VERSION 5.8 ;
BUSBITCHARS "[]" ;
DIVIDERCHAR "/" ;
UNITS
    DATABASE MICRONS 1000 ;
END UNITS

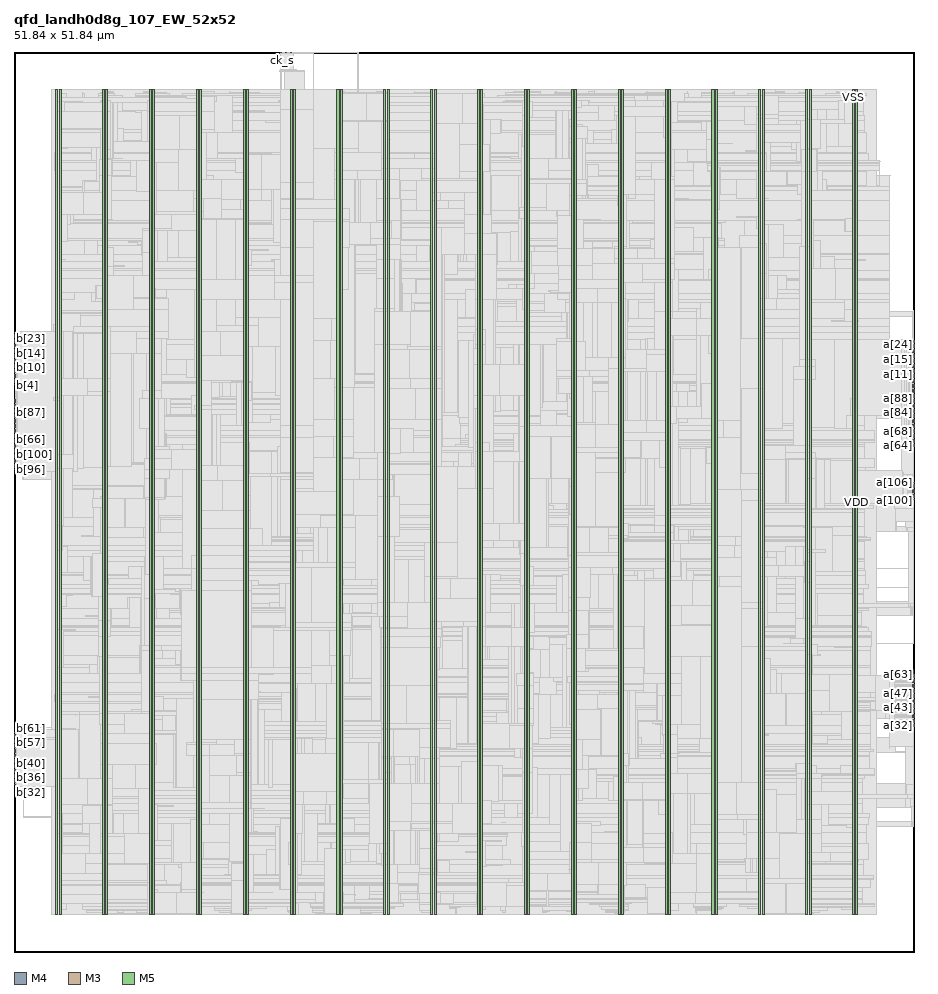
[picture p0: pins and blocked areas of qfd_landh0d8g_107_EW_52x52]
MACRO qfd_landh0d8g_107_EW_52x52
  FOREIGN qfd_landh0d8g_107_EW_52x52 0 0 ;
  CLASS BLOCK ;
  SIZE 51.84 BY 51.84 ;
  PIN a[0]
    DIRECTION INPUT ;
    USE SIGNAL ;
    PORT
      LAYER M4 ;
        RECT  51.756 32.208 51.84 32.232 ;
    END
  END a[0]
  PIN a[100]
    DIRECTION INPUT ;
    USE SIGNAL ;
    PORT
      LAYER M4 ;
        RECT  51.756 26.448 51.84 26.472 ;
    END
  END a[100]
  PIN a[101]
    DIRECTION INPUT ;
    USE SIGNAL ;
    PORT
      LAYER M4 ;
        RECT  51.756 26.544 51.84 26.568 ;
    END
  END a[101]
  PIN a[102]
    DIRECTION INPUT ;
    USE SIGNAL ;
    PORT
      LAYER M4 ;
        RECT  51.756 26.64 51.84 26.664 ;
    END
  END a[102]
  PIN a[103]
    DIRECTION INPUT ;
    USE SIGNAL ;
    PORT
      LAYER M4 ;
        RECT  51.756 26.736 51.84 26.76 ;
    END
  END a[103]
  PIN a[104]
    DIRECTION INPUT ;
    USE SIGNAL ;
    PORT
      LAYER M4 ;
        RECT  51.756 26.832 51.84 26.856 ;
    END
  END a[104]
  PIN a[105]
    DIRECTION INPUT ;
    USE SIGNAL ;
    PORT
      LAYER M4 ;
        RECT  51.756 26.928 51.84 26.952 ;
    END
  END a[105]
  PIN a[106]
    DIRECTION INPUT ;
    USE SIGNAL ;
    PORT
      LAYER M4 ;
        RECT  51.756 27.024 51.84 27.048 ;
    END
  END a[106]
  PIN a[10]
    DIRECTION INPUT ;
    USE SIGNAL ;
    PORT
      LAYER M4 ;
        RECT  51.756 33.168 51.84 33.192 ;
    END
  END a[10]
  PIN a[11]
    DIRECTION INPUT ;
    USE SIGNAL ;
    PORT
      LAYER M4 ;
        RECT  51.756 33.264 51.84 33.288 ;
    END
  END a[11]
  PIN a[12]
    DIRECTION INPUT ;
    USE SIGNAL ;
    PORT
      LAYER M4 ;
        RECT  51.756 33.36 51.84 33.384 ;
    END
  END a[12]
  PIN a[13]
    DIRECTION INPUT ;
    USE SIGNAL ;
    PORT
      LAYER M4 ;
        RECT  51.756 33.456 51.84 33.48 ;
    END
  END a[13]
  PIN a[14]
    DIRECTION INPUT ;
    USE SIGNAL ;
    PORT
      LAYER M4 ;
        RECT  51.756 33.552 51.84 33.576 ;
    END
  END a[14]
  PIN a[15]
    DIRECTION INPUT ;
    USE SIGNAL ;
    PORT
      LAYER M4 ;
        RECT  51.756 33.648 51.84 33.672 ;
    END
  END a[15]
  PIN a[16]
    DIRECTION INPUT ;
    USE SIGNAL ;
    PORT
      LAYER M4 ;
        RECT  51.756 33.744 51.84 33.768 ;
    END
  END a[16]
  PIN a[17]
    DIRECTION INPUT ;
    USE SIGNAL ;
    PORT
      LAYER M4 ;
        RECT  51.756 33.84 51.84 33.864 ;
    END
  END a[17]
  PIN a[18]
    DIRECTION INPUT ;
    USE SIGNAL ;
    PORT
      LAYER M4 ;
        RECT  51.756 33.936 51.84 33.96 ;
    END
  END a[18]
  PIN a[19]
    DIRECTION INPUT ;
    USE SIGNAL ;
    PORT
      LAYER M4 ;
        RECT  51.756 34.032 51.84 34.056 ;
    END
  END a[19]
  PIN a[1]
    DIRECTION INPUT ;
    USE SIGNAL ;
    PORT
      LAYER M4 ;
        RECT  51.756 32.304 51.84 32.328 ;
    END
  END a[1]
  PIN a[20]
    DIRECTION INPUT ;
    USE SIGNAL ;
    PORT
      LAYER M4 ;
        RECT  51.756 34.128 51.84 34.152 ;
    END
  END a[20]
  PIN a[21]
    DIRECTION INPUT ;
    USE SIGNAL ;
    PORT
      LAYER M4 ;
        RECT  51.756 34.224 51.84 34.248 ;
    END
  END a[21]
  PIN a[22]
    DIRECTION INPUT ;
    USE SIGNAL ;
    PORT
      LAYER M4 ;
        RECT  51.756 34.32 51.84 34.344 ;
    END
  END a[22]
  PIN a[23]
    DIRECTION INPUT ;
    USE SIGNAL ;
    PORT
      LAYER M4 ;
        RECT  51.756 34.416 51.84 34.44 ;
    END
  END a[23]
  PIN a[24]
    DIRECTION INPUT ;
    USE SIGNAL ;
    PORT
      LAYER M4 ;
        RECT  51.756 34.512 51.84 34.536 ;
    END
  END a[24]
  PIN a[25]
    DIRECTION INPUT ;
    USE SIGNAL ;
    PORT
      LAYER M4 ;
        RECT  51.756 34.608 51.84 34.632 ;
    END
  END a[25]
  PIN a[26]
    DIRECTION INPUT ;
    USE SIGNAL ;
    PORT
      LAYER M4 ;
        RECT  51.756 34.704 51.84 34.728 ;
    END
  END a[26]
  PIN a[27]
    DIRECTION INPUT ;
    USE SIGNAL ;
    PORT
      LAYER M4 ;
        RECT  51.756 34.8 51.84 34.824 ;
    END
  END a[27]
  PIN a[28]
    DIRECTION INPUT ;
    USE SIGNAL ;
    PORT
      LAYER M4 ;
        RECT  51.756 34.896 51.84 34.92 ;
    END
  END a[28]
  PIN a[29]
    DIRECTION INPUT ;
    USE SIGNAL ;
    PORT
      LAYER M4 ;
        RECT  51.756 34.992 51.84 35.016 ;
    END
  END a[29]
  PIN a[2]
    DIRECTION INPUT ;
    USE SIGNAL ;
    PORT
      LAYER M4 ;
        RECT  51.756 32.4 51.84 32.424 ;
    END
  END a[2]
  PIN a[30]
    DIRECTION INPUT ;
    USE SIGNAL ;
    PORT
      LAYER M4 ;
        RECT  51.756 35.088 51.84 35.112 ;
    END
  END a[30]
  PIN a[31]
    DIRECTION INPUT ;
    USE SIGNAL ;
    PORT
      LAYER M4 ;
        RECT  51.756 35.184 51.84 35.208 ;
    END
  END a[31]
  PIN a[32]
    DIRECTION INPUT ;
    USE SIGNAL ;
    PORT
      LAYER M4 ;
        RECT  51.756 13.008 51.84 13.032 ;
    END
  END a[32]
  PIN a[33]
    DIRECTION INPUT ;
    USE SIGNAL ;
    PORT
      LAYER M4 ;
        RECT  51.756 13.104 51.84 13.128 ;
    END
  END a[33]
  PIN a[34]
    DIRECTION INPUT ;
    USE SIGNAL ;
    PORT
      LAYER M4 ;
        RECT  51.756 13.2 51.84 13.224 ;
    END
  END a[34]
  PIN a[35]
    DIRECTION INPUT ;
    USE SIGNAL ;
    PORT
      LAYER M4 ;
        RECT  51.756 13.296 51.84 13.32 ;
    END
  END a[35]
  PIN a[36]
    DIRECTION INPUT ;
    USE SIGNAL ;
    PORT
      LAYER M4 ;
        RECT  51.756 13.392 51.84 13.416 ;
    END
  END a[36]
  PIN a[37]
    DIRECTION INPUT ;
    USE SIGNAL ;
    PORT
      LAYER M4 ;
        RECT  51.756 13.488 51.84 13.512 ;
    END
  END a[37]
  PIN a[38]
    DIRECTION INPUT ;
    USE SIGNAL ;
    PORT
      LAYER M4 ;
        RECT  51.756 13.584 51.84 13.608 ;
    END
  END a[38]
  PIN a[39]
    DIRECTION INPUT ;
    USE SIGNAL ;
    PORT
      LAYER M4 ;
        RECT  51.756 13.68 51.84 13.704 ;
    END
  END a[39]
  PIN a[3]
    DIRECTION INPUT ;
    USE SIGNAL ;
    PORT
      LAYER M4 ;
        RECT  51.756 32.496 51.84 32.52 ;
    END
  END a[3]
  PIN a[40]
    DIRECTION INPUT ;
    USE SIGNAL ;
    PORT
      LAYER M4 ;
        RECT  51.756 13.776 51.84 13.8 ;
    END
  END a[40]
  PIN a[41]
    DIRECTION INPUT ;
    USE SIGNAL ;
    PORT
      LAYER M4 ;
        RECT  51.756 13.872 51.84 13.896 ;
    END
  END a[41]
  PIN a[42]
    DIRECTION INPUT ;
    USE SIGNAL ;
    PORT
      LAYER M4 ;
        RECT  51.756 13.968 51.84 13.992 ;
    END
  END a[42]
  PIN a[43]
    DIRECTION INPUT ;
    USE SIGNAL ;
    PORT
      LAYER M4 ;
        RECT  51.756 14.064 51.84 14.088 ;
    END
  END a[43]
  PIN a[44]
    DIRECTION INPUT ;
    USE SIGNAL ;
    PORT
      LAYER M4 ;
        RECT  51.756 14.16 51.84 14.184 ;
    END
  END a[44]
  PIN a[45]
    DIRECTION INPUT ;
    USE SIGNAL ;
    PORT
      LAYER M4 ;
        RECT  51.756 14.256 51.84 14.28 ;
    END
  END a[45]
  PIN a[46]
    DIRECTION INPUT ;
    USE SIGNAL ;
    PORT
      LAYER M4 ;
        RECT  51.756 14.352 51.84 14.376 ;
    END
  END a[46]
  PIN a[47]
    DIRECTION INPUT ;
    USE SIGNAL ;
    PORT
      LAYER M4 ;
        RECT  51.756 14.448 51.84 14.472 ;
    END
  END a[47]
  PIN a[48]
    DIRECTION INPUT ;
    USE SIGNAL ;
    PORT
      LAYER M4 ;
        RECT  51.756 14.544 51.84 14.568 ;
    END
  END a[48]
  PIN a[49]
    DIRECTION INPUT ;
    USE SIGNAL ;
    PORT
      LAYER M4 ;
        RECT  51.756 14.64 51.84 14.664 ;
    END
  END a[49]
  PIN a[4]
    DIRECTION INPUT ;
    USE SIGNAL ;
    PORT
      LAYER M4 ;
        RECT  51.756 32.592 51.84 32.616 ;
    END
  END a[4]
  PIN a[50]
    DIRECTION INPUT ;
    USE SIGNAL ;
    PORT
      LAYER M4 ;
        RECT  51.756 14.736 51.84 14.76 ;
    END
  END a[50]
  PIN a[51]
    DIRECTION INPUT ;
    USE SIGNAL ;
    PORT
      LAYER M4 ;
        RECT  51.756 14.832 51.84 14.856 ;
    END
  END a[51]
  PIN a[52]
    DIRECTION INPUT ;
    USE SIGNAL ;
    PORT
      LAYER M4 ;
        RECT  51.756 14.928 51.84 14.952 ;
    END
  END a[52]
  PIN a[53]
    DIRECTION INPUT ;
    USE SIGNAL ;
    PORT
      LAYER M4 ;
        RECT  51.756 15.024 51.84 15.048 ;
    END
  END a[53]
  PIN a[54]
    DIRECTION INPUT ;
    USE SIGNAL ;
    PORT
      LAYER M4 ;
        RECT  51.756 15.12 51.84 15.144 ;
    END
  END a[54]
  PIN a[55]
    DIRECTION INPUT ;
    USE SIGNAL ;
    PORT
      LAYER M4 ;
        RECT  51.756 15.216 51.84 15.24 ;
    END
  END a[55]
  PIN a[56]
    DIRECTION INPUT ;
    USE SIGNAL ;
    PORT
      LAYER M4 ;
        RECT  51.756 15.312 51.84 15.336 ;
    END
  END a[56]
  PIN a[57]
    DIRECTION INPUT ;
    USE SIGNAL ;
    PORT
      LAYER M4 ;
        RECT  51.756 15.408 51.84 15.432 ;
    END
  END a[57]
  PIN a[58]
    DIRECTION INPUT ;
    USE SIGNAL ;
    PORT
      LAYER M4 ;
        RECT  51.756 15.504 51.84 15.528 ;
    END
  END a[58]
  PIN a[59]
    DIRECTION INPUT ;
    USE SIGNAL ;
    PORT
      LAYER M4 ;
        RECT  51.756 15.6 51.84 15.624 ;
    END
  END a[59]
  PIN a[5]
    DIRECTION INPUT ;
    USE SIGNAL ;
    PORT
      LAYER M4 ;
        RECT  51.756 32.688 51.84 32.712 ;
    END
  END a[5]
  PIN a[60]
    DIRECTION INPUT ;
    USE SIGNAL ;
    PORT
      LAYER M4 ;
        RECT  51.756 15.696 51.84 15.72 ;
    END
  END a[60]
  PIN a[61]
    DIRECTION INPUT ;
    USE SIGNAL ;
    PORT
      LAYER M4 ;
        RECT  51.756 15.792 51.84 15.816 ;
    END
  END a[61]
  PIN a[62]
    DIRECTION INPUT ;
    USE SIGNAL ;
    PORT
      LAYER M4 ;
        RECT  51.756 15.888 51.84 15.912 ;
    END
  END a[62]
  PIN a[63]
    DIRECTION INPUT ;
    USE SIGNAL ;
    PORT
      LAYER M4 ;
        RECT  51.756 15.984 51.84 16.008 ;
    END
  END a[63]
  PIN a[64]
    DIRECTION INPUT ;
    USE SIGNAL ;
    PORT
      LAYER M4 ;
        RECT  51.756 29.136 51.84 29.16 ;
    END
  END a[64]
  PIN a[65]
    DIRECTION INPUT ;
    USE SIGNAL ;
    PORT
      LAYER M4 ;
        RECT  51.756 29.232 51.84 29.256 ;
    END
  END a[65]
  PIN a[66]
    DIRECTION INPUT ;
    USE SIGNAL ;
    PORT
      LAYER M4 ;
        RECT  51.756 29.328 51.84 29.352 ;
    END
  END a[66]
  PIN a[67]
    DIRECTION INPUT ;
    USE SIGNAL ;
    PORT
      LAYER M4 ;
        RECT  51.756 29.424 51.84 29.448 ;
    END
  END a[67]
  PIN a[68]
    DIRECTION INPUT ;
    USE SIGNAL ;
    PORT
      LAYER M4 ;
        RECT  51.756 29.52 51.84 29.544 ;
    END
  END a[68]
  PIN a[69]
    DIRECTION INPUT ;
    USE SIGNAL ;
    PORT
      LAYER M4 ;
        RECT  51.756 29.616 51.84 29.64 ;
    END
  END a[69]
  PIN a[6]
    DIRECTION INPUT ;
    USE SIGNAL ;
    PORT
      LAYER M4 ;
        RECT  51.756 32.784 51.84 32.808 ;
    END
  END a[6]
  PIN a[70]
    DIRECTION INPUT ;
    USE SIGNAL ;
    PORT
      LAYER M4 ;
        RECT  51.756 29.712 51.84 29.736 ;
    END
  END a[70]
  PIN a[71]
    DIRECTION INPUT ;
    USE SIGNAL ;
    PORT
      LAYER M4 ;
        RECT  51.756 29.808 51.84 29.832 ;
    END
  END a[71]
  PIN a[72]
    DIRECTION INPUT ;
    USE SIGNAL ;
    PORT
      LAYER M4 ;
        RECT  51.756 29.904 51.84 29.928 ;
    END
  END a[72]
  PIN a[73]
    DIRECTION INPUT ;
    USE SIGNAL ;
    PORT
      LAYER M4 ;
        RECT  51.756 30 51.84 30.024 ;
    END
  END a[73]
  PIN a[74]
    DIRECTION INPUT ;
    USE SIGNAL ;
    PORT
      LAYER M4 ;
        RECT  51.756 30.096 51.84 30.12 ;
    END
  END a[74]
  PIN a[75]
    DIRECTION INPUT ;
    USE SIGNAL ;
    PORT
      LAYER M4 ;
        RECT  51.756 30.192 51.84 30.216 ;
    END
  END a[75]
  PIN a[76]
    DIRECTION INPUT ;
    USE SIGNAL ;
    PORT
      LAYER M4 ;
        RECT  51.756 30.288 51.84 30.312 ;
    END
  END a[76]
  PIN a[77]
    DIRECTION INPUT ;
    USE SIGNAL ;
    PORT
      LAYER M4 ;
        RECT  51.756 30.384 51.84 30.408 ;
    END
  END a[77]
  PIN a[78]
    DIRECTION INPUT ;
    USE SIGNAL ;
    PORT
      LAYER M4 ;
        RECT  51.756 30.48 51.84 30.504 ;
    END
  END a[78]
  PIN a[79]
    DIRECTION INPUT ;
    USE SIGNAL ;
    PORT
      LAYER M4 ;
        RECT  51.756 30.576 51.84 30.6 ;
    END
  END a[79]
  PIN a[7]
    DIRECTION INPUT ;
    USE SIGNAL ;
    PORT
      LAYER M4 ;
        RECT  51.756 32.88 51.84 32.904 ;
    END
  END a[7]
  PIN a[80]
    DIRECTION INPUT ;
    USE SIGNAL ;
    PORT
      LAYER M4 ;
        RECT  51.756 30.672 51.84 30.696 ;
    END
  END a[80]
  PIN a[81]
    DIRECTION INPUT ;
    USE SIGNAL ;
    PORT
      LAYER M4 ;
        RECT  51.756 30.768 51.84 30.792 ;
    END
  END a[81]
  PIN a[82]
    DIRECTION INPUT ;
    USE SIGNAL ;
    PORT
      LAYER M4 ;
        RECT  51.756 30.864 51.84 30.888 ;
    END
  END a[82]
  PIN a[83]
    DIRECTION INPUT ;
    USE SIGNAL ;
    PORT
      LAYER M4 ;
        RECT  51.756 30.96 51.84 30.984 ;
    END
  END a[83]
  PIN a[84]
    DIRECTION INPUT ;
    USE SIGNAL ;
    PORT
      LAYER M4 ;
        RECT  51.756 31.056 51.84 31.08 ;
    END
  END a[84]
  PIN a[85]
    DIRECTION INPUT ;
    USE SIGNAL ;
    PORT
      LAYER M4 ;
        RECT  51.756 31.152 51.84 31.176 ;
    END
  END a[85]
  PIN a[86]
    DIRECTION INPUT ;
    USE SIGNAL ;
    PORT
      LAYER M4 ;
        RECT  51.756 31.248 51.84 31.272 ;
    END
  END a[86]
  PIN a[87]
    DIRECTION INPUT ;
    USE SIGNAL ;
    PORT
      LAYER M4 ;
        RECT  51.756 31.344 51.84 31.368 ;
    END
  END a[87]
  PIN a[88]
    DIRECTION INPUT ;
    USE SIGNAL ;
    PORT
      LAYER M4 ;
        RECT  51.756 31.44 51.84 31.464 ;
    END
  END a[88]
  PIN a[89]
    DIRECTION INPUT ;
    USE SIGNAL ;
    PORT
      LAYER M4 ;
        RECT  51.756 31.536 51.84 31.56 ;
    END
  END a[89]
  PIN a[8]
    DIRECTION INPUT ;
    USE SIGNAL ;
    PORT
      LAYER M4 ;
        RECT  51.756 32.976 51.84 33 ;
    END
  END a[8]
  PIN a[90]
    DIRECTION INPUT ;
    USE SIGNAL ;
    PORT
      LAYER M4 ;
        RECT  51.756 31.632 51.84 31.656 ;
    END
  END a[90]
  PIN a[91]
    DIRECTION INPUT ;
    USE SIGNAL ;
    PORT
      LAYER M4 ;
        RECT  51.756 31.728 51.84 31.752 ;
    END
  END a[91]
  PIN a[92]
    DIRECTION INPUT ;
    USE SIGNAL ;
    PORT
      LAYER M4 ;
        RECT  51.756 31.824 51.84 31.848 ;
    END
  END a[92]
  PIN a[93]
    DIRECTION INPUT ;
    USE SIGNAL ;
    PORT
      LAYER M4 ;
        RECT  51.756 31.92 51.84 31.944 ;
    END
  END a[93]
  PIN a[94]
    DIRECTION INPUT ;
    USE SIGNAL ;
    PORT
      LAYER M4 ;
        RECT  51.756 32.016 51.84 32.04 ;
    END
  END a[94]
  PIN a[95]
    DIRECTION INPUT ;
    USE SIGNAL ;
    PORT
      LAYER M4 ;
        RECT  51.756 32.112 51.84 32.136 ;
    END
  END a[95]
  PIN a[96]
    DIRECTION INPUT ;
    USE SIGNAL ;
    PORT
      LAYER M4 ;
        RECT  51.756 26.064 51.84 26.088 ;
    END
  END a[96]
  PIN a[97]
    DIRECTION INPUT ;
    USE SIGNAL ;
    PORT
      LAYER M4 ;
        RECT  51.756 26.16 51.84 26.184 ;
    END
  END a[97]
  PIN a[98]
    DIRECTION INPUT ;
    USE SIGNAL ;
    PORT
      LAYER M4 ;
        RECT  51.756 26.256 51.84 26.28 ;
    END
  END a[98]
  PIN a[99]
    DIRECTION INPUT ;
    USE SIGNAL ;
    PORT
      LAYER M4 ;
        RECT  51.756 26.352 51.84 26.376 ;
    END
  END a[99]
  PIN a[9]
    DIRECTION INPUT ;
    USE SIGNAL ;
    PORT
      LAYER M4 ;
        RECT  51.756 33.072 51.84 33.096 ;
    END
  END a[9]
  PIN b[0]
    DIRECTION OUTPUT ;
    USE SIGNAL ;
    PORT
      LAYER M4 ;
        RECT  0 32.688 0.084 32.712 ;
    END
  END b[0]
  PIN b[100]
    DIRECTION OUTPUT ;
    USE SIGNAL ;
    PORT
      LAYER M4 ;
        RECT  0 28.176 0.084 28.2 ;
    END
  END b[100]
  PIN b[101]
    DIRECTION OUTPUT ;
    USE SIGNAL ;
    PORT
      LAYER M4 ;
        RECT  0 28.272 0.084 28.296 ;
    END
  END b[101]
  PIN b[102]
    DIRECTION OUTPUT ;
    USE SIGNAL ;
    PORT
      LAYER M4 ;
        RECT  0 28.368 0.084 28.392 ;
    END
  END b[102]
  PIN b[103]
    DIRECTION OUTPUT ;
    USE SIGNAL ;
    PORT
      LAYER M4 ;
        RECT  0 28.464 0.084 28.488 ;
    END
  END b[103]
  PIN b[104]
    DIRECTION OUTPUT ;
    USE SIGNAL ;
    PORT
      LAYER M4 ;
        RECT  0 28.56 0.084 28.584 ;
    END
  END b[104]
  PIN b[105]
    DIRECTION OUTPUT ;
    USE SIGNAL ;
    PORT
      LAYER M4 ;
        RECT  0 28.656 0.084 28.68 ;
    END
  END b[105]
  PIN b[106]
    DIRECTION OUTPUT ;
    USE SIGNAL ;
    PORT
      LAYER M4 ;
        RECT  0 28.752 0.084 28.776 ;
    END
  END b[106]
  PIN b[10]
    DIRECTION OUTPUT ;
    USE SIGNAL ;
    PORT
      LAYER M4 ;
        RECT  0 33.648 0.084 33.672 ;
    END
  END b[10]
  PIN b[11]
    DIRECTION OUTPUT ;
    USE SIGNAL ;
    PORT
      LAYER M4 ;
        RECT  0 33.744 0.084 33.768 ;
    END
  END b[11]
  PIN b[12]
    DIRECTION OUTPUT ;
    USE SIGNAL ;
    PORT
      LAYER M4 ;
        RECT  0 33.84 0.084 33.864 ;
    END
  END b[12]
  PIN b[13]
    DIRECTION OUTPUT ;
    USE SIGNAL ;
    PORT
      LAYER M4 ;
        RECT  0 33.936 0.084 33.96 ;
    END
  END b[13]
  PIN b[14]
    DIRECTION OUTPUT ;
    USE SIGNAL ;
    PORT
      LAYER M4 ;
        RECT  0 34.032 0.084 34.056 ;
    END
  END b[14]
  PIN b[15]
    DIRECTION OUTPUT ;
    USE SIGNAL ;
    PORT
      LAYER M4 ;
        RECT  0 34.128 0.084 34.152 ;
    END
  END b[15]
  PIN b[16]
    DIRECTION OUTPUT ;
    USE SIGNAL ;
    PORT
      LAYER M4 ;
        RECT  0 34.224 0.084 34.248 ;
    END
  END b[16]
  PIN b[17]
    DIRECTION OUTPUT ;
    USE SIGNAL ;
    PORT
      LAYER M4 ;
        RECT  0 34.32 0.084 34.344 ;
    END
  END b[17]
  PIN b[18]
    DIRECTION OUTPUT ;
    USE SIGNAL ;
    PORT
      LAYER M4 ;
        RECT  0 34.416 0.084 34.44 ;
    END
  END b[18]
  PIN b[19]
    DIRECTION OUTPUT ;
    USE SIGNAL ;
    PORT
      LAYER M4 ;
        RECT  0 34.512 0.084 34.536 ;
    END
  END b[19]
  PIN b[1]
    DIRECTION OUTPUT ;
    USE SIGNAL ;
    PORT
      LAYER M4 ;
        RECT  0 32.784 0.084 32.808 ;
    END
  END b[1]
  PIN b[20]
    DIRECTION OUTPUT ;
    USE SIGNAL ;
    PORT
      LAYER M4 ;
        RECT  0 34.608 0.084 34.632 ;
    END
  END b[20]
  PIN b[21]
    DIRECTION OUTPUT ;
    USE SIGNAL ;
    PORT
      LAYER M4 ;
        RECT  0 34.704 0.084 34.728 ;
    END
  END b[21]
  PIN b[22]
    DIRECTION OUTPUT ;
    USE SIGNAL ;
    PORT
      LAYER M4 ;
        RECT  0 34.8 0.084 34.824 ;
    END
  END b[22]
  PIN b[23]
    DIRECTION OUTPUT ;
    USE SIGNAL ;
    PORT
      LAYER M4 ;
        RECT  0 34.896 0.084 34.92 ;
    END
  END b[23]
  PIN b[24]
    DIRECTION OUTPUT ;
    USE SIGNAL ;
    PORT
      LAYER M4 ;
        RECT  0 34.992 0.084 35.016 ;
    END
  END b[24]
  PIN b[25]
    DIRECTION OUTPUT ;
    USE SIGNAL ;
    PORT
      LAYER M4 ;
        RECT  0 35.088 0.084 35.112 ;
    END
  END b[25]
  PIN b[26]
    DIRECTION OUTPUT ;
    USE SIGNAL ;
    PORT
      LAYER M4 ;
        RECT  0 35.184 0.084 35.208 ;
    END
  END b[26]
  PIN b[27]
    DIRECTION OUTPUT ;
    USE SIGNAL ;
    PORT
      LAYER M4 ;
        RECT  0 35.28 0.084 35.304 ;
    END
  END b[27]
  PIN b[28]
    DIRECTION OUTPUT ;
    USE SIGNAL ;
    PORT
      LAYER M4 ;
        RECT  0 35.376 0.084 35.4 ;
    END
  END b[28]
  PIN b[29]
    DIRECTION OUTPUT ;
    USE SIGNAL ;
    PORT
      LAYER M4 ;
        RECT  0 35.472 0.084 35.496 ;
    END
  END b[29]
  PIN b[2]
    DIRECTION OUTPUT ;
    USE SIGNAL ;
    PORT
      LAYER M4 ;
        RECT  0 32.88 0.084 32.904 ;
    END
  END b[2]
  PIN b[30]
    DIRECTION OUTPUT ;
    USE SIGNAL ;
    PORT
      LAYER M4 ;
        RECT  0 35.568 0.084 35.592 ;
    END
  END b[30]
  PIN b[31]
    DIRECTION OUTPUT ;
    USE SIGNAL ;
    PORT
      LAYER M4 ;
        RECT  0 35.664 0.084 35.688 ;
    END
  END b[31]
  PIN b[32]
    DIRECTION OUTPUT ;
    USE SIGNAL ;
    PORT
      LAYER M4 ;
        RECT  0 9.648 0.084 9.672 ;
    END
  END b[32]
  PIN b[33]
    DIRECTION OUTPUT ;
    USE SIGNAL ;
    PORT
      LAYER M4 ;
        RECT  0 9.744 0.084 9.768 ;
    END
  END b[33]
  PIN b[34]
    DIRECTION OUTPUT ;
    USE SIGNAL ;
    PORT
      LAYER M4 ;
        RECT  0 9.84 0.084 9.864 ;
    END
  END b[34]
  PIN b[35]
    DIRECTION OUTPUT ;
    USE SIGNAL ;
    PORT
      LAYER M4 ;
        RECT  0 9.936 0.084 9.96 ;
    END
  END b[35]
  PIN b[36]
    DIRECTION OUTPUT ;
    USE SIGNAL ;
    PORT
      LAYER M4 ;
        RECT  0 10.032 0.084 10.056 ;
    END
  END b[36]
  PIN b[37]
    DIRECTION OUTPUT ;
    USE SIGNAL ;
    PORT
      LAYER M4 ;
        RECT  0 10.128 0.084 10.152 ;
    END
  END b[37]
  PIN b[38]
    DIRECTION OUTPUT ;
    USE SIGNAL ;
    PORT
      LAYER M4 ;
        RECT  0 10.224 0.084 10.248 ;
    END
  END b[38]
  PIN b[39]
    DIRECTION OUTPUT ;
    USE SIGNAL ;
    PORT
      LAYER M4 ;
        RECT  0 10.32 0.084 10.344 ;
    END
  END b[39]
  PIN b[3]
    DIRECTION OUTPUT ;
    USE SIGNAL ;
    PORT
      LAYER M4 ;
        RECT  0 32.976 0.084 33 ;
    END
  END b[3]
  PIN b[40]
    DIRECTION OUTPUT ;
    USE SIGNAL ;
    PORT
      LAYER M4 ;
        RECT  0 10.416 0.084 10.44 ;
    END
  END b[40]
  PIN b[41]
    DIRECTION OUTPUT ;
    USE SIGNAL ;
    PORT
      LAYER M4 ;
        RECT  0 10.512 0.084 10.536 ;
    END
  END b[41]
  PIN b[42]
    DIRECTION OUTPUT ;
    USE SIGNAL ;
    PORT
      LAYER M4 ;
        RECT  0 10.608 0.084 10.632 ;
    END
  END b[42]
  PIN b[43]
    DIRECTION OUTPUT ;
    USE SIGNAL ;
    PORT
      LAYER M4 ;
        RECT  0 10.704 0.084 10.728 ;
    END
  END b[43]
  PIN b[44]
    DIRECTION OUTPUT ;
    USE SIGNAL ;
    PORT
      LAYER M4 ;
        RECT  0 10.8 0.084 10.824 ;
    END
  END b[44]
  PIN b[45]
    DIRECTION OUTPUT ;
    USE SIGNAL ;
    PORT
      LAYER M4 ;
        RECT  0 10.896 0.084 10.92 ;
    END
  END b[45]
  PIN b[46]
    DIRECTION OUTPUT ;
    USE SIGNAL ;
    PORT
      LAYER M4 ;
        RECT  0 10.992 0.084 11.016 ;
    END
  END b[46]
  PIN b[47]
    DIRECTION OUTPUT ;
    USE SIGNAL ;
    PORT
      LAYER M4 ;
        RECT  0 11.088 0.084 11.112 ;
    END
  END b[47]
  PIN b[48]
    DIRECTION OUTPUT ;
    USE SIGNAL ;
    PORT
      LAYER M4 ;
        RECT  0 11.184 0.084 11.208 ;
    END
  END b[48]
  PIN b[49]
    DIRECTION OUTPUT ;
    USE SIGNAL ;
    PORT
      LAYER M4 ;
        RECT  0 11.28 0.084 11.304 ;
    END
  END b[49]
  PIN b[4]
    DIRECTION OUTPUT ;
    USE SIGNAL ;
    PORT
      LAYER M4 ;
        RECT  0 33.072 0.084 33.096 ;
    END
  END b[4]
  PIN b[50]
    DIRECTION OUTPUT ;
    USE SIGNAL ;
    PORT
      LAYER M4 ;
        RECT  0 11.376 0.084 11.4 ;
    END
  END b[50]
  PIN b[51]
    DIRECTION OUTPUT ;
    USE SIGNAL ;
    PORT
      LAYER M4 ;
        RECT  0 11.472 0.084 11.496 ;
    END
  END b[51]
  PIN b[52]
    DIRECTION OUTPUT ;
    USE SIGNAL ;
    PORT
      LAYER M4 ;
        RECT  0 11.568 0.084 11.592 ;
    END
  END b[52]
  PIN b[53]
    DIRECTION OUTPUT ;
    USE SIGNAL ;
    PORT
      LAYER M4 ;
        RECT  0 11.664 0.084 11.688 ;
    END
  END b[53]
  PIN b[54]
    DIRECTION OUTPUT ;
    USE SIGNAL ;
    PORT
      LAYER M4 ;
        RECT  0 11.76 0.084 11.784 ;
    END
  END b[54]
  PIN b[55]
    DIRECTION OUTPUT ;
    USE SIGNAL ;
    PORT
      LAYER M4 ;
        RECT  0 11.856 0.084 11.88 ;
    END
  END b[55]
  PIN b[56]
    DIRECTION OUTPUT ;
    USE SIGNAL ;
    PORT
      LAYER M4 ;
        RECT  0 11.952 0.084 11.976 ;
    END
  END b[56]
  PIN b[57]
    DIRECTION OUTPUT ;
    USE SIGNAL ;
    PORT
      LAYER M4 ;
        RECT  0 12.048 0.084 12.072 ;
    END
  END b[57]
  PIN b[58]
    DIRECTION OUTPUT ;
    USE SIGNAL ;
    PORT
      LAYER M4 ;
        RECT  0 12.144 0.084 12.168 ;
    END
  END b[58]
  PIN b[59]
    DIRECTION OUTPUT ;
    USE SIGNAL ;
    PORT
      LAYER M4 ;
        RECT  0 12.24 0.084 12.264 ;
    END
  END b[59]
  PIN b[5]
    DIRECTION OUTPUT ;
    USE SIGNAL ;
    PORT
      LAYER M4 ;
        RECT  0 33.168 0.084 33.192 ;
    END
  END b[5]
  PIN b[60]
    DIRECTION OUTPUT ;
    USE SIGNAL ;
    PORT
      LAYER M4 ;
        RECT  0 12.336 0.084 12.36 ;
    END
  END b[60]
  PIN b[61]
    DIRECTION OUTPUT ;
    USE SIGNAL ;
    PORT
      LAYER M4 ;
        RECT  0 12.432 0.084 12.456 ;
    END
  END b[61]
  PIN b[62]
    DIRECTION OUTPUT ;
    USE SIGNAL ;
    PORT
      LAYER M4 ;
        RECT  0 12.528 0.084 12.552 ;
    END
  END b[62]
  PIN b[63]
    DIRECTION OUTPUT ;
    USE SIGNAL ;
    PORT
      LAYER M4 ;
        RECT  0 12.624 0.084 12.648 ;
    END
  END b[63]
  PIN b[64]
    DIRECTION OUTPUT ;
    USE SIGNAL ;
    PORT
      LAYER M4 ;
        RECT  0 28.848 0.084 28.872 ;
    END
  END b[64]
  PIN b[65]
    DIRECTION OUTPUT ;
    USE SIGNAL ;
    PORT
      LAYER M4 ;
        RECT  0 28.944 0.084 28.968 ;
    END
  END b[65]
  PIN b[66]
    DIRECTION OUTPUT ;
    USE SIGNAL ;
    PORT
      LAYER M4 ;
        RECT  0 29.04 0.084 29.064 ;
    END
  END b[66]
  PIN b[67]
    DIRECTION OUTPUT ;
    USE SIGNAL ;
    PORT
      LAYER M4 ;
        RECT  0 29.136 0.084 29.16 ;
    END
  END b[67]
  PIN b[68]
    DIRECTION OUTPUT ;
    USE SIGNAL ;
    PORT
      LAYER M4 ;
        RECT  0 29.232 0.084 29.256 ;
    END
  END b[68]
  PIN b[69]
    DIRECTION OUTPUT ;
    USE SIGNAL ;
    PORT
      LAYER M4 ;
        RECT  0 29.328 0.084 29.352 ;
    END
  END b[69]
  PIN b[6]
    DIRECTION OUTPUT ;
    USE SIGNAL ;
    PORT
      LAYER M4 ;
        RECT  0 33.264 0.084 33.288 ;
    END
  END b[6]
  PIN b[70]
    DIRECTION OUTPUT ;
    USE SIGNAL ;
    PORT
      LAYER M4 ;
        RECT  0 29.424 0.084 29.448 ;
    END
  END b[70]
  PIN b[71]
    DIRECTION OUTPUT ;
    USE SIGNAL ;
    PORT
      LAYER M4 ;
        RECT  0 29.52 0.084 29.544 ;
    END
  END b[71]
  PIN b[72]
    DIRECTION OUTPUT ;
    USE SIGNAL ;
    PORT
      LAYER M4 ;
        RECT  0 29.616 0.084 29.64 ;
    END
  END b[72]
  PIN b[73]
    DIRECTION OUTPUT ;
    USE SIGNAL ;
    PORT
      LAYER M4 ;
        RECT  0 29.712 0.084 29.736 ;
    END
  END b[73]
  PIN b[74]
    DIRECTION OUTPUT ;
    USE SIGNAL ;
    PORT
      LAYER M4 ;
        RECT  0 29.808 0.084 29.832 ;
    END
  END b[74]
  PIN b[75]
    DIRECTION OUTPUT ;
    USE SIGNAL ;
    PORT
      LAYER M4 ;
        RECT  0 29.904 0.084 29.928 ;
    END
  END b[75]
  PIN b[76]
    DIRECTION OUTPUT ;
    USE SIGNAL ;
    PORT
      LAYER M4 ;
        RECT  0 30 0.084 30.024 ;
    END
  END b[76]
  PIN b[77]
    DIRECTION OUTPUT ;
    USE SIGNAL ;
    PORT
      LAYER M4 ;
        RECT  0 30.096 0.084 30.12 ;
    END
  END b[77]
  PIN b[78]
    DIRECTION OUTPUT ;
    USE SIGNAL ;
    PORT
      LAYER M4 ;
        RECT  0 30.192 0.084 30.216 ;
    END
  END b[78]
  PIN b[79]
    DIRECTION OUTPUT ;
    USE SIGNAL ;
    PORT
      LAYER M4 ;
        RECT  0 30.288 0.084 30.312 ;
    END
  END b[79]
  PIN b[7]
    DIRECTION OUTPUT ;
    USE SIGNAL ;
    PORT
      LAYER M4 ;
        RECT  0 33.36 0.084 33.384 ;
    END
  END b[7]
  PIN b[80]
    DIRECTION OUTPUT ;
    USE SIGNAL ;
    PORT
      LAYER M4 ;
        RECT  0 30.384 0.084 30.408 ;
    END
  END b[80]
  PIN b[81]
    DIRECTION OUTPUT ;
    USE SIGNAL ;
    PORT
      LAYER M4 ;
        RECT  0 30.48 0.084 30.504 ;
    END
  END b[81]
  PIN b[82]
    DIRECTION OUTPUT ;
    USE SIGNAL ;
    PORT
      LAYER M4 ;
        RECT  0 30.576 0.084 30.6 ;
    END
  END b[82]
  PIN b[83]
    DIRECTION OUTPUT ;
    USE SIGNAL ;
    PORT
      LAYER M4 ;
        RECT  0 30.672 0.084 30.696 ;
    END
  END b[83]
  PIN b[84]
    DIRECTION OUTPUT ;
    USE SIGNAL ;
    PORT
      LAYER M4 ;
        RECT  0 30.768 0.084 30.792 ;
    END
  END b[84]
  PIN b[85]
    DIRECTION OUTPUT ;
    USE SIGNAL ;
    PORT
      LAYER M4 ;
        RECT  0 30.864 0.084 30.888 ;
    END
  END b[85]
  PIN b[86]
    DIRECTION OUTPUT ;
    USE SIGNAL ;
    PORT
      LAYER M4 ;
        RECT  0 30.96 0.084 30.984 ;
    END
  END b[86]
  PIN b[87]
    DIRECTION OUTPUT ;
    USE SIGNAL ;
    PORT
      LAYER M4 ;
        RECT  0 31.056 0.084 31.08 ;
    END
  END b[87]
  PIN b[88]
    DIRECTION OUTPUT ;
    USE SIGNAL ;
    PORT
      LAYER M4 ;
        RECT  0 31.152 0.084 31.176 ;
    END
  END b[88]
  PIN b[89]
    DIRECTION OUTPUT ;
    USE SIGNAL ;
    PORT
      LAYER M4 ;
        RECT  0 31.248 0.084 31.272 ;
    END
  END b[89]
  PIN b[8]
    DIRECTION OUTPUT ;
    USE SIGNAL ;
    PORT
      LAYER M4 ;
        RECT  0 33.456 0.084 33.48 ;
    END
  END b[8]
  PIN b[90]
    DIRECTION OUTPUT ;
    USE SIGNAL ;
    PORT
      LAYER M4 ;
        RECT  0 31.344 0.084 31.368 ;
    END
  END b[90]
  PIN b[91]
    DIRECTION OUTPUT ;
    USE SIGNAL ;
    PORT
      LAYER M4 ;
        RECT  0 31.44 0.084 31.464 ;
    END
  END b[91]
  PIN b[92]
    DIRECTION OUTPUT ;
    USE SIGNAL ;
    PORT
      LAYER M4 ;
        RECT  0 31.536 0.084 31.56 ;
    END
  END b[92]
  PIN b[93]
    DIRECTION OUTPUT ;
    USE SIGNAL ;
    PORT
      LAYER M4 ;
        RECT  0 31.632 0.084 31.656 ;
    END
  END b[93]
  PIN b[94]
    DIRECTION OUTPUT ;
    USE SIGNAL ;
    PORT
      LAYER M4 ;
        RECT  0 31.728 0.084 31.752 ;
    END
  END b[94]
  PIN b[95]
    DIRECTION OUTPUT ;
    USE SIGNAL ;
    PORT
      LAYER M4 ;
        RECT  0 31.824 0.084 31.848 ;
    END
  END b[95]
  PIN b[96]
    DIRECTION OUTPUT ;
    USE SIGNAL ;
    PORT
      LAYER M4 ;
        RECT  0 27.792 0.084 27.816 ;
    END
  END b[96]
  PIN b[97]
    DIRECTION OUTPUT ;
    USE SIGNAL ;
    PORT
      LAYER M4 ;
        RECT  0 27.888 0.084 27.912 ;
    END
  END b[97]
  PIN b[98]
    DIRECTION OUTPUT ;
    USE SIGNAL ;
    PORT
      LAYER M4 ;
        RECT  0 27.984 0.084 28.008 ;
    END
  END b[98]
  PIN b[99]
    DIRECTION OUTPUT ;
    USE SIGNAL ;
    PORT
      LAYER M4 ;
        RECT  0 28.08 0.084 28.104 ;
    END
  END b[99]
  PIN b[9]
    DIRECTION OUTPUT ;
    USE SIGNAL ;
    PORT
      LAYER M4 ;
        RECT  0 33.552 0.084 33.576 ;
    END
  END b[9]
  PIN ck
    DIRECTION INPUT ;
    USE SIGNAL ;
    PORT
      LAYER M3 ;
        RECT  15.372 51.803 15.39 51.84 ;
    END
  END ck
  PIN ck_s
    DIRECTION INPUT ;
    USE SIGNAL ;
    PORT
      LAYER M3 ;
        RECT  15.444 51.803 15.462 51.84 ;
    END
  END ck_s
  PIN en
    DIRECTION INPUT ;
    USE SIGNAL ;
    PORT
      LAYER M3 ;
        RECT  15.516 51.803 15.534 51.84 ;
    END
  END en
  PIN fault
    DIRECTION OUTPUT ;
    USE SIGNAL ;
    PORT
      LAYER M3 ;
        RECT  15.588 51.803 15.606 51.84 ;
    END
  END fault
  PIN k0
    DIRECTION INPUT ;
    USE SIGNAL ;
    PORT
      LAYER M3 ;
        RECT  15.66 51.803 15.678 51.84 ;
    END
  END k0
  PIN k1
    DIRECTION INPUT ;
    USE SIGNAL ;
    PORT
      LAYER M3 ;
        RECT  15.732 51.803 15.75 51.84 ;
    END
  END k1
  PIN k2
    DIRECTION INPUT ;
    USE SIGNAL ;
    PORT
      LAYER M3 ;
        RECT  15.804 51.803 15.822 51.84 ;
    END
  END k2
  PIN k3
    DIRECTION INPUT ;
    USE SIGNAL ;
    PORT
      LAYER M3 ;
        RECT  15.876 51.803 15.894 51.84 ;
    END
  END k3
  PIN rs
    DIRECTION INPUT ;
    USE SIGNAL ;
    PORT
      LAYER M3 ;
        RECT  15.948 51.803 15.966 51.84 ;
    END
  END rs
  PIN tie_hi
    DIRECTION OUTPUT ;
    USE SIGNAL ;
    PORT
      LAYER M3 ;
        RECT  16.02 51.803 16.038 51.84 ;
    END
  END tie_hi
  PIN tie_lo
    DIRECTION OUTPUT ;
    USE SIGNAL ;
    PORT
      LAYER M3 ;
        RECT  16.092 51.803 16.11 51.84 ;
    END
  END tie_lo
  PIN VSS
    DIRECTION INOUT ;
    USE GROUND ;
    PORT
      LAYER M5 ;
        RECT  48.3 2.137 48.42 49.703 ;
        RECT  45.6 2.137 45.72 49.703 ;
        RECT  42.9 2.137 43.02 49.703 ;
        RECT  40.2 2.137 40.32 49.703 ;
        RECT  37.5 2.137 37.62 49.703 ;
        RECT  34.8 2.137 34.92 49.703 ;
        RECT  32.1 2.137 32.22 49.703 ;
        RECT  29.4 2.137 29.52 49.703 ;
        RECT  26.7 2.137 26.82 49.703 ;
        RECT  24 2.137 24.12 49.703 ;
        RECT  21.3 2.137 21.42 49.703 ;
        RECT  18.6 2.137 18.72 49.703 ;
        RECT  15.9 2.137 16.02 49.703 ;
        RECT  13.2 2.137 13.32 49.703 ;
        RECT  10.5 2.137 10.62 49.703 ;
        RECT  7.8 2.137 7.92 49.703 ;
        RECT  5.1 2.137 5.22 49.703 ;
        RECT  2.4 2.137 2.52 49.703 ;
    END
  END VSS
  PIN VDD
    DIRECTION INOUT ;
    USE POWER ;
    PORT
      LAYER M5 ;
        RECT  48.492 2.151 48.612 49.689 ;
        RECT  45.792 2.151 45.912 49.689 ;
        RECT  43.092 2.151 43.212 49.689 ;
        RECT  40.392 2.151 40.512 49.689 ;
        RECT  37.692 2.151 37.812 49.689 ;
        RECT  34.992 2.151 35.112 49.689 ;
        RECT  32.292 2.151 32.412 49.689 ;
        RECT  29.592 2.151 29.712 49.689 ;
        RECT  26.892 2.151 27.012 49.689 ;
        RECT  24.192 2.151 24.312 49.689 ;
        RECT  21.492 2.151 21.612 49.689 ;
        RECT  18.792 2.151 18.912 49.689 ;
        RECT  16.092 2.151 16.212 49.689 ;
        RECT  13.392 2.151 13.512 49.689 ;
        RECT  10.692 2.151 10.812 49.689 ;
        RECT  7.992 2.151 8.112 49.689 ;
        RECT  5.292 2.151 5.412 49.689 ;
        RECT  2.592 2.151 2.712 49.689 ;
    END
  END VDD
  # OT_OBS_CLOSED layer=M5 d_um=1.536 added=247
  OBS
    LAYER RVTN ;
     RECT  2.16 2.16 49.68 2.295 ;
     RECT  2.16 2.565 49.68 2.835 ;
     RECT  2.16 3.105 49.68 3.375 ;
     RECT  2.16 3.645 49.68 3.915 ;
     RECT  2.16 4.185 49.68 4.455 ;
     RECT  2.16 4.725 49.68 4.995 ;
     RECT  2.16 5.265 49.68 5.535 ;
     RECT  2.16 5.805 49.68 6.075 ;
     RECT  2.16 6.345 49.68 6.615 ;
     RECT  2.16 6.885 49.68 7.155 ;
     RECT  2.16 7.425 49.68 7.695 ;
     RECT  2.16 7.965 49.68 8.235 ;
     RECT  2.16 8.505 49.68 8.775 ;
     RECT  2.16 9.045 49.68 9.315 ;
     RECT  2.16 9.585 49.68 9.855 ;
     RECT  2.16 10.125 49.68 10.395 ;
     RECT  2.16 10.665 49.68 10.935 ;
     RECT  2.16 11.205 49.68 11.475 ;
     RECT  2.16 11.745 49.68 12.015 ;
     RECT  2.16 12.285 49.68 12.555 ;
     RECT  2.16 12.825 49.68 13.095 ;
     RECT  2.16 13.365 49.68 13.635 ;
     RECT  2.16 13.905 49.68 14.175 ;
     RECT  2.16 14.445 49.68 14.715 ;
     RECT  2.16 14.985 49.68 15.255 ;
     RECT  2.16 15.525 49.68 15.795 ;
     RECT  2.16 16.065 49.68 16.335 ;
     RECT  2.16 16.605 49.68 16.875 ;
     RECT  2.16 17.145 49.68 17.415 ;
     RECT  2.16 17.685 49.68 17.955 ;
     RECT  2.16 18.225 49.68 18.495 ;
     RECT  2.16 18.765 49.68 19.035 ;
     RECT  2.16 19.305 49.68 19.575 ;
     RECT  2.16 19.845 49.68 20.115 ;
     RECT  2.16 20.385 49.68 20.655 ;
     RECT  2.16 20.925 49.68 21.195 ;
     RECT  2.16 21.465 49.68 21.735 ;
     RECT  2.16 22.005 49.68 22.275 ;
     RECT  2.16 22.545 49.68 22.815 ;
     RECT  2.16 23.085 49.68 23.355 ;
     RECT  2.16 23.625 49.68 23.895 ;
     RECT  2.16 24.165 49.68 24.435 ;
     RECT  2.16 24.705 49.68 24.975 ;
     RECT  2.16 25.245 49.68 25.515 ;
     RECT  2.16 25.785 49.68 26.055 ;
     RECT  2.16 26.325 49.68 26.595 ;
     RECT  2.16 26.865 49.68 27.135 ;
     RECT  2.16 27.405 49.68 27.675 ;
     RECT  2.16 27.945 49.68 28.215 ;
     RECT  2.16 28.485 49.68 28.755 ;
     RECT  2.16 29.025 49.68 29.295 ;
     RECT  2.16 29.565 49.68 29.835 ;
     RECT  2.16 30.105 49.68 30.375 ;
     RECT  2.16 30.645 49.68 30.915 ;
     RECT  2.16 31.185 49.68 31.455 ;
     RECT  2.16 31.725 49.68 31.995 ;
     RECT  2.16 32.265 49.68 32.535 ;
     RECT  2.16 32.805 49.68 33.075 ;
     RECT  2.16 33.345 49.68 33.615 ;
     RECT  2.16 33.885 49.68 34.155 ;
     RECT  2.16 34.425 49.68 34.695 ;
     RECT  2.16 34.965 49.68 35.235 ;
     RECT  2.16 35.505 49.68 35.775 ;
     RECT  2.16 36.045 49.68 36.315 ;
     RECT  2.16 36.585 49.68 36.855 ;
     RECT  2.16 37.125 49.68 37.395 ;
     RECT  2.16 37.665 49.68 37.935 ;
     RECT  2.16 38.205 49.68 38.475 ;
     RECT  2.16 38.745 49.68 39.015 ;
     RECT  2.16 39.285 49.68 39.555 ;
     RECT  2.16 39.825 49.68 40.095 ;
     RECT  2.16 40.365 49.68 40.635 ;
     RECT  2.16 40.905 49.68 41.175 ;
     RECT  2.16 41.445 49.68 41.715 ;
     RECT  2.16 41.985 49.68 42.255 ;
     RECT  2.16 42.525 49.68 42.795 ;
     RECT  2.16 43.065 49.68 43.335 ;
     RECT  2.16 43.605 49.68 43.875 ;
     RECT  2.16 44.145 49.68 44.415 ;
     RECT  2.16 44.685 49.68 44.955 ;
     RECT  2.16 45.225 49.68 45.495 ;
     RECT  2.16 45.765 49.68 46.035 ;
     RECT  2.16 46.305 49.68 46.575 ;
     RECT  2.16 46.845 49.68 47.115 ;
     RECT  2.16 47.385 49.68 47.655 ;
     RECT  2.16 47.925 49.68 48.195 ;
     RECT  2.16 48.465 49.68 48.735 ;
     RECT  2.16 49.005 49.68 49.275 ;
     RECT  2.16 49.545 49.68 49.68 ;
    LAYER RVTP ;
     RECT  2.16 2.295 49.68 2.565 ;
     RECT  2.16 2.835 49.68 3.105 ;
     RECT  2.16 3.375 49.68 3.645 ;
     RECT  2.16 3.915 49.68 4.185 ;
     RECT  2.16 4.455 49.68 4.725 ;
     RECT  2.16 4.995 49.68 5.265 ;
     RECT  2.16 5.535 49.68 5.805 ;
     RECT  2.16 6.075 49.68 6.345 ;
     RECT  2.16 6.615 49.68 6.885 ;
     RECT  2.16 7.155 49.68 7.425 ;
     RECT  2.16 7.695 49.68 7.965 ;
     RECT  2.16 8.235 49.68 8.505 ;
     RECT  2.16 8.775 49.68 9.045 ;
     RECT  2.16 9.315 49.68 9.585 ;
     RECT  2.16 9.855 49.68 10.125 ;
     RECT  2.16 10.395 49.68 10.665 ;
     RECT  2.16 10.935 49.68 11.205 ;
     RECT  2.16 11.475 49.68 11.745 ;
     RECT  2.16 12.015 49.68 12.285 ;
     RECT  2.16 12.555 49.68 12.825 ;
     RECT  2.16 13.095 49.68 13.365 ;
     RECT  2.16 13.635 49.68 13.905 ;
     RECT  2.16 14.175 49.68 14.445 ;
     RECT  2.16 14.715 49.68 14.985 ;
     RECT  2.16 15.255 49.68 15.525 ;
     RECT  2.16 15.795 49.68 16.065 ;
     RECT  2.16 16.335 49.68 16.605 ;
     RECT  2.16 16.875 49.68 17.145 ;
     RECT  2.16 17.415 49.68 17.685 ;
     RECT  2.16 17.955 49.68 18.225 ;
     RECT  2.16 18.495 49.68 18.765 ;
     RECT  2.16 19.035 49.68 19.305 ;
     RECT  2.16 19.575 49.68 19.845 ;
     RECT  2.16 20.115 49.68 20.385 ;
     RECT  2.16 20.655 49.68 20.925 ;
     RECT  2.16 21.195 49.68 21.465 ;
     RECT  2.16 21.735 49.68 22.005 ;
     RECT  2.16 22.275 49.68 22.545 ;
     RECT  2.16 22.815 49.68 23.085 ;
     RECT  2.16 23.355 49.68 23.625 ;
     RECT  2.16 23.895 49.68 24.165 ;
     RECT  2.16 24.435 49.68 24.705 ;
     RECT  2.16 24.975 49.68 25.245 ;
     RECT  2.16 25.515 49.68 25.785 ;
     RECT  2.16 26.055 49.68 26.325 ;
     RECT  2.16 26.595 49.68 26.865 ;
     RECT  2.16 27.135 49.68 27.405 ;
     RECT  2.16 27.675 49.68 27.945 ;
     RECT  2.16 28.215 49.68 28.485 ;
     RECT  2.16 28.755 49.68 29.025 ;
     RECT  2.16 29.295 49.68 29.565 ;
     RECT  2.16 29.835 49.68 30.105 ;
     RECT  2.16 30.375 49.68 30.645 ;
     RECT  2.16 30.915 49.68 31.185 ;
     RECT  2.16 31.455 49.68 31.725 ;
     RECT  2.16 31.995 49.68 32.265 ;
     RECT  2.16 32.535 49.68 32.805 ;
     RECT  2.16 33.075 49.68 33.345 ;
     RECT  2.16 33.615 49.68 33.885 ;
     RECT  2.16 34.155 49.68 34.425 ;
     RECT  2.16 34.695 49.68 34.965 ;
     RECT  2.16 35.235 49.68 35.505 ;
     RECT  2.16 35.775 49.68 36.045 ;
     RECT  2.16 36.315 49.68 36.585 ;
     RECT  2.16 36.855 49.68 37.125 ;
     RECT  2.16 37.395 49.68 37.665 ;
     RECT  2.16 37.935 49.68 38.205 ;
     RECT  2.16 38.475 49.68 38.745 ;
     RECT  2.16 39.015 49.68 39.285 ;
     RECT  2.16 39.555 49.68 39.825 ;
     RECT  2.16 40.095 49.68 40.365 ;
     RECT  2.16 40.635 49.68 40.905 ;
     RECT  2.16 41.175 49.68 41.445 ;
     RECT  2.16 41.715 49.68 41.985 ;
     RECT  2.16 42.255 49.68 42.525 ;
     RECT  2.16 42.795 49.68 43.065 ;
     RECT  2.16 43.335 49.68 43.605 ;
     RECT  2.16 43.875 49.68 44.145 ;
     RECT  2.16 44.415 49.68 44.685 ;
     RECT  2.16 44.955 49.68 45.225 ;
     RECT  2.16 45.495 49.68 45.765 ;
     RECT  2.16 46.035 49.68 46.305 ;
     RECT  2.16 46.575 49.68 46.845 ;
     RECT  2.16 47.115 49.68 47.385 ;
     RECT  2.16 47.655 49.68 47.925 ;
     RECT  2.16 48.195 49.68 48.465 ;
     RECT  2.16 48.735 49.68 49.005 ;
     RECT  2.16 49.275 49.68 49.545 ;
    LAYER M1 ;
     RECT  2.16 2.151 49.68 49.689 ;
    LAYER M2 ;
     RECT  0.103 12.636 0.139 12.654 ;
     RECT  0.103 9.9 0.203 9.918 ;
     RECT  0.103 10.836 0.203 10.854 ;
     RECT  0.103 30.231 0.203 31.446 ;
     RECT  0.103 27.756 0.211 28.278 ;
     RECT  0.139 12.6 0.239 12.654 ;
     RECT  0.103 34.902 0.347 34.92 ;
     RECT  0.211 27.756 0.499 28.854 ;
     RECT  0.499 27.216 0.535 28.854 ;
     RECT  0.239 12.636 1.147 12.654 ;
     RECT  1.147 12.636 1.175 12.924 ;
     RECT  0.535 7.776 2.16 7.794 ;
     RECT  0.535 11.214 2.16 11.232 ;
     RECT  1.175 12.906 2.16 12.924 ;
     RECT  0.535 27.216 2.16 29.052 ;
     RECT  0.535 33.048 2.16 33.066 ;
     RECT  15.511 50.751 15.871 50.769 ;
     RECT  2.16 2.151 16.015 49.689 ;
     RECT  15.871 50.751 16.259 50.814 ;
     RECT  16.015 2.151 16.367 49.77 ;
     RECT  16.259 50.751 16.727 50.769 ;
     RECT  15.943 51.786 19.823 51.804 ;
     RECT  16.367 2.151 49.68 49.689 ;
     RECT  49.68 45.54 49.883 45.558 ;
     RECT  49.68 44.154 49.919 44.748 ;
     RECT  49.68 13.446 50.171 15.624 ;
     RECT  49.919 44.73 50.459 44.748 ;
     RECT  49.68 33.588 50.675 33.606 ;
     RECT  49.68 30.726 50.711 32.49 ;
     RECT  50.171 15.336 50.747 15.624 ;
     RECT  49.68 24.246 50.747 27.36 ;
     RECT  50.711 30.726 50.747 32.094 ;
     RECT  49.68 11.52 50.783 12.384 ;
     RECT  50.747 25.596 50.783 27.36 ;
     RECT  50.747 30.726 50.783 31.95 ;
     RECT  50.747 24.246 50.819 24.804 ;
     RECT  50.171 13.446 50.855 14.004 ;
     RECT  50.783 12.366 50.891 12.384 ;
     RECT  50.783 30.726 51.151 31.554 ;
     RECT  49.68 8.316 51.359 9.684 ;
     RECT  50.783 25.596 51.359 25.884 ;
     RECT  50.819 24.246 51.395 24.498 ;
     RECT  51.151 30.546 51.395 31.554 ;
     RECT  51.359 25.596 51.431 25.614 ;
     RECT  50.783 11.52 51.467 11.538 ;
     RECT  51.395 24.246 51.503 24.264 ;
     RECT  50.855 13.572 51.539 14.004 ;
     RECT  51.395 30.726 51.547 31.554 ;
     RECT  51.511 35.046 51.547 35.064 ;
     RECT  49.68 22.086 51.575 22.104 ;
     RECT  50.783 26.802 51.575 27.36 ;
     RECT  51.359 8.316 51.611 9.612 ;
     RECT  49.68 19.386 51.611 20.214 ;
     RECT  49.68 21.006 51.647 21.024 ;
     RECT  51.575 26.874 51.647 27.36 ;
     RECT  51.547 30.726 51.647 31.824 ;
     RECT  51.611 8.316 51.683 9.072 ;
     RECT  51.611 19.386 51.683 19.944 ;
     RECT  51.547 34.974 51.683 35.064 ;
     RECT  49.68 7.236 51.719 7.524 ;
     RECT  51.511 10.836 51.719 10.926 ;
     RECT  51.539 13.716 51.719 14.004 ;
     RECT  51.647 26.91 51.719 27.36 ;
     RECT  51.647 30.726 51.719 31.554 ;
     RECT  51.619 32.814 51.719 32.832 ;
     RECT  51.683 34.974 51.719 34.992 ;
     RECT  50.747 15.606 51.727 15.624 ;
     RECT  51.691 22.824 51.727 22.842 ;
     RECT  51.683 8.316 51.755 8.334 ;
     RECT  51.719 13.716 51.755 13.968 ;
     RECT  51.727 15.192 51.755 15.624 ;
     RECT  51.683 19.386 51.755 19.404 ;
     RECT  51.719 27.036 51.755 27.36 ;
     RECT  51.719 30.726 51.755 30.744 ;
     RECT  51.719 31.536 51.755 31.554 ;
     RECT  49.68 36.63 51.755 36.918 ;
     RECT  51.719 7.236 51.791 7.488 ;
     RECT  51.719 10.908 51.791 10.926 ;
     RECT  51.755 27.036 51.791 27.054 ;
     RECT  51.791 7.47 51.827 7.488 ;
     RECT  51.755 15.192 51.827 15.21 ;
     RECT  49.68 17.766 51.827 17.784 ;
     RECT  51.727 22.824 51.827 22.914 ;
     RECT  51.727 29.88 51.827 29.898 ;
     RECT  51.727 33.012 51.827 33.03 ;
     RECT  51.755 36.9 51.827 36.918 ;
    LAYER M3 ;
     RECT  34.815 2.143 34.905 2.191 ;
     RECT  37.515 2.143 37.605 2.191 ;
     RECT  45.615 2.143 45.705 2.191 ;
     RECT  36.54 2.191 37.605 2.203 ;
     RECT  17.856 2.191 17.874 2.227 ;
     RECT  45 2.191 45.705 2.227 ;
     RECT  45 2.227 46.062 2.251 ;
     RECT  5.115 2.143 5.205 2.263 ;
     RECT  5.976 2.203 5.994 2.263 ;
     RECT  7.056 2.203 7.074 2.263 ;
     RECT  7.815 2.143 7.905 2.263 ;
     RECT  12.456 2.227 12.474 2.263 ;
     RECT  15.915 2.143 16.005 2.263 ;
     RECT  17.352 2.227 17.874 2.263 ;
     RECT  19.944 2.191 20.574 2.263 ;
     RECT  21.315 2.143 21.405 2.263 ;
     RECT  24.015 2.143 24.105 2.263 ;
     RECT  34.596 2.191 34.905 2.263 ;
     RECT  39.312 2.191 39.33 2.263 ;
     RECT  44.28 2.251 46.062 2.263 ;
     RECT  9.36 2.251 9.378 2.299 ;
     RECT  10.515 2.143 10.605 2.299 ;
     RECT  18.615 2.143 18.705 2.299 ;
     RECT  34.092 2.263 34.905 2.299 ;
     RECT  15.804 2.263 16.005 2.335 ;
     RECT  30.42 2.263 30.69 2.335 ;
     RECT  32.115 2.143 32.205 2.335 ;
     RECT  5.976 2.263 6.282 2.371 ;
     RECT  7.056 2.263 7.905 2.371 ;
     RECT  9.36 2.299 10.605 2.371 ;
     RECT  11.808 2.263 12.474 2.371 ;
     RECT  13.215 2.143 13.305 2.371 ;
     RECT  17.208 2.263 17.874 2.371 ;
     RECT  18.615 2.299 18.954 2.371 ;
     RECT  19.944 2.263 21.405 2.371 ;
     RECT  23.472 2.263 24.105 2.371 ;
     RECT  25.452 2.227 25.47 2.371 ;
     RECT  28.152 2.263 28.314 2.371 ;
     RECT  30.42 2.335 30.834 2.371 ;
     RECT  31.824 2.335 32.205 2.371 ;
     RECT  34.092 2.299 35.154 2.371 ;
     RECT  36.504 2.203 37.605 2.371 ;
     RECT  39.276 2.263 39.33 2.371 ;
     RECT  40.215 2.143 40.305 2.371 ;
     RECT  44.28 2.263 46.386 2.371 ;
     RECT  2.415 2.143 2.505 2.413 ;
     RECT  4.176 2.263 5.205 2.413 ;
     RECT  5.976 2.371 7.905 2.413 ;
     RECT  9.36 2.371 10.674 2.413 ;
     RECT  15.732 2.335 16.005 2.413 ;
     RECT  19.944 2.371 21.474 2.413 ;
     RECT  23.364 2.371 24.105 2.413 ;
     RECT  26.715 2.143 26.805 2.413 ;
     RECT  29.415 2.143 29.505 2.413 ;
     RECT  30.42 2.371 32.205 2.413 ;
     RECT  39.276 2.371 40.305 2.413 ;
     RECT  42.915 2.143 43.005 2.413 ;
     RECT  48.315 2.143 48.405 2.413 ;
     RECT  2.415 2.413 2.697 2.461 ;
     RECT  4.176 2.413 8.097 2.461 ;
     RECT  26.715 2.413 26.997 2.461 ;
     RECT  34.092 2.371 35.406 2.461 ;
     RECT  39.276 2.413 40.497 2.461 ;
     RECT  48.315 2.413 48.597 2.461 ;
     RECT  19.944 2.413 21.597 2.497 ;
     RECT  39.276 2.461 40.77 2.497 ;
     RECT  9.36 2.413 10.797 2.533 ;
     RECT  11.52 2.371 13.698 2.533 ;
     RECT  17.208 2.371 18.954 2.533 ;
     RECT  19.944 2.497 21.906 2.533 ;
     RECT  25.416 2.371 25.47 2.533 ;
     RECT  42.915 2.413 43.197 2.533 ;
     RECT  17.208 2.533 21.906 2.569 ;
     RECT  25.092 2.533 25.47 2.569 ;
     RECT  39.276 2.497 40.842 2.569 ;
     RECT  44.136 2.371 46.854 2.587 ;
     RECT  47.664 2.461 48.597 2.587 ;
     RECT  3.924 2.461 8.097 2.605 ;
     RECT  9.324 2.533 10.797 2.605 ;
     RECT  11.52 2.533 14.562 2.605 ;
     RECT  15.732 2.413 16.197 2.605 ;
     RECT  25.092 2.569 25.722 2.605 ;
     RECT  33.84 2.461 35.406 2.605 ;
     RECT  39.132 2.569 40.842 2.605 ;
     RECT  42.264 2.533 43.197 2.605 ;
     RECT  44.136 2.587 48.597 2.605 ;
     RECT  29.415 2.413 29.697 2.632 ;
     RECT  30.42 2.413 32.397 2.632 ;
     RECT  17.1 2.569 21.906 2.641 ;
     RECT  25.092 2.605 25.794 2.641 ;
     RECT  26.715 2.461 27.162 2.641 ;
     RECT  28.008 2.371 28.314 2.641 ;
     RECT  29.415 2.632 32.397 2.641 ;
     RECT  39.132 2.605 40.914 2.641 ;
     RECT  42.012 2.605 43.197 2.641 ;
     RECT  44.136 2.605 48.654 2.641 ;
     RECT  23.364 2.413 24.297 2.731 ;
     RECT  25.092 2.641 32.397 2.731 ;
     RECT  33.732 2.605 35.406 2.731 ;
     RECT  41.796 2.641 43.197 2.731 ;
     RECT  44.136 2.641 49.554 2.731 ;
     RECT  2.415 2.461 3.006 2.767 ;
     RECT  3.924 2.605 16.197 2.767 ;
     RECT  17.1 2.641 22.446 2.767 ;
     RECT  41.796 2.731 49.554 2.795 ;
     RECT  33.156 2.731 35.406 2.803 ;
     RECT  39.132 2.641 41.058 2.803 ;
     RECT  41.796 2.795 48.87 2.803 ;
     RECT  2.415 2.767 16.254 2.839 ;
     RECT  17.028 2.767 22.446 2.839 ;
     RECT  23.364 2.731 32.397 2.839 ;
     RECT  2.415 2.839 32.397 2.875 ;
     RECT  33.156 2.803 35.55 2.875 ;
     RECT  36.504 2.371 38.25 2.875 ;
     RECT  2.415 2.875 38.25 3.029 ;
     RECT  20.412 3.029 38.25 3.037 ;
     RECT  39.132 2.803 48.87 3.037 ;
     RECT  20.412 3.037 48.87 3.065 ;
     RECT  20.448 3.065 28.674 3.335 ;
     RECT  20.448 3.335 28.602 3.479 ;
     RECT  29.415 3.065 48.87 3.479 ;
     RECT  42.912 3.479 48.87 3.721 ;
     RECT  2.415 3.029 19.638 3.811 ;
     RECT  20.448 3.479 28.494 3.811 ;
     RECT  2.415 3.811 28.494 3.875 ;
     RECT  9.576 3.875 28.494 3.965 ;
     RECT  9.612 3.965 28.494 3.983 ;
     RECT  2.415 3.875 8.802 4.109 ;
     RECT  42.912 3.721 49.338 4.189 ;
     RECT  9.648 3.983 28.494 4.261 ;
     RECT  29.415 3.479 42.174 4.261 ;
     RECT  42.912 4.189 49.482 4.261 ;
     RECT  9.648 4.261 49.482 4.379 ;
     RECT  9.648 4.379 49.338 4.415 ;
     RECT  9.648 4.415 14.922 4.891 ;
     RECT  2.415 4.109 8.694 5.035 ;
     RECT  9.468 4.891 14.922 5.035 ;
     RECT  15.732 4.415 48.942 5.063 ;
     RECT  15.732 5.063 28.602 5.333 ;
     RECT  2.415 5.035 14.922 5.341 ;
     RECT  15.732 5.333 28.134 5.341 ;
     RECT  29.415 5.063 48.942 5.341 ;
     RECT  2.415 5.341 28.134 6.151 ;
     RECT  29.415 5.341 49.194 6.269 ;
     RECT  2.415 6.151 28.386 6.655 ;
     RECT  2.415 6.655 28.422 6.781 ;
     RECT  2.376 6.781 28.422 6.845 ;
     RECT  2.415 6.845 28.422 6.859 ;
     RECT  29.415 6.269 49.086 6.859 ;
     RECT  2.415 6.859 49.086 7.321 ;
     RECT  51.768 7.231 51.786 7.465 ;
     RECT  51.768 7.465 51.822 7.501 ;
     RECT  2.415 7.321 49.194 7.727 ;
     RECT  28.98 7.727 49.194 7.771 ;
     RECT  28.98 7.771 49.302 7.961 ;
     RECT  2.415 7.727 28.242 7.963 ;
     RECT  2.376 7.963 28.242 8.159 ;
     RECT  51.696 7.501 51.822 8.401 ;
     RECT  3.42 8.159 28.242 8.581 ;
     RECT  28.98 7.961 48.87 8.581 ;
     RECT  3.42 8.581 48.87 8.815 ;
     RECT  51.624 8.401 51.822 8.827 ;
     RECT  3.42 8.815 49.374 9.005 ;
     RECT  22.392 9.005 49.374 9.041 ;
     RECT  51.48 8.827 51.822 9.067 ;
     RECT  2.415 8.159 2.697 9.319 ;
     RECT  3.42 9.005 21.597 9.319 ;
     RECT  0.54 7.771 0.558 9.547 ;
     RECT  51.408 9.067 51.822 9.661 ;
     RECT  22.392 9.041 48.87 9.779 ;
     RECT  0.108 9.547 0.558 9.932 ;
     RECT  22.716 9.779 48.87 10.021 ;
     RECT  2.415 9.319 21.597 10.085 ;
     RECT  22.716 10.021 48.978 10.165 ;
     RECT  22.716 10.165 49.554 10.205 ;
     RECT  0.144 9.932 0.558 10.253 ;
     RECT  4.428 10.085 21.597 10.291 ;
     RECT  2.415 10.085 3.654 10.411 ;
     RECT  22.788 10.205 49.554 10.589 ;
     RECT  0.144 10.253 0.342 10.699 ;
     RECT  4.428 10.291 21.69 10.699 ;
     RECT  4.428 10.699 21.726 10.741 ;
     RECT  0.108 10.699 0.342 10.859 ;
     RECT  4.428 10.741 21.798 10.975 ;
     RECT  2.304 10.411 3.654 11.101 ;
     RECT  4.428 10.975 21.906 11.101 ;
     RECT  0.144 10.859 0.342 11.209 ;
     RECT  2.304 11.101 21.906 11.281 ;
     RECT  22.788 10.589 49.302 11.281 ;
     RECT  2.304 11.281 49.302 11.309 ;
     RECT  0.144 11.209 0.558 11.501 ;
     RECT  2.415 11.309 49.302 11.551 ;
     RECT  2.415 11.551 49.482 11.669 ;
     RECT  2.415 11.669 49.338 11.813 ;
     RECT  50.436 11.713 50.454 11.821 ;
     RECT  51.336 9.661 51.822 11.821 ;
     RECT  1.152 11.755 1.17 11.851 ;
     RECT  9.396 11.813 49.338 11.939 ;
     RECT  1.152 11.851 1.278 12.139 ;
     RECT  1.152 12.139 1.386 12.269 ;
     RECT  9.396 11.939 36.126 12.353 ;
     RECT  0.108 11.755 0.126 12.427 ;
     RECT  2.415 11.813 8.586 12.427 ;
     RECT  2.304 12.427 8.586 12.551 ;
     RECT  0.108 12.427 0.342 12.557 ;
     RECT  37.224 11.939 49.338 12.557 ;
     RECT  6.66 12.551 8.586 12.559 ;
     RECT  9.396 12.353 35.982 12.559 ;
     RECT  0.108 12.557 0.234 12.623 ;
     RECT  0.108 12.623 0.162 12.653 ;
     RECT  0.108 12.653 0.126 12.659 ;
     RECT  6.66 12.559 35.982 12.749 ;
     RECT  2.415 12.551 5.922 12.797 ;
     RECT  2.415 12.797 3.582 12.821 ;
     RECT  4.464 12.797 5.922 12.821 ;
     RECT  2.415 12.821 3.546 12.857 ;
     RECT  2.415 12.857 2.862 12.893 ;
     RECT  5.076 12.821 5.922 12.893 ;
     RECT  1.152 12.269 1.17 12.929 ;
     RECT  37.224 12.557 41.634 13.019 ;
     RECT  42.48 12.557 49.338 13.019 ;
     RECT  9.288 12.749 35.982 13.055 ;
     RECT  37.224 13.019 41.598 13.099 ;
     RECT  36.972 13.099 41.598 13.135 ;
     RECT  9.288 13.055 27.81 13.289 ;
     RECT  28.548 13.055 35.982 13.297 ;
     RECT  36.792 13.135 41.598 13.297 ;
     RECT  28.548 13.297 41.598 13.361 ;
     RECT  5.115 12.893 5.922 13.405 ;
     RECT  6.66 12.749 8.55 13.405 ;
     RECT  22.32 13.289 27.81 13.559 ;
     RECT  5.115 13.405 8.55 13.639 ;
     RECT  9.288 13.289 21.597 13.639 ;
     RECT  2.415 12.893 2.697 13.675 ;
     RECT  3.528 13.639 3.546 13.675 ;
     RECT  22.572 13.559 27.81 13.801 ;
     RECT  28.548 13.361 30.942 13.801 ;
     RECT  31.716 13.361 41.598 13.801 ;
     RECT  31.716 13.801 41.634 13.819 ;
     RECT  31.716 13.819 41.778 13.829 ;
     RECT  2.415 13.675 3.798 13.837 ;
     RECT  5.115 13.639 21.597 13.837 ;
     RECT  34.524 13.829 41.778 13.837 ;
     RECT  42.696 13.019 49.338 13.837 ;
     RECT  34.524 13.837 49.338 13.865 ;
     RECT  34.74 13.865 49.338 14.099 ;
     RECT  34.776 14.099 49.338 14.171 ;
     RECT  2.415 13.837 21.597 14.341 ;
     RECT  41.76 14.171 49.338 14.369 ;
     RECT  2.415 14.341 21.654 14.405 ;
     RECT  2.415 14.405 11.358 14.449 ;
     RECT  41.796 14.369 49.338 14.449 ;
     RECT  50.436 11.821 51.822 14.477 ;
     RECT  22.572 13.801 30.942 14.485 ;
     RECT  31.716 13.829 33.786 14.485 ;
     RECT  41.796 14.449 49.626 14.485 ;
     RECT  50.436 14.477 50.454 14.485 ;
     RECT  12.096 14.405 21.654 14.521 ;
     RECT  12.096 14.521 21.726 14.611 ;
     RECT  22.572 14.485 33.786 14.611 ;
     RECT  41.796 14.485 50.454 14.669 ;
     RECT  12.096 14.611 34.002 14.711 ;
     RECT  31.068 14.711 34.002 14.791 ;
     RECT  31.068 14.791 34.038 14.813 ;
     RECT  2.34 14.449 11.358 14.819 ;
     RECT  22.644 14.711 30.294 14.819 ;
     RECT  22.644 14.819 30.258 14.909 ;
     RECT  2.412 14.819 11.358 14.945 ;
     RECT  50.076 14.669 50.454 14.981 ;
     RECT  31.248 14.813 34.038 15.061 ;
     RECT  34.776 14.171 40.986 15.061 ;
     RECT  51.372 14.477 51.822 15.149 ;
     RECT  51.48 15.149 51.822 15.215 ;
     RECT  50.436 14.981 50.454 15.331 ;
     RECT  31.248 15.061 40.986 15.403 ;
     RECT  41.796 14.669 49.338 15.403 ;
     RECT  51.48 15.215 51.75 15.437 ;
     RECT  12.096 14.711 21.906 15.457 ;
     RECT  22.932 14.909 30.258 15.533 ;
     RECT  31.248 15.403 49.338 15.533 ;
     RECT  2.415 14.945 11.358 15.542 ;
     RECT  12.096 15.457 21.942 15.542 ;
     RECT  31.248 15.533 35.838 15.601 ;
     RECT  50.436 15.331 50.742 15.629 ;
     RECT  51.516 15.437 51.75 15.629 ;
     RECT  51.516 15.629 51.534 15.725 ;
     RECT  23.184 15.533 30.258 15.787 ;
     RECT  23.184 15.787 30.294 15.871 ;
     RECT  31.068 15.601 35.838 15.871 ;
     RECT  50.436 15.629 50.454 16.013 ;
     RECT  2.415 15.542 21.942 16.027 ;
     RECT  23.184 15.871 35.838 16.339 ;
     RECT  2.415 16.027 22.266 16.375 ;
     RECT  23.184 16.339 35.982 16.375 ;
     RECT  36.828 15.533 49.338 16.375 ;
     RECT  2.415 16.375 49.338 16.529 ;
     RECT  2.415 16.529 25.902 17.105 ;
     RECT  26.715 16.529 49.338 17.339 ;
     RECT  12.96 17.105 25.902 17.491 ;
     RECT  26.715 17.339 29.898 17.491 ;
     RECT  30.852 17.339 49.338 17.581 ;
     RECT  30.852 17.581 49.374 18.121 ;
     RECT  12.96 17.491 29.898 18.157 ;
     RECT  30.78 18.121 49.374 18.157 ;
     RECT  2.415 17.105 12.078 18.229 ;
     RECT  12.96 18.157 49.374 18.229 ;
     RECT  2.415 18.229 49.374 18.455 ;
     RECT  2.415 18.455 49.194 18.689 ;
     RECT  2.415 18.689 49.086 18.725 ;
     RECT  2.415 18.725 48.834 18.797 ;
     RECT  2.415 18.797 11.898 19.229 ;
     RECT  51.804 17.761 51.822 19.381 ;
     RECT  8.928 19.229 11.898 19.579 ;
     RECT  13.068 18.797 48.834 19.579 ;
     RECT  8.928 19.579 48.834 19.651 ;
     RECT  2.415 19.229 8.19 19.769 ;
     RECT  8.928 19.651 49.23 19.805 ;
     RECT  8.928 19.805 49.158 19.811 ;
     RECT  9.54 19.811 49.158 19.877 ;
     RECT  51.732 19.381 51.822 19.921 ;
     RECT  51.66 19.921 51.822 20.059 ;
     RECT  9.54 19.877 49.014 20.075 ;
     RECT  2.415 19.769 8.154 20.587 ;
     RECT  9.54 20.075 48.942 20.587 ;
     RECT  2.376 20.587 8.154 20.623 ;
     RECT  9 20.587 48.942 20.623 ;
     RECT  2.376 20.623 48.942 20.965 ;
     RECT  2.376 20.965 49.194 21.155 ;
     RECT  2.376 21.155 49.05 21.659 ;
     RECT  2.376 21.659 11.898 21.731 ;
     RECT  12.636 21.659 49.05 22.001 ;
     RECT  12.636 22.001 48.978 22.073 ;
     RECT  12.636 22.073 20.07 22.441 ;
     RECT  20.844 22.073 48.978 22.505 ;
     RECT  2.376 21.731 11.754 22.513 ;
     RECT  12.564 22.441 20.07 22.513 ;
     RECT  20.844 22.505 25.614 22.577 ;
     RECT  26.388 22.505 48.978 22.613 ;
     RECT  26.424 22.613 48.978 22.649 ;
     RECT  2.376 22.513 20.07 22.795 ;
     RECT  20.844 22.577 25.506 22.795 ;
     RECT  2.376 22.795 25.506 23.153 ;
     RECT  2.415 23.153 25.506 23.423 ;
     RECT  12.816 23.423 25.506 23.665 ;
     RECT  26.532 22.649 48.978 23.665 ;
     RECT  12.816 23.665 48.978 23.701 ;
     RECT  12.816 23.701 49.338 23.741 ;
     RECT  12.816 23.741 27.738 23.855 ;
     RECT  28.548 23.741 49.338 23.855 ;
     RECT  28.98 23.855 49.086 23.927 ;
     RECT  51.516 20.059 51.822 24.241 ;
     RECT  12.996 23.855 27.738 24.475 ;
     RECT  51.48 24.241 51.822 24.475 ;
     RECT  28.98 23.927 49.014 24.503 ;
     RECT  2.415 23.423 11.97 24.511 ;
     RECT  12.996 24.475 28.242 24.637 ;
     RECT  28.98 24.503 41.346 24.637 ;
     RECT  51.372 24.475 51.822 24.781 ;
     RECT  2.415 24.511 12.042 25.051 ;
     RECT  12.996 24.637 41.346 25.051 ;
     RECT  2.415 25.051 41.346 25.169 ;
     RECT  25.848 25.169 41.346 25.321 ;
     RECT  42.084 24.503 49.014 25.321 ;
     RECT  25.848 25.321 49.014 25.475 ;
     RECT  50.796 24.781 51.822 25.519 ;
     RECT  31.824 25.475 49.014 25.555 ;
     RECT  25.848 25.475 31.086 25.709 ;
     RECT  31.824 25.555 49.482 25.709 ;
     RECT  25.848 25.709 30.87 25.745 ;
     RECT  26.208 25.745 30.87 25.853 ;
     RECT  50.724 25.519 51.822 26.023 ;
     RECT  31.824 25.709 49.194 26.221 ;
     RECT  2.415 25.169 25.074 26.251 ;
     RECT  50.22 26.023 51.822 26.365 ;
     RECT  31.788 26.221 49.194 26.381 ;
     RECT  31.788 26.381 41.166 26.527 ;
     RECT  41.904 26.381 49.194 26.669 ;
     RECT  26.208 25.853 30.618 26.671 ;
     RECT  31.392 26.527 41.166 26.671 ;
     RECT  50.184 26.365 51.822 26.672 ;
     RECT  2.415 26.251 25.47 26.683 ;
     RECT  26.208 26.671 41.166 26.683 ;
     RECT  50.184 26.672 50.238 26.765 ;
     RECT  42.336 26.669 49.194 26.827 ;
     RECT  2.415 26.683 41.166 26.861 ;
     RECT  42.336 26.827 49.806 26.933 ;
     RECT  49.788 26.933 49.806 27.203 ;
     RECT  25.308 26.861 41.166 27.365 ;
     RECT  36.54 27.365 41.166 27.373 ;
     RECT  42.336 26.933 48.978 27.643 ;
     RECT  25.308 27.365 35.802 27.68 ;
     RECT  0.504 27.211 0.522 27.691 ;
     RECT  0.144 27.691 0.522 27.751 ;
     RECT  36.54 27.373 41.382 27.751 ;
     RECT  42.156 27.643 48.978 27.751 ;
     RECT  0.108 27.751 0.522 27.913 ;
     RECT  36.54 27.751 49.05 27.913 ;
     RECT  2.415 26.861 24.57 28.075 ;
     RECT  2.304 28.075 24.57 28.139 ;
     RECT  26.352 27.68 35.802 28.139 ;
     RECT  2.415 28.139 24.57 28.255 ;
     RECT  25.308 27.68 25.578 28.255 ;
     RECT  36.54 27.913 49.554 28.409 ;
     RECT  36.54 28.409 49.158 28.445 ;
     RECT  0.108 27.913 0.558 28.781 ;
     RECT  2.415 28.255 25.578 28.795 ;
     RECT  26.352 28.139 35.55 28.795 ;
     RECT  2.415 28.795 35.55 28.859 ;
     RECT  0.216 28.781 0.558 28.877 ;
     RECT  22.32 28.859 35.55 29.101 ;
     RECT  36.54 28.445 48.978 29.101 ;
     RECT  22.32 29.101 48.978 29.129 ;
     RECT  0.36 28.877 0.558 29.165 ;
     RECT  25.452 29.129 48.978 29.219 ;
     RECT  25.704 29.219 48.978 29.335 ;
     RECT  0.36 29.165 0.486 29.453 ;
     RECT  25.704 29.335 49.554 29.489 ;
     RECT  35.964 29.489 49.554 29.525 ;
     RECT  2.415 28.859 21.597 29.641 ;
     RECT  22.32 29.129 24.678 29.645 ;
     RECT  2.304 29.641 21.597 29.767 ;
     RECT  22.32 29.645 24.642 29.767 ;
     RECT  51.12 26.672 51.822 29.903 ;
     RECT  51.12 29.903 51.75 29.933 ;
     RECT  2.304 29.767 24.642 30.029 ;
     RECT  36.072 29.525 49.554 30.029 ;
     RECT  0.144 29.851 0.198 30.187 ;
     RECT  25.704 29.489 35.19 30.299 ;
     RECT  31.248 30.299 35.19 30.331 ;
     RECT  36.072 30.029 48.978 30.331 ;
     RECT  25.704 30.299 30.33 30.451 ;
     RECT  51.12 29.933 51.498 30.721 ;
     RECT  4.14 30.029 24.642 30.839 ;
     RECT  25.632 30.451 30.33 30.847 ;
     RECT  4.14 30.839 22.626 30.875 ;
     RECT  50.724 30.721 51.75 30.893 ;
     RECT  23.4 30.839 24.642 30.919 ;
     RECT  25.56 30.847 30.33 30.919 ;
     RECT  31.248 30.331 48.978 30.955 ;
     RECT  31.248 30.955 49.158 31.019 ;
     RECT  35.928 31.019 49.158 31.081 ;
     RECT  23.4 30.919 30.33 31.189 ;
     RECT  31.248 31.019 35.097 31.189 ;
     RECT  2.304 30.029 3.402 31.225 ;
     RECT  4.14 30.875 22.338 31.225 ;
     RECT  2.304 31.225 22.338 31.243 ;
     RECT  35.928 31.081 49.23 31.451 ;
     RECT  0.108 30.187 0.198 31.517 ;
     RECT  2.268 31.243 22.338 31.559 ;
     RECT  51.552 30.893 51.75 31.559 ;
     RECT  0.108 31.517 0.126 31.565 ;
     RECT  2.304 31.559 22.338 31.621 ;
     RECT  35.928 31.451 49.014 31.649 ;
     RECT  2.304 31.621 22.482 31.801 ;
     RECT  23.4 31.189 35.097 31.801 ;
     RECT  51.552 31.559 51.678 31.829 ;
     RECT  2.304 31.801 35.097 31.853 ;
     RECT  51.624 31.829 51.678 31.853 ;
     RECT  6.876 31.853 35.097 31.891 ;
     RECT  35.928 31.649 38.178 31.891 ;
     RECT  2.304 31.853 6.102 31.919 ;
     RECT  2.304 31.919 2.697 31.949 ;
     RECT  50.724 30.893 50.778 32.141 ;
     RECT  38.916 31.649 49.014 32.203 ;
     RECT  38.916 32.203 49.734 32.233 ;
     RECT  50.724 32.141 50.742 32.233 ;
     RECT  38.916 32.233 50.742 32.369 ;
     RECT  50.184 32.369 50.742 32.429 ;
     RECT  50.688 32.429 50.742 32.525 ;
     RECT  38.916 32.369 49.086 32.603 ;
     RECT  50.724 32.525 50.742 32.621 ;
     RECT  3.924 31.919 4.266 32.701 ;
     RECT  0.108 32.587 0.126 32.717 ;
     RECT  6.876 31.891 38.178 32.737 ;
     RECT  38.916 32.603 48.942 32.737 ;
     RECT  5.115 31.919 5.994 32.773 ;
     RECT  51.66 31.853 51.678 32.779 ;
     RECT  3.852 32.701 4.266 32.809 ;
     RECT  5.115 32.773 6.066 32.809 ;
     RECT  51.66 32.779 51.714 32.809 ;
     RECT  2.415 31.949 2.697 32.827 ;
     RECT  3.456 32.809 6.066 32.827 ;
     RECT  6.876 32.737 48.942 32.827 ;
     RECT  51.624 32.809 51.714 32.861 ;
     RECT  2.415 32.827 48.942 32.872 ;
     RECT  51.66 32.861 51.714 32.971 ;
     RECT  51.66 32.971 51.75 33.007 ;
     RECT  0.54 33.043 0.558 33.101 ;
     RECT  2.304 32.872 48.942 33.269 ;
     RECT  49.896 33.355 49.914 33.451 ;
     RECT  50.652 33.259 50.67 33.451 ;
     RECT  4.392 33.269 48.942 33.547 ;
     RECT  49.896 33.451 50.67 33.547 ;
     RECT  4.392 33.547 50.67 33.611 ;
     RECT  4.392 33.611 50.454 34.079 ;
     RECT  4.392 34.079 30.798 34.109 ;
     RECT  0.144 33.739 0.162 34.315 ;
     RECT  2.304 33.269 3.618 34.411 ;
     RECT  4.392 34.109 5.886 34.411 ;
     RECT  51.66 33.007 51.822 34.411 ;
     RECT  51.372 34.411 51.822 34.637 ;
     RECT  51.48 34.637 51.822 34.781 ;
     RECT  0.144 34.315 0.342 34.888 ;
     RECT  0.108 34.888 0.342 34.925 ;
     RECT  2.304 34.411 5.886 34.987 ;
     RECT  6.696 34.109 30.798 34.987 ;
     RECT  32.004 34.079 50.454 34.987 ;
     RECT  0.144 34.925 0.342 35.021 ;
     RECT  51.516 34.781 51.822 35.213 ;
     RECT  51.588 35.213 51.822 35.261 ;
     RECT  51.696 35.261 51.822 35.309 ;
     RECT  0.144 35.021 0.234 35.549 ;
     RECT  2.304 34.987 50.454 35.699 ;
     RECT  0.216 35.549 0.234 35.741 ;
     RECT  3.42 35.699 5.886 36.041 ;
     RECT  6.66 35.699 50.454 36.041 ;
     RECT  2.304 35.699 2.697 36.149 ;
     RECT  6.84 36.041 50.454 36.509 ;
     RECT  51.732 35.309 51.822 36.653 ;
     RECT  3.852 36.041 5.886 36.661 ;
     RECT  2.415 36.149 2.697 36.787 ;
     RECT  3.852 36.661 6.066 36.787 ;
     RECT  2.415 36.787 6.066 36.811 ;
     RECT  6.84 36.509 33.642 36.811 ;
     RECT  2.415 36.811 33.642 36.815 ;
     RECT  31.572 36.815 33.642 36.845 ;
     RECT  2.415 36.815 30.546 36.923 ;
     RECT  51.804 36.653 51.822 36.923 ;
     RECT  23.076 36.923 30.546 37.355 ;
     RECT  31.788 36.845 33.642 37.429 ;
     RECT  34.452 36.509 50.454 37.429 ;
     RECT  23.148 37.355 30.546 37.472 ;
     RECT  31.788 37.429 50.454 37.597 ;
     RECT  24.015 37.472 30.546 37.903 ;
     RECT  31.32 37.597 50.454 37.903 ;
     RECT  24.015 37.903 50.454 38.677 ;
     RECT  23.148 37.472 23.166 38.713 ;
     RECT  24.012 38.677 50.454 38.713 ;
     RECT  2.415 36.923 22.338 38.785 ;
     RECT  23.148 38.713 50.454 38.785 ;
     RECT  2.415 38.785 50.454 39.281 ;
     RECT  2.415 39.281 33.714 39.389 ;
     RECT  2.415 39.389 29.79 39.749 ;
     RECT  30.672 39.389 33.714 40.171 ;
     RECT  34.452 39.281 50.454 40.171 ;
     RECT  2.415 39.749 23.166 40.199 ;
     RECT  30.672 40.171 50.454 40.253 ;
     RECT  23.94 39.749 29.79 40.261 ;
     RECT  30.672 40.253 40.95 40.261 ;
     RECT  4.824 40.199 23.166 40.711 ;
     RECT  23.94 40.261 40.95 40.711 ;
     RECT  2.415 40.199 4.086 40.981 ;
     RECT  4.824 40.711 40.95 40.981 ;
     RECT  2.415 40.981 40.95 41.099 ;
     RECT  41.796 40.253 50.454 41.243 ;
     RECT  2.415 41.099 40.77 41.989 ;
     RECT  2.376 41.989 40.77 42.025 ;
     RECT  2.376 42.025 40.986 42.151 ;
     RECT  42.084 41.243 50.454 42.151 ;
     RECT  2.376 42.151 50.454 43.295 ;
     RECT  2.415 43.295 50.454 43.871 ;
     RECT  30.6 43.871 50.454 44.105 ;
     RECT  30.6 44.105 49.086 44.141 ;
     RECT  49.86 44.105 50.454 44.753 ;
     RECT  40.104 44.141 49.086 44.959 ;
     RECT  2.415 43.871 29.862 44.995 ;
     RECT  30.636 44.141 39.15 44.995 ;
     RECT  39.96 44.959 49.086 44.995 ;
     RECT  49.86 44.753 49.878 44.995 ;
     RECT  39.96 44.995 49.878 45.301 ;
     RECT  39.924 45.301 49.878 45.391 ;
     RECT  2.34 44.995 39.15 45.463 ;
     RECT  39.888 45.391 49.878 45.463 ;
     RECT  2.34 45.463 49.878 45.563 ;
     RECT  2.34 45.563 49.23 45.995 ;
     RECT  2.34 45.995 49.086 46.031 ;
     RECT  2.376 46.031 49.086 47.213 ;
     RECT  12.564 47.213 49.086 47.219 ;
     RECT  12.564 47.219 49.014 47.345 ;
     RECT  2.376 47.213 11.574 47.381 ;
     RECT  12.6 47.345 49.014 47.885 ;
     RECT  34.56 47.885 49.014 47.921 ;
     RECT  34.596 47.921 49.014 48.191 ;
     RECT  12.6 47.885 33.678 48.361 ;
     RECT  2.415 47.381 11.574 48.425 ;
     RECT  34.596 48.191 48.942 48.425 ;
     RECT  12.564 48.361 33.678 48.775 ;
     RECT  34.596 48.425 35.73 48.775 ;
     RECT  12.564 48.775 35.73 48.929 ;
     RECT  2.415 48.425 10.797 48.955 ;
     RECT  36.468 48.425 48.942 48.989 ;
     RECT  11.556 48.425 11.574 49.009 ;
     RECT  2.376 48.955 10.797 49.199 ;
     RECT  25.452 48.929 35.73 49.199 ;
     RECT  3.852 49.199 4.086 49.235 ;
     RECT  12.564 48.929 17.658 49.235 ;
     RECT  25.668 49.199 35.73 49.235 ;
     RECT  38.592 48.989 48.942 49.235 ;
     RECT  18.396 48.929 24.498 49.271 ;
     RECT  6.984 49.199 10.797 49.279 ;
     RECT  11.556 49.009 11.682 49.279 ;
     RECT  27.864 49.235 35.73 49.307 ;
     RECT  39.6 49.235 48.942 49.307 ;
     RECT  6.984 49.279 11.682 49.315 ;
     RECT  12.564 49.235 16.83 49.315 ;
     RECT  42.228 49.307 48.942 49.315 ;
     RECT  4.86 49.199 6.246 49.343 ;
     RECT  6.984 49.315 16.83 49.343 ;
     RECT  42.228 49.315 49.122 49.343 ;
     RECT  28.332 49.307 35.73 49.351 ;
     RECT  36.468 48.989 37.797 49.351 ;
     RECT  28.332 49.351 37.797 49.379 ;
     RECT  18.396 49.271 24.297 49.427 ;
     RECT  31.14 49.379 37.797 49.427 ;
     RECT  42.228 49.343 45.897 49.427 ;
     RECT  2.376 49.199 3.006 49.469 ;
     RECT  3.924 49.235 4.086 49.469 ;
     RECT  4.86 49.343 5.814 49.469 ;
     RECT  6.984 49.343 8.946 49.469 ;
     RECT  9.72 49.343 16.83 49.469 ;
     RECT  18.396 49.427 24.105 49.469 ;
     RECT  25.668 49.235 27.09 49.469 ;
     RECT  31.14 49.427 37.605 49.469 ;
     RECT  38.628 49.235 38.826 49.469 ;
     RECT  39.6 49.307 41.49 49.469 ;
     RECT  42.228 49.427 45.705 49.469 ;
     RECT  46.764 49.343 49.122 49.469 ;
     RECT  25.812 49.469 25.83 49.475 ;
     RECT  3.924 49.469 3.942 49.505 ;
     RECT  5.004 49.469 5.706 49.505 ;
     RECT  7.452 49.469 8.802 49.505 ;
     RECT  17.604 49.235 17.658 49.505 ;
     RECT  18.468 49.469 21.405 49.505 ;
     RECT  23.076 49.469 24.105 49.505 ;
     RECT  26.64 49.469 26.805 49.505 ;
     RECT  28.332 49.379 30.33 49.505 ;
     RECT  31.14 49.469 32.205 49.505 ;
     RECT  34.776 49.469 34.905 49.505 ;
     RECT  36.396 49.469 37.605 49.505 ;
     RECT  39.6 49.469 40.305 49.505 ;
     RECT  41.364 49.469 41.49 49.505 ;
     RECT  42.915 49.469 44.37 49.505 ;
     RECT  45.18 49.469 45.705 49.505 ;
     RECT  47.376 49.469 48.405 49.505 ;
     RECT  12.384 49.469 13.305 49.517 ;
     RECT  14.112 49.469 14.13 49.517 ;
     RECT  18.468 49.505 19.026 49.517 ;
     RECT  7.452 49.505 8.154 49.541 ;
     RECT  12.384 49.517 12.402 49.541 ;
     RECT  18.615 49.517 19.026 49.541 ;
     RECT  20.88 49.505 21.405 49.541 ;
     RECT  26.676 49.505 26.805 49.541 ;
     RECT  28.764 49.505 30.33 49.541 ;
     RECT  33.084 49.469 33.462 49.541 ;
     RECT  36.468 49.505 36.486 49.541 ;
     RECT  38.772 49.469 38.79 49.541 ;
     RECT  47.376 49.505 47.466 49.541 ;
     RECT  5.115 49.505 5.706 49.577 ;
     RECT  7.815 49.541 8.154 49.577 ;
     RECT  10.515 49.469 11.574 49.577 ;
     RECT  17.604 49.505 17.622 49.577 ;
     RECT  23.076 49.505 23.094 49.577 ;
     RECT  28.764 49.541 30.042 49.577 ;
     RECT  31.212 49.505 31.23 49.577 ;
     RECT  32.076 49.505 32.205 49.577 ;
     RECT  41.472 49.505 41.49 49.577 ;
     RECT  43.848 49.505 44.37 49.577 ;
     RECT  47.448 49.541 47.466 49.577 ;
     RECT  33.408 49.541 33.426 49.613 ;
     RECT  43.848 49.577 43.866 49.649 ;
     RECT  2.415 49.469 2.505 49.697 ;
     RECT  5.115 49.577 5.205 49.697 ;
     RECT  7.815 49.577 7.905 49.697 ;
     RECT  10.515 49.577 10.605 49.697 ;
     RECT  13.215 49.517 13.305 49.697 ;
     RECT  18.615 49.541 18.705 49.697 ;
     RECT  21.315 49.541 21.405 49.697 ;
     RECT  24.015 49.505 24.105 49.697 ;
     RECT  26.715 49.541 26.805 49.697 ;
     RECT  29.415 49.577 29.505 49.697 ;
     RECT  32.115 49.577 32.205 49.697 ;
     RECT  34.815 49.505 34.905 49.697 ;
     RECT  37.515 49.505 37.605 49.697 ;
     RECT  40.215 49.505 40.305 49.697 ;
     RECT  42.915 49.505 43.005 49.697 ;
     RECT  45.615 49.505 45.705 49.697 ;
     RECT  48.315 49.505 48.405 49.697 ;
     RECT  15.588 49.469 16.722 50.731 ;
     RECT  15.372 50.731 16.722 50.774 ;
     RECT  15.372 50.774 16.254 50.819 ;
     RECT  19.8 49.505 19.818 51.809 ;
     RECT  15.372 50.819 16.11 51.803 ;
     RECT  15.39 51.803 15.444 51.821 ;
     RECT  15.462 51.803 15.516 51.821 ;
     RECT  15.534 51.803 15.588 51.821 ;
     RECT  15.606 51.803 15.66 51.821 ;
     RECT  15.678 51.803 15.732 51.821 ;
     RECT  15.75 51.803 15.804 51.821 ;
     RECT  15.822 51.803 15.876 51.821 ;
     RECT  15.894 51.803 15.948 51.821 ;
     RECT  15.966 51.803 16.02 51.821 ;
     RECT  16.038 51.803 16.092 51.821 ;
    LAYER M4 ;
     RECT  0.084 9.648 0.097 9.672 ;
     RECT  0.06 9.672 0.097 9.744 ;
     RECT  0.084 9.744 0.097 9.768 ;
     RECT  0.06 9.768 0.097 9.84 ;
     RECT  0.084 9.84 0.097 9.864 ;
     RECT  0.06 9.864 0.097 9.936 ;
     RECT  0.084 9.936 0.097 9.96 ;
     RECT  0.06 9.96 0.097 10.032 ;
     RECT  0.084 10.032 0.097 10.056 ;
     RECT  0.06 10.056 0.097 10.128 ;
     RECT  0.084 10.128 0.097 10.152 ;
     RECT  0.06 10.152 0.097 10.224 ;
     RECT  0.084 10.224 0.097 10.248 ;
     RECT  0.06 10.248 0.097 10.32 ;
     RECT  0.084 10.32 0.097 10.344 ;
     RECT  0.06 10.344 0.097 10.416 ;
     RECT  0.084 10.416 0.097 10.44 ;
     RECT  0.06 10.44 0.097 10.512 ;
     RECT  0.084 10.512 0.097 10.536 ;
     RECT  0.06 10.536 0.097 10.608 ;
     RECT  0.084 10.608 0.097 10.632 ;
     RECT  0.06 10.632 0.097 10.704 ;
     RECT  0.084 10.704 0.097 10.728 ;
     RECT  0.06 10.728 0.097 10.8 ;
     RECT  0.084 10.8 0.097 10.824 ;
     RECT  0.06 10.824 0.097 10.896 ;
     RECT  0.084 10.896 0.097 10.92 ;
     RECT  0.06 10.92 0.097 10.992 ;
     RECT  0.084 10.992 0.097 11.016 ;
     RECT  0.06 11.016 0.097 11.088 ;
     RECT  0.084 11.088 0.097 11.112 ;
     RECT  0.06 11.112 0.097 11.184 ;
     RECT  0.084 11.184 0.097 11.208 ;
     RECT  0.06 11.208 0.097 11.28 ;
     RECT  0.084 11.28 0.097 11.304 ;
     RECT  0.06 11.304 0.097 11.376 ;
     RECT  0.084 11.376 0.097 11.4 ;
     RECT  0.06 11.4 0.097 11.472 ;
     RECT  0.084 11.472 0.097 11.496 ;
     RECT  0.06 11.496 0.097 11.568 ;
     RECT  0.084 11.568 0.097 11.592 ;
     RECT  0.06 11.592 0.097 11.664 ;
     RECT  0.084 11.664 0.097 11.688 ;
     RECT  0.06 11.688 0.097 11.76 ;
     RECT  0.084 11.76 0.097 11.784 ;
     RECT  0.06 11.784 0.097 11.856 ;
     RECT  0.084 11.856 0.097 11.88 ;
     RECT  0.06 11.88 0.097 11.952 ;
     RECT  0.084 11.952 0.097 11.976 ;
     RECT  0.06 11.976 0.097 12.048 ;
     RECT  0.084 12.048 0.097 12.072 ;
     RECT  0.06 12.072 0.097 12.144 ;
     RECT  0.084 12.144 0.097 12.168 ;
     RECT  0.06 12.168 0.097 12.24 ;
     RECT  0.084 12.24 0.097 12.264 ;
     RECT  0.06 12.264 0.097 12.336 ;
     RECT  0.084 12.336 0.097 12.36 ;
     RECT  0.06 12.36 0.097 12.432 ;
     RECT  0.084 12.432 0.097 12.456 ;
     RECT  0.06 12.456 0.097 12.528 ;
     RECT  0.084 12.528 0.097 12.552 ;
     RECT  0.06 12.552 0.097 12.624 ;
     RECT  0.084 12.624 0.097 12.648 ;
     RECT  0.097 9.552 0.133 12.648 ;
     RECT  0.084 27.792 0.133 27.816 ;
     RECT  0.06 27.816 0.133 27.888 ;
     RECT  0.084 27.888 0.133 27.912 ;
     RECT  0.06 27.912 0.133 27.984 ;
     RECT  0.084 27.984 0.133 28.008 ;
     RECT  0.06 28.008 0.133 28.08 ;
     RECT  0.084 28.08 0.133 28.104 ;
     RECT  0.06 28.104 0.133 28.176 ;
     RECT  0.084 28.176 0.133 28.2 ;
     RECT  0.06 28.2 0.133 28.272 ;
     RECT  0.084 28.272 0.133 28.296 ;
     RECT  0.06 28.296 0.133 28.368 ;
     RECT  0.084 28.368 0.133 28.392 ;
     RECT  0.06 28.392 0.133 28.464 ;
     RECT  0.084 28.464 0.133 28.488 ;
     RECT  0.06 28.488 0.133 28.56 ;
     RECT  0.084 28.56 0.133 28.584 ;
     RECT  0.06 28.584 0.133 28.656 ;
     RECT  0.084 28.656 0.133 28.68 ;
     RECT  0.06 28.68 0.133 28.752 ;
     RECT  0.084 28.752 0.133 28.776 ;
     RECT  0.06 28.776 0.133 28.848 ;
     RECT  0.084 28.848 0.133 28.872 ;
     RECT  0.06 28.872 0.133 28.944 ;
     RECT  0.084 28.944 0.133 28.968 ;
     RECT  0.06 28.968 0.133 29.04 ;
     RECT  0.084 29.04 0.133 29.064 ;
     RECT  0.06 29.064 0.133 29.136 ;
     RECT  0.084 29.136 0.133 29.16 ;
     RECT  0.06 29.16 0.133 29.232 ;
     RECT  0.084 29.232 0.133 29.256 ;
     RECT  0.06 29.256 0.133 29.328 ;
     RECT  0.084 29.328 0.133 29.352 ;
     RECT  0.06 29.352 0.133 29.424 ;
     RECT  0.084 29.424 0.133 29.448 ;
     RECT  0.06 29.448 0.133 29.52 ;
     RECT  0.084 29.52 0.133 29.544 ;
     RECT  0.06 29.544 0.133 29.616 ;
     RECT  0.084 29.616 0.133 29.64 ;
     RECT  0.06 29.64 0.133 29.712 ;
     RECT  0.084 29.712 0.133 29.736 ;
     RECT  0.06 29.736 0.133 29.808 ;
     RECT  0.084 29.808 0.133 29.832 ;
     RECT  0.06 29.832 0.133 29.904 ;
     RECT  0.084 29.904 0.133 29.928 ;
     RECT  0.06 29.928 0.133 30 ;
     RECT  0.084 30 0.133 30.024 ;
     RECT  0.06 30.024 0.133 30.096 ;
     RECT  0.084 30.096 0.133 30.12 ;
     RECT  0.06 30.12 0.133 30.192 ;
     RECT  0.084 30.192 0.133 30.216 ;
     RECT  0.06 30.216 0.133 30.288 ;
     RECT  0.084 30.288 0.133 30.312 ;
     RECT  0.06 30.312 0.133 30.384 ;
     RECT  0.084 30.384 0.133 30.408 ;
     RECT  0.06 30.408 0.133 30.48 ;
     RECT  0.084 30.48 0.133 30.504 ;
     RECT  0.06 30.504 0.133 30.576 ;
     RECT  0.084 30.576 0.133 30.6 ;
     RECT  0.06 30.6 0.133 30.672 ;
     RECT  0.084 30.672 0.133 30.696 ;
     RECT  0.06 30.696 0.133 30.768 ;
     RECT  0.084 30.768 0.133 30.792 ;
     RECT  0.06 30.792 0.133 30.864 ;
     RECT  0.084 30.864 0.133 30.888 ;
     RECT  0.06 30.888 0.133 30.96 ;
     RECT  0.084 30.96 0.133 30.984 ;
     RECT  0.06 30.984 0.133 31.056 ;
     RECT  0.084 31.056 0.133 31.08 ;
     RECT  0.06 31.08 0.133 31.152 ;
     RECT  0.084 31.152 0.133 31.176 ;
     RECT  0.06 31.176 0.133 31.248 ;
     RECT  0.084 31.248 0.133 31.272 ;
     RECT  0.06 31.272 0.133 31.344 ;
     RECT  0.084 31.344 0.133 31.368 ;
     RECT  0.06 31.368 0.133 31.44 ;
     RECT  0.084 31.44 0.133 31.464 ;
     RECT  0.06 31.464 0.133 31.536 ;
     RECT  0.084 31.536 0.133 31.56 ;
     RECT  0.06 31.56 0.133 31.632 ;
     RECT  0.084 31.632 0.133 31.656 ;
     RECT  0.06 31.656 0.133 31.728 ;
     RECT  0.084 31.728 0.133 31.752 ;
     RECT  0.06 31.752 0.133 31.824 ;
     RECT  0.084 31.824 0.133 31.848 ;
     RECT  0.06 31.848 0.133 32.688 ;
     RECT  0.084 32.688 0.133 32.712 ;
     RECT  0.06 32.712 0.133 32.784 ;
     RECT  0.084 32.784 0.133 32.808 ;
     RECT  0.06 32.808 0.133 32.88 ;
     RECT  0.084 32.88 0.133 32.904 ;
     RECT  0.06 32.904 0.133 32.976 ;
     RECT  0.084 32.976 0.133 33 ;
     RECT  0.06 33 0.133 33.072 ;
     RECT  0.084 33.072 0.133 33.096 ;
     RECT  0.06 33.096 0.133 33.168 ;
     RECT  0.084 33.168 0.133 33.192 ;
     RECT  0.06 33.192 0.133 33.264 ;
     RECT  0.084 33.264 0.133 33.288 ;
     RECT  0.06 33.288 0.133 33.36 ;
     RECT  0.084 33.36 0.133 33.384 ;
     RECT  0.06 33.384 0.133 33.456 ;
     RECT  0.084 33.456 0.133 33.48 ;
     RECT  0.06 33.48 0.133 33.552 ;
     RECT  0.084 33.552 0.133 33.576 ;
     RECT  0.06 33.576 0.133 33.648 ;
     RECT  0.084 33.648 0.133 33.672 ;
     RECT  0.06 33.672 0.133 33.744 ;
     RECT  0.084 33.744 0.133 33.768 ;
     RECT  0.06 33.768 0.133 33.84 ;
     RECT  0.084 33.84 0.133 33.864 ;
     RECT  0.06 33.864 0.133 33.936 ;
     RECT  0.084 33.936 0.133 33.96 ;
     RECT  0.06 33.96 0.133 34.032 ;
     RECT  0.084 34.032 0.133 34.056 ;
     RECT  0.06 34.056 0.133 34.128 ;
     RECT  0.084 34.128 0.133 34.152 ;
     RECT  0.06 34.152 0.133 34.224 ;
     RECT  0.084 34.224 0.133 34.248 ;
     RECT  0.06 34.248 0.133 34.32 ;
     RECT  0.084 34.32 0.133 34.344 ;
     RECT  0.06 34.344 0.133 34.416 ;
     RECT  0.084 34.416 0.133 34.44 ;
     RECT  0.06 34.44 0.133 34.512 ;
     RECT  0.084 34.512 0.133 34.536 ;
     RECT  0.06 34.536 0.133 34.608 ;
     RECT  0.084 34.608 0.133 34.632 ;
     RECT  0.06 34.632 0.133 34.704 ;
     RECT  0.084 34.704 0.133 34.728 ;
     RECT  0.06 34.728 0.133 34.8 ;
     RECT  0.084 34.8 0.133 34.824 ;
     RECT  0.06 34.824 0.133 34.896 ;
     RECT  0.084 34.896 0.133 34.92 ;
     RECT  0.06 34.92 0.133 34.992 ;
     RECT  0.084 34.992 0.133 35.016 ;
     RECT  0.06 35.016 0.133 35.088 ;
     RECT  0.084 35.088 0.133 35.112 ;
     RECT  0.06 35.112 0.133 35.184 ;
     RECT  0.084 35.184 0.133 35.208 ;
     RECT  0.06 35.208 0.133 35.28 ;
     RECT  0.084 35.28 0.133 35.304 ;
     RECT  0.06 35.304 0.133 35.376 ;
     RECT  0.084 35.376 0.133 35.4 ;
     RECT  0.06 35.4 0.133 35.472 ;
     RECT  0.084 35.472 0.133 35.496 ;
     RECT  0.06 35.496 0.133 35.568 ;
     RECT  0.084 35.568 0.133 35.592 ;
     RECT  0.06 35.592 0.133 35.664 ;
     RECT  0.084 35.664 0.133 35.688 ;
     RECT  0.133 27.696 0.205 35.688 ;
     RECT  2.365 6.816 2.408 6.84 ;
     RECT  2.365 7.968 2.408 7.992 ;
     RECT  0.133 9.552 2.408 12.792 ;
     RECT  0.205 27.696 2.408 35.736 ;
     RECT  2.365 48.96 2.408 48.984 ;
     RECT  2.408 2.148 2.512 49.692 ;
     RECT  2.512 2.418 2.704 49.422 ;
     RECT  2.704 7.872 2.819 7.992 ;
     RECT  2.704 24.528 2.837 35.736 ;
     RECT  2.704 48.432 2.915 48.984 ;
     RECT  2.704 39.888 2.981 39.912 ;
     RECT  2.704 19.92 3.017 20.568 ;
     RECT  2.704 21.888 3.053 23.352 ;
     RECT  2.704 46.272 3.053 46.344 ;
     RECT  2.704 40.944 3.089 42.504 ;
     RECT  3.089 41.904 3.233 42.504 ;
     RECT  3.017 20.544 3.341 20.568 ;
     RECT  2.837 25.008 3.377 35.736 ;
     RECT  3.233 41.952 3.413 42.504 ;
     RECT  3.377 27.696 3.449 35.736 ;
     RECT  2.704 37.584 3.485 37.992 ;
     RECT  2.704 18.528 3.557 18.552 ;
     RECT  3.449 27.696 3.665 35.64 ;
     RECT  2.704 9.552 3.701 12.792 ;
     RECT  3.701 9.648 3.769 12.792 ;
     RECT  2.819 7.872 3.805 7.896 ;
     RECT  2.704 6.816 3.925 6.84 ;
     RECT  3.805 7.872 3.925 8.472 ;
     RECT  2.704 44.064 3.949 44.088 ;
     RECT  2.915 48.96 3.953 48.984 ;
     RECT  3.949 44.064 3.973 44.424 ;
     RECT  3.053 21.888 3.985 22.776 ;
     RECT  3.665 27.84 3.989 35.64 ;
     RECT  3.973 43.728 4.06 44.424 ;
     RECT  2.704 4.512 4.117 4.536 ;
     RECT  2.704 5.664 4.117 5.688 ;
     RECT  4.117 4.512 4.345 5.688 ;
     RECT  3.925 6.816 4.345 8.472 ;
     RECT  2.704 16.416 4.345 16.536 ;
     RECT  3.985 21.408 4.381 22.776 ;
     RECT  3.485 37.968 4.453 37.992 ;
     RECT  3.053 46.32 4.453 46.344 ;
     RECT  4.381 20.736 4.481 22.776 ;
     RECT  4.453 37.632 4.489 37.992 ;
     RECT  4.481 20.496 4.501 22.776 ;
     RECT  3.913 23.952 4.561 23.976 ;
     RECT  3.377 25.008 4.561 26.664 ;
     RECT  4.489 37.488 4.7 37.992 ;
     RECT  2.704 47.424 4.705 47.448 ;
     RECT  4.06 44.4 4.741 44.424 ;
     RECT  4.453 45.6 4.741 46.344 ;
     RECT  4.345 16.032 4.813 16.536 ;
     RECT  4.093 19.344 4.885 19.368 ;
     RECT  4.741 44.4 4.957 46.344 ;
     RECT  4.705 47.376 4.957 47.448 ;
     RECT  3.769 9.648 4.981 13.704 ;
     RECT  4.273 14.688 4.981 14.712 ;
     RECT  4.885 18.192 4.981 19.368 ;
     RECT  4.501 20.496 4.981 22.92 ;
     RECT  2.704 2.784 5.108 3.288 ;
     RECT  4.345 4.512 5.108 8.472 ;
     RECT  4.981 9.648 5.108 15.048 ;
     RECT  4.813 16.032 5.108 17.064 ;
     RECT  4.981 18.192 5.108 22.92 ;
     RECT  4.561 23.952 5.108 26.664 ;
     RECT  3.989 27.888 5.108 35.64 ;
     RECT  4.7 37.488 5.108 38.376 ;
     RECT  3.413 42.192 5.108 42.504 ;
     RECT  4.957 44.4 5.108 47.448 ;
     RECT  4.993 49.008 5.108 49.032 ;
     RECT  5.108 2.148 5.212 49.692 ;
     RECT  5.212 2.208 5.404 49.422 ;
     RECT  5.404 21.216 5.465 21.528 ;
     RECT  5.404 18.192 5.555 19.8 ;
     RECT  5.404 27.984 5.555 36.84 ;
     RECT  5.404 44.688 5.555 49.032 ;
     RECT  5.555 18.72 5.616 19.8 ;
     RECT  5.404 42.192 5.651 42.216 ;
     RECT  5.555 44.688 5.651 48.936 ;
     RECT  5.404 6.672 5.689 12.6 ;
     RECT  5.651 45.696 5.717 48.936 ;
     RECT  5.404 39.504 5.747 40.584 ;
     RECT  5.689 6.672 5.753 7.992 ;
     RECT  5.404 5.088 5.825 5.304 ;
     RECT  5.825 5.088 5.861 5.208 ;
     RECT  5.717 46.704 5.969 48.936 ;
     RECT  5.717 45.696 6.221 45.72 ;
     RECT  5.969 48.432 6.257 48.936 ;
     RECT  5.753 6.768 6.293 7.992 ;
     RECT  5.969 46.704 6.329 47.448 ;
     RECT  5.747 39.504 6.365 39.528 ;
     RECT  5.861 5.088 6.371 5.112 ;
     RECT  5.404 37.872 6.397 38.184 ;
     RECT  5.404 13.68 6.429 13.704 ;
     RECT  5.616 19.776 6.541 19.8 ;
     RECT  5.555 36.816 6.541 36.84 ;
     RECT  6.397 37.872 6.541 38.952 ;
     RECT  5.465 21.504 6.613 21.528 ;
     RECT  5.616 18.72 6.649 18.744 ;
     RECT  6.541 19.776 6.649 20.424 ;
     RECT  5.651 44.688 6.721 44.712 ;
     RECT  5.555 27.984 6.761 35.544 ;
     RECT  6.761 28.176 6.901 35.544 ;
     RECT  6.257 48.432 6.973 48.456 ;
     RECT  6.721 44.688 7.081 45.576 ;
     RECT  6.613 40.896 7.117 40.92 ;
     RECT  6.293 6.816 7.153 7.992 ;
     RECT  5.689 8.976 7.153 12.6 ;
     RECT  5.404 16.032 7.225 16.968 ;
     RECT  7.225 16.032 7.297 17.64 ;
     RECT  6.649 18.72 7.297 20.424 ;
     RECT  6.757 13.872 7.333 13.944 ;
     RECT  6.937 14.928 7.333 14.952 ;
     RECT  7.117 40.752 7.333 40.92 ;
     RECT  6.329 46.704 7.333 46.728 ;
     RECT  6.973 48.384 7.333 48.456 ;
     RECT  7.333 5.472 7.369 5.496 ;
     RECT  7.297 16.032 7.369 20.424 ;
     RECT  6.613 21.504 7.369 22.2 ;
     RECT  7.333 40.128 7.381 40.92 ;
     RECT  6.541 36.816 7.405 38.952 ;
     RECT  7.381 40.128 7.405 41.64 ;
     RECT  7.369 5.232 7.441 5.496 ;
     RECT  5.404 23.904 7.441 24.696 ;
     RECT  5.404 25.968 7.441 26.808 ;
     RECT  7.369 16.032 7.513 22.2 ;
     RECT  6.901 28.176 7.621 35.736 ;
     RECT  7.405 36.816 7.621 41.64 ;
     RECT  5.404 2.208 7.669 2.232 ;
     RECT  5.404 3.984 7.669 4.008 ;
     RECT  7.333 46.704 7.669 48.456 ;
     RECT  7.669 2.208 7.808 4.008 ;
     RECT  7.441 5.184 7.808 5.496 ;
     RECT  7.153 6.816 7.808 12.6 ;
     RECT  7.333 13.872 7.808 14.952 ;
     RECT  7.513 16.032 7.808 22.776 ;
     RECT  7.441 23.904 7.808 26.808 ;
     RECT  7.621 28.176 7.808 41.64 ;
     RECT  7.081 43.824 7.808 45.576 ;
     RECT  7.669 46.704 7.808 49.032 ;
     RECT  7.808 2.148 7.912 49.692 ;
     RECT  7.912 2.418 8.104 49.422 ;
     RECT  8.104 33.264 8.165 38.232 ;
     RECT  8.104 39.792 8.243 42.504 ;
     RECT  8.104 43.92 8.243 45.576 ;
     RECT  8.104 3.312 8.273 3.624 ;
     RECT  8.104 6.432 8.273 8.472 ;
     RECT  8.104 24.144 8.309 31.896 ;
     RECT  8.309 24.144 8.453 25.032 ;
     RECT  8.104 47.616 8.489 47.64 ;
     RECT  8.104 16.896 8.531 17.64 ;
     RECT  8.104 20.88 8.597 22.776 ;
     RECT  8.104 13.92 8.633 14.712 ;
     RECT  8.309 26.064 8.669 31.896 ;
     RECT  8.669 26.064 8.675 29.88 ;
     RECT  8.675 26.112 8.705 29.88 ;
     RECT  8.705 26.256 8.777 29.88 ;
     RECT  8.669 30.912 8.777 31.896 ;
     RECT  8.165 33.264 8.777 38.184 ;
     RECT  8.243 39.792 8.813 42.456 ;
     RECT  8.777 30.96 8.993 31.896 ;
     RECT  8.104 5.184 9.097 5.4 ;
     RECT  8.273 6.432 9.097 7.416 ;
     RECT  9.097 5.184 9.169 7.416 ;
     RECT  8.273 8.4 9.173 8.424 ;
     RECT  8.104 9.792 9.205 12.552 ;
     RECT  9.205 9.504 9.277 12.552 ;
     RECT  8.597 20.88 9.277 20.952 ;
     RECT  8.243 44.688 9.277 45.576 ;
     RECT  8.531 16.896 9.313 17.496 ;
     RECT  9.097 47.04 9.313 47.112 ;
     RECT  9.277 9.504 9.349 12.6 ;
     RECT  8.633 13.92 9.349 14.616 ;
     RECT  9.308 2.256 9.395 2.28 ;
     RECT  8.273 3.312 9.425 3.432 ;
     RECT  9.277 43.872 9.445 45.576 ;
     RECT  9.313 46.896 9.445 47.112 ;
     RECT  8.813 39.984 9.457 42.456 ;
     RECT  9.445 43.872 9.457 47.112 ;
     RECT  8.104 19.776 9.529 19.8 ;
     RECT  9.277 20.784 9.529 20.952 ;
     RECT  9.425 3.408 9.565 3.432 ;
     RECT  9.313 16.56 9.596 17.496 ;
     RECT  9.529 19.776 9.596 20.952 ;
     RECT  9.596 15.648 9.665 17.496 ;
     RECT  8.597 22.08 9.709 22.776 ;
     RECT  8.453 24.144 9.709 24.888 ;
     RECT  8.777 26.256 9.709 29.256 ;
     RECT  8.777 33.264 9.925 34.152 ;
     RECT  9.457 49.296 9.961 49.32 ;
     RECT  9.169 5.136 10.177 7.416 ;
     RECT  8.993 30.96 10.213 31.368 ;
     RECT  9.349 9.504 10.357 14.616 ;
     RECT  9.665 15.648 10.357 18.264 ;
     RECT  9.925 33.072 10.393 34.152 ;
     RECT  8.777 35.28 10.393 38.184 ;
     RECT  9.565 3.408 10.508 3.96 ;
     RECT  10.177 5.136 10.508 7.656 ;
     RECT  10.357 9.504 10.508 18.264 ;
     RECT  9.596 19.44 10.508 20.952 ;
     RECT  9.709 22.08 10.508 29.256 ;
     RECT  10.213 30.96 10.508 32.04 ;
     RECT  10.393 33.072 10.508 38.184 ;
     RECT  9.457 39.984 10.508 47.112 ;
     RECT  9.457 48.144 10.508 48.168 ;
     RECT  9.961 49.152 10.508 49.32 ;
     RECT  10.508 2.148 10.612 49.692 ;
     RECT  10.612 2.418 10.804 49.422 ;
     RECT  10.804 40.128 10.865 40.44 ;
     RECT  10.804 3.408 10.901 3.432 ;
     RECT  10.804 5.376 10.931 9.048 ;
     RECT  10.931 5.568 11.081 9.048 ;
     RECT  10.804 41.952 11.081 47.208 ;
     RECT  10.804 49.296 11.117 49.32 ;
     RECT  11.081 7.344 11.153 9.048 ;
     RECT  10.804 10.128 11.261 17.88 ;
     RECT  10.804 19.152 11.411 30.936 ;
     RECT  11.411 19.344 11.513 21.672 ;
     RECT  11.081 41.952 11.513 44.712 ;
     RECT  11.261 13.872 11.585 17.88 ;
     RECT  11.585 13.872 11.621 16.536 ;
     RECT  11.585 17.856 11.621 17.88 ;
     RECT  11.411 23.04 11.651 30.936 ;
     RECT  11.513 19.344 11.693 21.576 ;
     RECT  11.081 45.696 11.693 47.208 ;
     RECT  11.621 13.872 11.729 16.488 ;
     RECT  11.693 19.392 11.795 21.576 ;
     RECT  10.804 31.92 11.837 37.608 ;
     RECT  11.651 26.592 11.873 30.936 ;
     RECT  11.081 5.568 11.905 6.264 ;
     RECT  10.865 40.416 11.905 40.44 ;
     RECT  11.513 41.952 11.905 44.472 ;
     RECT  11.795 19.872 11.945 21.576 ;
     RECT  11.905 40.416 11.987 44.472 ;
     RECT  11.837 32.016 11.989 37.608 ;
     RECT  10.804 38.688 11.989 38.712 ;
     RECT  11.261 10.128 12.332 12.792 ;
     RECT  12.121 4.464 12.373 4.488 ;
     RECT  11.905 5.472 12.373 6.264 ;
     RECT  11.989 32.016 12.481 38.712 ;
     RECT  12.445 2.256 12.517 2.28 ;
     RECT  12.373 4.464 12.517 6.264 ;
     RECT  11.153 7.344 12.517 8.616 ;
     RECT  11.693 45.696 12.733 45.72 ;
     RECT  12.517 4.08 12.764 8.616 ;
     RECT  12.517 2.256 12.769 3.048 ;
     RECT  12.764 4.08 12.769 8.952 ;
     RECT  11.873 30.336 12.841 30.936 ;
     RECT  12.481 32.016 12.841 39.336 ;
     RECT  12.332 10.032 12.877 12.792 ;
     RECT  11.729 13.872 12.877 16.392 ;
     RECT  11.945 19.872 13.004 21.144 ;
     RECT  12.841 30.336 13.093 39.336 ;
     RECT  11.987 40.416 13.093 43.896 ;
     RECT  11.651 23.04 13.129 25.512 ;
     RECT  13.021 18.72 13.201 18.744 ;
     RECT  13.004 19.872 13.201 21.912 ;
     RECT  12.769 2.256 13.208 8.952 ;
     RECT  12.877 10.032 13.208 16.392 ;
     RECT  13.201 18.72 13.208 21.912 ;
     RECT  13.129 23.04 13.208 25.56 ;
     RECT  11.873 26.592 13.208 29.352 ;
     RECT  13.093 30.336 13.208 43.896 ;
     RECT  12.733 44.928 13.208 45.72 ;
     RECT  11.693 47.184 13.208 47.208 ;
     RECT  12.625 48.432 13.208 48.456 ;
     RECT  13.057 49.488 13.208 49.512 ;
     RECT  13.208 2.148 13.312 49.692 ;
     RECT  13.312 2.418 13.504 49.512 ;
     RECT  13.504 23.424 13.565 29.352 ;
     RECT  13.504 18.672 13.619 21.384 ;
     RECT  13.504 6.912 13.66 17.16 ;
     RECT  13.619 19.872 13.66 21.384 ;
     RECT  13.66 9.648 13.667 17.16 ;
     RECT  13.66 19.872 13.673 20.136 ;
     RECT  13.504 39.552 13.673 40.44 ;
     RECT  13.504 30.48 13.745 34.92 ;
     RECT  13.504 3.408 13.781 5.592 ;
     RECT  13.66 6.912 13.781 8.28 ;
     RECT  13.504 36.288 13.781 38.472 ;
     RECT  13.781 37.968 13.925 38.424 ;
     RECT  13.781 6.912 13.997 6.936 ;
     RECT  13.667 9.648 14.003 16.392 ;
     RECT  14.003 9.648 14.099 16.056 ;
     RECT  13.66 21.12 14.105 21.384 ;
     RECT  13.504 49.488 14.141 49.512 ;
     RECT  14.099 14.928 14.213 15 ;
     RECT  13.504 43.296 14.243 44.616 ;
     RECT  13.781 8.256 14.429 8.28 ;
     RECT  14.099 9.648 14.429 13.944 ;
     RECT  13.504 48.432 14.429 48.456 ;
     RECT  13.781 4.464 14.569 5.592 ;
     RECT  14.429 9.648 14.641 12.264 ;
     RECT  13.504 45.696 14.641 45.96 ;
     RECT  13.673 40.416 14.681 40.44 ;
     RECT  13.673 19.872 14.713 20.088 ;
     RECT  13.745 30.48 14.753 30.936 ;
     RECT  13.504 41.904 14.821 41.928 ;
     RECT  14.243 43.296 14.821 43.944 ;
     RECT  14.641 45.216 14.821 45.96 ;
     RECT  13.565 23.424 14.825 28.824 ;
     RECT  13.781 3.408 14.861 3.432 ;
     RECT  14.641 9.456 14.861 12.264 ;
     RECT  14.099 15.984 14.933 16.056 ;
     RECT  14.821 41.904 14.965 43.944 ;
     RECT  13.781 36.288 15.001 36.936 ;
     RECT  13.925 37.968 15.001 37.992 ;
     RECT  15.001 36.288 15.013 37.992 ;
     RECT  14.821 39.84 15.013 39.864 ;
     RECT  14.569 4.464 15.037 5.88 ;
     RECT  15.037 4.464 15.073 6.312 ;
     RECT  13.745 32.208 15.073 34.92 ;
     RECT  14.825 23.952 15.181 28.824 ;
     RECT  14.105 21.12 15.217 21.144 ;
     RECT  15.073 4.464 15.289 7.224 ;
     RECT  14.713 19.872 15.289 20.136 ;
     RECT  15.217 21.12 15.289 21.24 ;
     RECT  14.917 17.424 15.325 17.448 ;
     RECT  13.619 18.672 15.325 18.696 ;
     RECT  15.289 3.6 15.361 7.224 ;
     RECT  15.181 23.952 15.361 29.112 ;
     RECT  14.965 40.896 15.361 43.944 ;
     RECT  14.821 45.216 15.361 46.056 ;
     RECT  14.429 13.296 15.397 13.944 ;
     RECT  14.213 14.928 15.397 14.952 ;
     RECT  14.497 47.76 15.397 47.88 ;
     RECT  15.317 50.736 15.401 50.76 ;
     RECT  15.397 47.136 15.469 47.88 ;
     RECT  15.217 49.008 15.469 49.032 ;
     RECT  14.933 16.032 15.577 16.056 ;
     RECT  15.325 17.424 15.577 17.64 ;
     RECT  15.325 18.672 15.613 18.792 ;
     RECT  15.289 19.872 15.613 21.24 ;
     RECT  15.073 32.064 15.613 34.92 ;
     RECT  15.361 3.6 15.901 7.704 ;
     RECT  15.901 3.408 15.908 7.704 ;
     RECT  14.861 9.648 15.908 12.264 ;
     RECT  15.397 13.296 15.908 14.952 ;
     RECT  15.577 16.032 15.908 17.64 ;
     RECT  15.613 18.672 15.908 21.24 ;
     RECT  15.361 23.952 15.908 29.544 ;
     RECT  14.753 30.672 15.908 30.936 ;
     RECT  15.613 32.064 15.908 35.304 ;
     RECT  15.013 36.288 15.908 39.864 ;
     RECT  15.361 40.896 15.908 46.056 ;
     RECT  15.469 47.136 15.908 49.032 ;
     RECT  15.908 2.148 16.012 49.692 ;
     RECT  16.012 2.418 16.204 49.422 ;
     RECT  16.204 13.296 16.265 23.112 ;
     RECT  16.204 3.408 16.301 12.312 ;
     RECT  16.204 48.24 16.301 48.504 ;
     RECT  16.204 24.096 16.337 44.424 ;
     RECT  16.265 13.296 16.355 18.792 ;
     RECT  16.301 48.336 16.481 48.504 ;
     RECT  16.204 45.552 16.517 47.16 ;
     RECT  16.301 4.464 16.553 12.312 ;
     RECT  16.265 19.872 16.589 23.112 ;
     RECT  16.517 45.552 16.625 46.536 ;
     RECT  16.553 5.232 16.705 12.312 ;
     RECT  16.337 24.096 17.057 40.92 ;
     RECT  16.481 48.432 17.065 48.504 ;
     RECT  16.355 17.52 17.075 18.792 ;
     RECT  16.625 45.552 17.093 46.392 ;
     RECT  17.057 35.904 17.129 40.92 ;
     RECT  17.075 17.616 17.171 18.792 ;
     RECT  16.705 9.024 17.201 12.312 ;
     RECT  16.337 41.904 17.237 44.424 ;
     RECT  17.093 46.368 17.267 46.392 ;
     RECT  15.433 51.744 17.267 51.768 ;
     RECT  16.589 21.216 17.269 23.112 ;
     RECT  17.057 24.096 17.269 34.536 ;
     RECT  17.269 21.216 17.273 34.536 ;
     RECT  16.301 3.408 17.341 3.432 ;
     RECT  17.065 48.432 17.345 48.456 ;
     RECT  16.355 13.296 17.377 16.104 ;
     RECT  16.705 5.232 17.489 7.992 ;
     RECT  17.273 21.216 17.561 29.16 ;
     RECT  16.589 19.872 17.665 20.184 ;
     RECT  17.129 36.528 17.665 40.92 ;
     RECT  17.237 41.904 17.665 44.376 ;
     RECT  17.341 2.832 17.845 3.432 ;
     RECT  17.171 18.096 17.881 18.792 ;
     RECT  17.665 19.872 17.881 20.424 ;
     RECT  17.489 7.392 17.953 7.992 ;
     RECT  17.201 9.024 17.953 12.264 ;
     RECT  17.953 7.392 18.169 12.264 ;
     RECT  17.377 13.296 18.169 16.344 ;
     RECT  17.489 5.232 18.205 6.312 ;
     RECT  18.169 7.392 18.229 16.536 ;
     RECT  17.273 30.432 18.229 34.536 ;
     RECT  18.229 30.432 18.236 35.208 ;
     RECT  17.665 36.528 18.241 44.376 ;
     RECT  17.881 18.096 18.277 20.424 ;
     RECT  18.236 30.432 18.277 35.304 ;
     RECT  18.241 36.48 18.277 44.376 ;
     RECT  18.277 30.432 18.313 44.376 ;
     RECT  17.561 22.176 18.385 29.16 ;
     RECT  18.313 30.432 18.385 44.568 ;
     RECT  18.313 46.224 18.421 46.248 ;
     RECT  18.421 46.224 18.457 46.824 ;
     RECT  18.385 22.176 18.493 44.568 ;
     RECT  18.205 5.04 18.565 6.312 ;
     RECT  18.229 7.392 18.565 16.92 ;
     RECT  17.845 2.256 18.608 3.432 ;
     RECT  18.565 5.04 18.608 16.92 ;
     RECT  18.277 18 18.608 20.424 ;
     RECT  18.493 22.176 18.608 44.76 ;
     RECT  18.457 46.224 18.608 46.92 ;
     RECT  18.457 49.488 18.608 49.512 ;
     RECT  18.608 2.148 18.712 49.692 ;
     RECT  18.712 2.418 18.904 49.512 ;
     RECT  18.904 8.832 18.965 20.088 ;
     RECT  18.904 21.12 18.965 29.304 ;
     RECT  18.904 2.832 19.001 3.432 ;
     RECT  18.965 13.344 19.001 20.088 ;
     RECT  18.904 5.04 19.109 5.88 ;
     RECT  18.965 22.752 19.145 29.304 ;
     RECT  19.001 15.504 19.325 20.088 ;
     RECT  19.109 5.136 19.397 5.88 ;
     RECT  18.904 46.08 19.397 47.928 ;
     RECT  19.325 15.744 19.516 20.088 ;
     RECT  19.397 46.08 19.577 46.824 ;
     RECT  18.904 30.672 19.585 45 ;
     RECT  19.001 2.832 19.613 3.288 ;
     RECT  18.904 6.864 19.613 7.704 ;
     RECT  19.613 3.264 19.649 3.288 ;
     RECT  19.613 6.864 19.649 6.888 ;
     RECT  19.145 25.104 19.667 29.304 ;
     RECT  19.585 33.312 19.685 45 ;
     RECT  19.685 40.752 19.852 45 ;
     RECT  19.577 46.08 19.859 46.104 ;
     RECT  19.667 25.44 19.933 29.304 ;
     RECT  19.585 30.672 19.933 32.328 ;
     RECT  19.145 22.752 19.937 24.12 ;
     RECT  19.852 40.752 19.973 44.76 ;
     RECT  19.397 47.856 20.117 47.928 ;
     RECT  19.937 22.8 20.189 24.12 ;
     RECT  18.904 49.488 20.293 49.512 ;
     RECT  20.117 47.856 20.339 47.88 ;
     RECT  19.397 5.232 20.396 5.88 ;
     RECT  18.965 8.832 20.437 12.072 ;
     RECT  19.001 13.344 20.617 14.52 ;
     RECT  19.516 15.744 20.617 18.6 ;
     RECT  19.516 19.584 20.617 20.088 ;
     RECT  18.965 21.12 20.617 21.48 ;
     RECT  20.396 5.232 20.869 6.264 ;
     RECT  20.437 8.544 20.972 12.072 ;
     RECT  20.617 21.12 20.977 21.576 ;
     RECT  20.189 22.8 20.977 23.592 ;
     RECT  20.972 7.92 21.061 12.072 ;
     RECT  19.973 40.752 21.085 44.472 ;
     RECT  21.049 45.792 21.085 45.816 ;
     RECT  20.617 13.344 21.119 20.088 ;
     RECT  21.061 7.44 21.157 12.072 ;
     RECT  21.119 13.344 21.157 20.136 ;
     RECT  20.977 21.12 21.157 23.592 ;
     RECT  19.933 25.44 21.157 32.328 ;
     RECT  19.685 33.312 21.157 39.096 ;
     RECT  20.293 49.44 21.157 49.512 ;
     RECT  20.869 5.088 21.193 6.264 ;
     RECT  21.085 40.752 21.193 46.296 ;
     RECT  20.977 3.024 21.308 3.048 ;
     RECT  21.193 4.992 21.308 6.264 ;
     RECT  21.157 7.44 21.308 20.136 ;
     RECT  21.157 21.12 21.308 32.328 ;
     RECT  21.157 33.312 21.308 39.24 ;
     RECT  21.193 40.752 21.308 46.824 ;
     RECT  21.157 48.96 21.308 49.512 ;
     RECT  21.308 2.148 21.412 49.692 ;
     RECT  21.412 2.418 21.604 49.422 ;
     RECT  21.604 31.392 21.701 45.816 ;
     RECT  21.604 46.8 21.701 46.824 ;
     RECT  21.701 31.44 21.737 45.816 ;
     RECT  21.604 15.504 21.773 27.48 ;
     RECT  21.604 4.992 21.875 14.04 ;
     RECT  21.773 23.568 21.875 27.48 ;
     RECT  21.875 25.584 21.916 27.48 ;
     RECT  21.875 4.992 21.917 12.936 ;
     RECT  21.875 23.568 21.917 24.504 ;
     RECT  21.604 2.832 22.156 3.96 ;
     RECT  21.737 31.44 22.211 45.72 ;
     RECT  22.211 31.44 22.259 43.368 ;
     RECT  22.156 2.832 22.277 3.384 ;
     RECT  21.604 28.704 22.277 30.168 ;
     RECT  22.259 41.04 22.3 43.368 ;
     RECT  22.259 31.44 22.313 39.912 ;
     RECT  22.313 31.44 22.349 38.52 ;
     RECT  21.875 13.92 22.643 14.04 ;
     RECT  21.773 15.504 22.739 22.584 ;
     RECT  21.917 4.992 22.813 10.824 ;
     RECT  22.349 31.44 22.876 37.944 ;
     RECT  22.739 15.504 22.921 17.064 ;
     RECT  22.211 44.448 22.988 45.72 ;
     RECT  22.277 28.8 23.033 30.168 ;
     RECT  21.917 12 23.101 12.936 ;
     RECT  22.643 13.92 23.101 13.944 ;
     RECT  22.876 31.44 23.125 36.12 ;
     RECT  22.813 4.56 23.137 10.824 ;
     RECT  23.101 12 23.137 13.944 ;
     RECT  22.3 42.72 23.173 43.368 ;
     RECT  22.988 44.448 23.173 45.96 ;
     RECT  22.277 3.024 23.269 3.384 ;
     RECT  23.137 4.56 23.269 13.944 ;
     RECT  23.269 3.024 23.353 13.944 ;
     RECT  22.921 15.312 23.713 17.064 ;
     RECT  22.3 41.04 23.965 41.736 ;
     RECT  23.173 42.72 23.965 45.96 ;
     RECT  22.876 37.44 24.001 37.944 ;
     RECT  23.353 2.88 24.008 13.944 ;
     RECT  23.713 15.312 24.008 17.112 ;
     RECT  22.739 18.192 24.008 22.584 ;
     RECT  21.917 23.568 24.008 24.36 ;
     RECT  21.916 25.776 24.008 27.48 ;
     RECT  23.033 28.8 24.008 29.64 ;
     RECT  23.125 30.672 24.008 36.12 ;
     RECT  24.001 37.44 24.008 38.712 ;
     RECT  23.965 41.04 24.008 45.96 ;
     RECT  24.008 2.148 24.112 49.692 ;
     RECT  24.112 2.418 24.304 49.422 ;
     RECT  24.304 6.288 24.365 22.584 ;
     RECT  24.304 4.464 24.419 5.256 ;
     RECT  24.365 16.272 24.509 22.584 ;
     RECT  24.365 6.384 24.517 14.664 ;
     RECT  24.304 2.784 24.545 3.432 ;
     RECT  24.509 16.32 24.659 22.584 ;
     RECT  24.304 29.568 24.659 40.2 ;
     RECT  24.304 41.424 24.659 41.736 ;
     RECT  24.659 29.568 24.689 29.64 ;
     RECT  24.659 41.424 24.725 41.448 ;
     RECT  24.659 31.104 24.797 40.2 ;
     RECT  24.304 25.056 24.933 27.72 ;
     RECT  24.304 42.816 25.049 45.192 ;
     RECT  24.419 4.56 25.085 5.256 ;
     RECT  24.659 19.056 25.121 22.584 ;
     RECT  24.304 48.24 25.297 48.792 ;
     RECT  24.545 2.784 25.301 3.384 ;
     RECT  25.121 21.504 25.333 22.584 ;
     RECT  24.304 23.904 25.333 23.928 ;
     RECT  24.933 25.2 25.333 27.72 ;
     RECT  24.517 11.712 25.481 14.664 ;
     RECT  25.333 25.2 25.513 27.768 ;
     RECT  24.797 31.104 25.517 37.608 ;
     RECT  24.797 39.024 25.553 40.2 ;
     RECT  25.517 31.104 25.621 35.208 ;
     RECT  25.553 39.792 25.621 40.2 ;
     RECT  24.517 6.384 25.625 10.68 ;
     RECT  24.304 46.176 25.669 46.584 ;
     RECT  25.297 47.664 25.669 48.792 ;
     RECT  25.621 39.792 25.693 40.824 ;
     RECT  25.333 21.504 25.697 23.928 ;
     RECT  25.669 46.176 25.772 48.792 ;
     RECT  25.625 7.104 25.801 10.68 ;
     RECT  24.659 16.32 25.837 17.928 ;
     RECT  25.121 19.056 25.837 20.328 ;
     RECT  25.693 39.792 25.916 40.968 ;
     RECT  24.689 29.568 26.017 29.592 ;
     RECT  25.517 36.576 26.017 37.608 ;
     RECT  25.916 39.792 26.053 41.016 ;
     RECT  25.481 12 26.125 14.664 ;
     RECT  25.837 16.32 26.125 20.328 ;
     RECT  25.049 42.816 26.125 45.144 ;
     RECT  25.772 46.176 26.125 49.464 ;
     RECT  26.017 29.568 26.161 29.784 ;
     RECT  25.621 30.768 26.161 35.208 ;
     RECT  26.125 12 26.197 20.328 ;
     RECT  25.697 21.504 26.197 22.344 ;
     RECT  25.697 23.328 26.485 23.928 ;
     RECT  25.513 25.2 26.485 27.96 ;
     RECT  26.161 29.04 26.485 35.208 ;
     RECT  25.301 2.88 26.665 3.384 ;
     RECT  26.197 12 26.665 22.344 ;
     RECT  26.485 23.328 26.665 35.544 ;
     RECT  26.017 36.576 26.665 38.184 ;
     RECT  26.665 2.784 26.708 3.384 ;
     RECT  25.085 4.56 26.708 4.584 ;
     RECT  25.981 5.76 26.708 5.784 ;
     RECT  25.801 7.104 26.708 10.968 ;
     RECT  26.665 12 26.708 38.184 ;
     RECT  26.053 39.792 26.708 41.4 ;
     RECT  26.125 42.816 26.708 49.464 ;
     RECT  26.708 2.148 26.812 49.692 ;
     RECT  26.812 2.418 27.004 49.422 ;
     RECT  27.004 42.432 27.065 48.792 ;
     RECT  27.004 4.944 27.137 6.408 ;
     RECT  27.004 16.848 27.155 21.768 ;
     RECT  27.137 4.944 27.209 5.016 ;
     RECT  27.155 16.848 27.245 18.216 ;
     RECT  27.004 2.64 27.389 2.904 ;
     RECT  27.245 16.848 27.389 17.928 ;
     RECT  27.155 19.536 27.425 21.768 ;
     RECT  27.065 42.432 27.436 47.928 ;
     RECT  27.436 42.432 27.453 45.816 ;
     RECT  27.004 7.392 27.497 7.416 ;
     RECT  27.453 42.432 27.532 44.712 ;
     RECT  27.004 23.328 27.605 38.184 ;
     RECT  27.605 23.328 27.641 29.88 ;
     RECT  27.605 31.152 27.749 38.184 ;
     RECT  27.749 36.336 27.827 38.184 ;
     RECT  27.004 39.6 27.827 41.448 ;
     RECT  27.004 8.688 27.893 10.728 ;
     RECT  27.425 21.408 28.001 21.768 ;
     RECT  27.749 31.152 28.001 34.824 ;
     RECT  27.436 47.136 28.001 47.928 ;
     RECT  27.004 12.336 28.033 12.792 ;
     RECT  27.137 6.384 28.073 6.408 ;
     RECT  28.001 47.184 28.073 47.928 ;
     RECT  28.033 11.76 28.105 12.792 ;
     RECT  27.209 4.992 28.109 5.016 ;
     RECT  28.073 47.184 28.109 47.208 ;
     RECT  27.893 8.736 28.145 10.728 ;
     RECT  28.141 48.96 28.253 48.984 ;
     RECT  28.069 7.44 28.289 7.464 ;
     RECT  27.389 2.64 28.325 2.808 ;
     RECT  28.105 3.84 28.357 3.864 ;
     RECT  27.004 13.92 28.357 14.52 ;
     RECT  28.325 2.64 28.403 2.664 ;
     RECT  28.357 3.84 28.444 4.008 ;
     RECT  28.105 11.76 28.465 12.888 ;
     RECT  28.357 13.872 28.465 14.52 ;
     RECT  27.389 16.848 28.465 17.64 ;
     RECT  27.827 38.16 28.501 38.184 ;
     RECT  27.453 45.744 28.573 45.816 ;
     RECT  27.827 39.792 28.609 41.448 ;
     RECT  28.465 11.76 28.645 17.64 ;
     RECT  27.425 19.536 28.645 20.088 ;
     RECT  27.641 23.328 28.753 28.536 ;
     RECT  27.641 29.52 28.753 29.88 ;
     RECT  28.001 31.2 28.753 34.824 ;
     RECT  28.645 11.76 28.825 20.088 ;
     RECT  27.827 36.336 28.969 37.176 ;
     RECT  28.501 38.16 28.969 38.472 ;
     RECT  28.573 45.696 29.041 45.816 ;
     RECT  28.753 23.328 29.077 29.88 ;
     RECT  28.753 31.2 29.077 35.016 ;
     RECT  28.609 39.792 29.077 41.496 ;
     RECT  27.532 42.72 29.077 44.712 ;
     RECT  29.041 45.696 29.077 46.584 ;
     RECT  28.001 21.408 29.113 21.528 ;
     RECT  29.077 23.328 29.141 35.016 ;
     RECT  29.113 21.312 29.173 21.528 ;
     RECT  28.825 11.184 29.185 20.088 ;
     RECT  29.173 21.12 29.185 21.528 ;
     RECT  29.077 6.864 29.221 6.888 ;
     RECT  29.077 39.792 29.257 44.712 ;
     RECT  29.077 45.696 29.257 47.064 ;
     RECT  29.221 6.096 29.269 6.888 ;
     RECT  28.145 8.736 29.269 10.104 ;
     RECT  29.185 11.184 29.269 21.528 ;
     RECT  28.321 49.008 29.269 49.032 ;
     RECT  28.969 36.336 29.401 38.472 ;
     RECT  29.257 39.792 29.401 47.064 ;
     RECT  28.444 3.84 29.408 3.96 ;
     RECT  29.269 6.096 29.408 7.368 ;
     RECT  29.269 8.736 29.408 21.528 ;
     RECT  29.141 22.896 29.408 35.016 ;
     RECT  29.401 36.336 29.408 47.064 ;
     RECT  29.269 48.144 29.408 49.032 ;
     RECT  29.408 2.148 29.512 49.692 ;
     RECT  29.512 2.418 29.704 49.422 ;
     RECT  29.704 48.096 29.873 48.984 ;
     RECT  29.704 21.12 29.909 22.2 ;
     RECT  29.704 18.432 29.981 20.088 ;
     RECT  29.704 38.208 29.987 40.632 ;
     RECT  29.704 7.776 30.161 10.632 ;
     RECT  29.704 12 30.197 14.808 ;
     RECT  29.704 15.792 30.305 17.4 ;
     RECT  29.704 30.912 30.305 35.016 ;
     RECT  30.305 31.392 30.449 35.016 ;
     RECT  30.449 31.68 30.521 35.016 ;
     RECT  29.704 2.64 30.689 2.664 ;
     RECT  29.704 3.84 30.689 4.536 ;
     RECT  29.704 23.328 30.697 29.592 ;
     RECT  30.689 2.64 30.773 4.536 ;
     RECT  30.697 23.328 30.809 29.688 ;
     RECT  30.161 7.776 30.841 10.2 ;
     RECT  30.305 15.84 30.841 17.4 ;
     RECT  30.773 2.64 30.845 2.664 ;
     RECT  30.805 38.064 30.877 38.088 ;
     RECT  30.197 12.288 30.881 14.808 ;
     RECT  30.809 25.824 30.947 29.688 ;
     RECT  30.773 4.512 30.989 4.536 ;
     RECT  29.704 42.72 31.201 47.064 ;
     RECT  29.873 48.096 31.201 48.456 ;
     RECT  30.521 31.728 31.229 35.016 ;
     RECT  31.201 42.72 31.244 48.456 ;
     RECT  29.981 19.536 31.273 20.088 ;
     RECT  29.909 21.12 31.273 21.624 ;
     RECT  29.704 5.808 31.453 6.36 ;
     RECT  30.841 7.344 31.453 10.2 ;
     RECT  29.704 36.336 31.561 36.6 ;
     RECT  30.881 12.96 31.597 14.808 ;
     RECT  30.841 15.84 31.597 17.688 ;
     RECT  31.273 19.536 31.597 21.624 ;
     RECT  29.987 39.072 31.597 40.632 ;
     RECT  31.244 42.384 31.597 48.456 ;
     RECT  31.597 12.96 31.813 17.688 ;
     RECT  31.229 31.728 31.849 35.352 ;
     RECT  31.561 36.336 31.849 36.84 ;
     RECT  31.849 31.728 31.885 36.84 ;
     RECT  30.809 23.328 31.909 24.504 ;
     RECT  31.597 19.536 31.957 21.72 ;
     RECT  31.909 22.8 31.957 24.504 ;
     RECT  30.947 25.824 31.957 29.592 ;
     RECT  30.877 38.016 31.957 38.088 ;
     RECT  31.597 39.072 31.957 48.456 ;
     RECT  31.957 4.752 32.108 4.776 ;
     RECT  31.453 5.808 32.108 10.2 ;
     RECT  31.813 12.96 32.108 18.264 ;
     RECT  31.957 19.536 32.108 29.592 ;
     RECT  31.885 30.864 32.108 36.84 ;
     RECT  31.957 38.016 32.108 48.456 ;
     RECT  32.108 2.148 32.212 49.692 ;
     RECT  32.212 2.418 32.404 49.422 ;
     RECT  32.404 8.736 32.537 15.048 ;
     RECT  32.404 48.672 32.681 49.032 ;
     RECT  32.537 8.736 32.717 12.216 ;
     RECT  32.404 43.392 32.717 47.64 ;
     RECT  32.717 8.832 32.771 12.216 ;
     RECT  32.404 30.48 32.789 42.216 ;
     RECT  32.404 16.176 32.897 29.064 ;
     RECT  32.717 43.392 32.933 47.544 ;
     RECT  32.933 43.392 33.011 45.384 ;
     RECT  32.933 46.56 33.059 47.544 ;
     RECT  32.897 16.176 33.077 16.344 ;
     RECT  32.681 48.768 33.077 49.032 ;
     RECT  32.897 17.472 33.107 29.064 ;
     RECT  33.011 43.392 33.113 43.608 ;
     RECT  33.107 17.472 33.149 23.016 ;
     RECT  33.077 49.008 33.149 49.032 ;
     RECT  33.149 19.68 33.155 23.016 ;
     RECT  33.107 24.096 33.185 29.064 ;
     RECT  33.185 24.288 33.257 29.064 ;
     RECT  32.404 4.752 33.292 5.352 ;
     RECT  32.789 30.48 33.329 40.92 ;
     RECT  33.329 33.6 33.347 40.92 ;
     RECT  33.257 24.288 33.401 24.504 ;
     RECT  33.059 46.56 33.401 47.304 ;
     RECT  33.329 30.48 33.493 32.28 ;
     RECT  33.401 24.48 33.539 24.504 ;
     RECT  32.771 8.832 33.545 10.488 ;
     RECT  32.404 3.312 33.585 3.432 ;
     RECT  33.292 4.752 33.585 5.16 ;
     RECT  33.347 33.6 33.635 39.576 ;
     RECT  33.011 44.688 33.653 45.384 ;
     RECT  33.585 3.312 33.683 5.16 ;
     RECT  33.155 19.776 33.683 23.016 ;
     RECT  32.537 13.872 33.725 15.048 ;
     RECT  32.404 7.296 33.761 7.512 ;
     RECT  33.577 12.288 33.781 12.36 ;
     RECT  32.789 42.192 33.797 42.216 ;
     RECT  34.009 6.912 34.225 6.936 ;
     RECT  33.545 8.832 34.225 9.816 ;
     RECT  33.401 46.56 34.405 46.824 ;
     RECT  33.493 30.336 34.441 32.28 ;
     RECT  33.635 33.6 34.441 37.608 ;
     RECT  33.635 38.64 34.477 39.576 ;
     RECT  33.347 40.56 34.477 40.92 ;
     RECT  33.149 17.472 34.513 18.6 ;
     RECT  33.683 19.776 34.513 21.768 ;
     RECT  34.225 8.736 34.549 9.816 ;
     RECT  33.683 22.944 34.693 22.968 ;
     RECT  34.477 23.952 34.693 24.216 ;
     RECT  34.405 46.56 34.693 47.4 ;
     RECT  34.513 17.472 34.765 21.768 ;
     RECT  33.113 43.392 34.765 43.56 ;
     RECT  34.693 22.944 34.801 24.216 ;
     RECT  34.081 2.304 34.808 2.328 ;
     RECT  33.683 3.312 34.808 3.912 ;
     RECT  33.683 5.136 34.808 5.16 ;
     RECT  34.225 6.864 34.808 6.936 ;
     RECT  34.549 8.736 34.808 10.104 ;
     RECT  33.781 11.328 34.808 12.36 ;
     RECT  33.725 13.872 34.808 13.992 ;
     RECT  33.725 14.976 34.808 15.048 ;
     RECT  34.765 17.472 34.808 21.96 ;
     RECT  34.801 22.944 34.808 24.696 ;
     RECT  33.257 25.824 34.808 29.064 ;
     RECT  34.441 30.336 34.808 37.608 ;
     RECT  34.477 38.64 34.808 40.92 ;
     RECT  34.765 43.008 34.808 43.56 ;
     RECT  33.653 44.688 34.808 44.712 ;
     RECT  34.693 46.56 34.808 48.168 ;
     RECT  34.808 2.148 34.912 49.692 ;
     RECT  34.912 2.304 35.104 49.422 ;
     RECT  35.104 2.304 35.165 3.912 ;
     RECT  35.104 30.336 35.219 42.12 ;
     RECT  35.104 6.192 35.315 15.048 ;
     RECT  35.219 30.336 35.345 37.608 ;
     RECT  35.104 46.704 35.345 49.032 ;
     RECT  35.345 36.336 35.381 37.608 ;
     RECT  35.104 43.392 35.381 44.712 ;
     RECT  35.104 23.808 35.417 24.696 ;
     RECT  35.315 10.752 35.452 15.048 ;
     RECT  35.219 38.592 35.453 42.12 ;
     RECT  35.417 24.144 35.489 24.552 ;
     RECT  35.453 41.952 35.633 42.12 ;
     RECT  35.104 16.416 35.74 16.44 ;
     RECT  35.104 17.424 35.749 21.96 ;
     RECT  35.452 11.136 35.813 15.048 ;
     RECT  35.381 43.392 35.813 44.664 ;
     RECT  35.813 11.136 35.921 13.944 ;
     RECT  35.749 19.344 35.939 21.96 ;
     RECT  35.921 11.136 35.957 12.312 ;
     RECT  35.381 36.48 35.957 37.608 ;
     RECT  35.749 17.424 35.993 18.168 ;
     RECT  35.633 41.952 36.029 41.976 ;
     RECT  35.813 43.776 36.029 44.664 ;
     RECT  35.104 25.728 36.085 29.064 ;
     RECT  35.345 30.336 36.085 35.304 ;
     RECT  35.315 6.192 36.188 9.768 ;
     RECT  36.188 6 36.227 9.768 ;
     RECT  36.227 6 36.229 9.096 ;
     RECT  36.229 5.184 36.275 9.096 ;
     RECT  35.813 14.976 36.277 15.048 ;
     RECT  36.275 5.184 36.313 5.208 ;
     RECT  35.939 21.36 36.323 21.96 ;
     RECT  36.085 25.728 36.349 35.304 ;
     RECT  35.165 3.12 36.353 3.864 ;
     RECT  36.353 3.12 36.493 3.72 ;
     RECT  36.349 25.728 36.508 35.352 ;
     RECT  35.453 38.592 36.673 40.584 ;
     RECT  36.029 44.448 36.709 44.664 ;
     RECT  36.323 21.504 36.853 21.96 ;
     RECT  35.489 24.192 36.901 24.552 ;
     RECT  36.508 25.728 36.901 29.448 ;
     RECT  35.921 13.344 36.997 13.944 ;
     RECT  36.277 14.976 36.997 15.528 ;
     RECT  36.508 30.576 36.997 35.352 ;
     RECT  35.957 36.48 36.997 36.504 ;
     RECT  36.997 13.344 37.045 15.528 ;
     RECT  35.993 17.472 37.069 18.168 ;
     RECT  35.939 19.344 37.069 20.136 ;
     RECT  35.957 11.136 37.249 11.304 ;
     RECT  37.045 13.344 37.381 16.008 ;
     RECT  35.345 47.232 37.429 49.032 ;
     RECT  36.493 2.208 37.508 3.72 ;
     RECT  36.313 5.088 37.508 5.208 ;
     RECT  36.275 6.816 37.508 9.096 ;
     RECT  37.249 11.136 37.508 11.448 ;
     RECT  37.381 12.48 37.508 16.008 ;
     RECT  37.069 17.472 37.508 20.136 ;
     RECT  36.853 21.504 37.508 22.104 ;
     RECT  36.901 24.192 37.508 29.448 ;
     RECT  36.997 30.576 37.508 36.504 ;
     RECT  35.957 37.584 37.508 37.608 ;
     RECT  36.673 38.592 37.508 41.064 ;
     RECT  37.141 43.344 37.508 43.368 ;
     RECT  36.709 44.448 37.508 45.48 ;
     RECT  37.429 46.896 37.508 49.032 ;
     RECT  37.508 2.148 37.612 49.692 ;
     RECT  37.612 2.418 37.804 49.422 ;
     RECT  37.804 3.072 37.865 3.432 ;
     RECT  37.804 44.64 37.865 48.984 ;
     RECT  37.804 25.728 37.901 35.544 ;
     RECT  37.804 43.344 37.955 43.56 ;
     RECT  37.901 33.264 37.973 35.544 ;
     RECT  37.804 5.088 37.981 9.624 ;
     RECT  37.804 23.568 38.017 24.552 ;
     RECT  37.865 44.64 38.051 46.248 ;
     RECT  37.865 47.808 38.189 48.984 ;
     RECT  37.804 11.232 38.243 11.496 ;
     RECT  38.017 23.568 38.261 24.504 ;
     RECT  37.901 25.728 38.261 32.28 ;
     RECT  38.261 25.776 38.297 32.28 ;
     RECT  37.804 36.912 38.297 39.288 ;
     RECT  38.243 11.424 38.333 11.496 ;
     RECT  37.804 13.104 38.333 22.488 ;
     RECT  38.297 25.776 38.405 29.064 ;
     RECT  38.333 21.12 38.441 22.488 ;
     RECT  38.333 13.104 38.585 20.136 ;
     RECT  38.441 21.36 38.729 22.488 ;
     RECT  37.981 5.664 38.773 9.624 ;
     RECT  38.297 30.48 38.801 32.28 ;
     RECT  38.051 45.456 38.801 46.248 ;
     RECT  38.585 13.104 38.833 20.088 ;
     RECT  38.261 23.568 38.867 24.36 ;
     RECT  37.955 43.344 38.873 43.416 ;
     RECT  37.865 3.072 38.905 3.096 ;
     RECT  38.833 13.056 38.941 20.088 ;
     RECT  38.405 25.776 38.945 29.016 ;
     RECT  38.773 5.664 38.981 10.296 ;
     RECT  38.867 23.616 38.981 24.36 ;
     RECT  38.729 21.36 39.148 21.96 ;
     RECT  38.981 23.952 39.161 24.36 ;
     RECT  37.804 40.368 39.161 41.736 ;
     RECT  38.981 7.344 39.197 10.296 ;
     RECT  38.905 3.072 39.221 4.296 ;
     RECT  39.221 2.832 39.229 4.296 ;
     RECT  39.229 2.832 39.301 4.536 ;
     RECT  38.981 5.664 39.301 6.264 ;
     RECT  37.973 33.264 39.301 35.256 ;
     RECT  38.297 36.912 39.301 37.08 ;
     RECT  38.801 30.72 39.337 32.28 ;
     RECT  39.301 33.264 39.337 37.08 ;
     RECT  38.333 11.472 39.481 11.496 ;
     RECT  38.941 12.864 39.481 20.088 ;
     RECT  39.337 30.72 39.553 37.08 ;
     RECT  38.189 47.808 39.589 47.832 ;
     RECT  38.297 38.736 39.733 39.288 ;
     RECT  39.161 40.368 39.733 41.16 ;
     RECT  38.945 25.824 39.849 29.016 ;
     RECT  38.801 45.552 39.877 46.248 ;
     RECT  39.589 47.328 39.877 47.832 ;
     RECT  39.301 2.832 40.165 6.264 ;
     RECT  39.197 7.344 40.165 9.672 ;
     RECT  39.877 45.552 40.165 47.832 ;
     RECT  40.165 2.832 40.208 9.672 ;
     RECT  39.481 11.472 40.208 20.088 ;
     RECT  39.148 21.744 40.208 21.96 ;
     RECT  39.161 24.336 40.208 24.36 ;
     RECT  39.849 25.824 40.208 29.064 ;
     RECT  39.553 30.72 40.208 37.416 ;
     RECT  39.733 38.736 40.208 41.16 ;
     RECT  38.873 43.344 40.208 43.368 ;
     RECT  40.165 44.736 40.208 47.832 ;
     RECT  38.189 48.96 40.208 48.984 ;
     RECT  40.208 2.148 40.312 49.692 ;
     RECT  40.312 2.418 40.504 49.422 ;
     RECT  40.504 39.84 40.565 41.16 ;
     RECT  40.504 42.768 40.637 45.192 ;
     RECT  40.637 43.632 40.709 45.192 ;
     RECT  40.504 13.104 40.781 13.944 ;
     RECT  40.504 28.704 40.924 35.544 ;
     RECT  40.504 21.072 41.105 22.728 ;
     RECT  40.924 28.704 41.105 29.688 ;
     RECT  40.504 23.904 41.321 24.408 ;
     RECT  41.105 28.752 41.321 29.688 ;
     RECT  40.504 46.56 41.393 46.584 ;
     RECT  41.105 21.408 41.489 22.728 ;
     RECT  41.321 23.904 41.489 23.928 ;
     RECT  40.504 14.976 41.533 15.048 ;
     RECT  40.565 40.416 41.605 40.584 ;
     RECT  40.709 43.632 41.605 44.472 ;
     RECT  40.504 36.912 41.641 37.032 ;
     RECT  40.781 13.824 41.789 13.944 ;
     RECT  41.789 13.92 41.821 13.944 ;
     RECT  41.533 14.976 41.821 15.96 ;
     RECT  40.504 25.824 41.821 27.72 ;
     RECT  41.641 36.912 41.845 37.704 ;
     RECT  40.504 17.664 41.857 18.312 ;
     RECT  41.321 28.992 41.861 29.688 ;
     RECT  41.605 40.224 41.891 40.584 ;
     RECT  41.857 16.944 41.965 18.312 ;
     RECT  40.504 19.344 41.965 20.088 ;
     RECT  40.504 6.864 42.037 10.008 ;
     RECT  40.924 30.864 42.037 35.544 ;
     RECT  41.845 36.912 42.037 38.184 ;
     RECT  40.504 5.184 42.073 5.208 ;
     RECT  40.504 47.904 42.073 48.696 ;
     RECT  41.965 16.944 42.109 20.088 ;
     RECT  41.489 21.408 42.109 23.928 ;
     RECT  42.073 5.184 42.145 5.4 ;
     RECT  42.037 6.768 42.181 10.008 ;
     RECT  41.821 13.92 42.181 15.96 ;
     RECT  42.109 16.944 42.181 23.928 ;
     RECT  42.181 13.92 42.361 23.928 ;
     RECT  41.821 25.344 42.361 27.72 ;
     RECT  42.145 4.56 42.397 5.4 ;
     RECT  42.181 6.768 42.397 10.248 ;
     RECT  42.037 30.768 42.469 35.544 ;
     RECT  42.397 4.56 42.541 10.248 ;
     RECT  40.504 11.472 42.541 11.496 ;
     RECT  42.361 25.104 42.721 27.72 ;
     RECT  42.469 28.752 42.721 28.776 ;
     RECT  42.541 4.56 42.757 11.496 ;
     RECT  42.253 12.528 42.757 12.552 ;
     RECT  41.605 43.392 42.757 44.472 ;
     RECT  42.109 46.128 42.757 46.152 ;
     RECT  42.073 47.664 42.757 48.696 ;
     RECT  41.605 42.336 42.793 42.36 ;
     RECT  41.891 40.224 42.829 40.44 ;
     RECT  40.504 3.408 42.908 3.432 ;
     RECT  42.757 4.56 42.908 12.552 ;
     RECT  42.361 13.92 42.908 24.12 ;
     RECT  42.721 25.104 42.908 28.776 ;
     RECT  42.469 30.144 42.908 35.544 ;
     RECT  42.037 36.912 42.908 38.472 ;
     RECT  42.829 40.128 42.908 40.44 ;
     RECT  42.793 41.664 42.908 42.36 ;
     RECT  42.757 43.392 42.908 45 ;
     RECT  42.757 46.032 42.908 48.696 ;
     RECT  42.908 2.148 43.012 49.692 ;
     RECT  43.012 2.418 43.204 49.422 ;
     RECT  43.204 18.768 43.373 23.064 ;
     RECT  43.204 12.48 43.445 12.552 ;
     RECT  43.204 37.008 43.481 41.928 ;
     RECT  43.204 43.392 43.481 43.416 ;
     RECT  43.204 13.92 43.589 16.92 ;
     RECT  43.204 44.976 43.589 46.632 ;
     RECT  43.204 3.696 43.913 4.248 ;
     RECT  43.204 6.864 43.913 9.336 ;
     RECT  43.589 13.92 43.913 16.296 ;
     RECT  43.373 19.584 43.913 23.064 ;
     RECT  43.481 37.008 43.977 38.952 ;
     RECT  43.204 49.296 44.051 49.32 ;
     RECT  43.204 47.664 44.057 48.024 ;
     RECT  43.204 5.232 44.093 5.88 ;
     RECT  44.093 5.616 44.099 5.88 ;
     RECT  43.913 13.92 44.197 16.056 ;
     RECT  43.913 3.792 44.237 4.248 ;
     RECT  43.204 30.144 44.273 35.352 ;
     RECT  43.481 40.032 44.345 41.928 ;
     RECT  43.204 25.824 44.413 28.776 ;
     RECT  43.977 37.008 44.417 37.08 ;
     RECT  43.913 21.504 44.449 23.064 ;
     RECT  43.589 44.976 44.485 45 ;
     RECT  44.417 37.056 44.489 37.08 ;
     RECT  43.977 38.16 44.489 38.952 ;
     RECT  44.237 3.936 44.497 4.248 ;
     RECT  44.413 25.824 44.514 29.16 ;
     RECT  44.485 44.208 44.561 45 ;
     RECT  44.514 25.824 44.597 29.112 ;
     RECT  44.305 17.76 44.701 17.784 ;
     RECT  43.589 46.416 44.773 46.632 ;
     RECT  43.913 19.584 45.013 20.088 ;
     RECT  43.204 10.416 45.025 10.44 ;
     RECT  45.013 19.2 45.025 20.088 ;
     RECT  44.449 21.504 45.025 23.352 ;
     RECT  44.099 5.856 45.061 5.88 ;
     RECT  43.913 6.864 45.061 9.096 ;
     RECT  45.025 10.416 45.061 10.872 ;
     RECT  44.773 46.224 45.061 46.632 ;
     RECT  44.057 47.664 45.061 47.688 ;
     RECT  44.561 44.208 45.133 44.232 ;
     RECT  44.489 38.16 45.212 38.184 ;
     RECT  45.212 38.112 45.241 38.184 ;
     RECT  45.061 45.552 45.277 46.632 ;
     RECT  45.061 47.664 45.277 47.88 ;
     RECT  44.497 4.176 45.385 4.248 ;
     RECT  45.061 5.856 45.385 10.872 ;
     RECT  44.345 40.032 45.385 40.824 ;
     RECT  43.204 24.528 45.457 24.552 ;
     RECT  44.701 17.76 45.493 18.072 ;
     RECT  45.025 19.2 45.493 23.352 ;
     RECT  44.269 2.256 45.608 2.28 ;
     RECT  45.385 4.176 45.608 10.872 ;
     RECT  44.485 11.952 45.608 11.976 ;
     RECT  44.197 13.056 45.608 16.056 ;
     RECT  45.493 17.76 45.608 23.352 ;
     RECT  45.457 24.432 45.608 24.552 ;
     RECT  44.597 25.824 45.608 28.776 ;
     RECT  44.273 30.432 45.608 35.352 ;
     RECT  45.241 37.584 45.608 38.184 ;
     RECT  45.385 39.312 45.608 40.824 ;
     RECT  45.133 42.192 45.608 42.216 ;
     RECT  45.133 43.632 45.608 44.232 ;
     RECT  45.277 45.552 45.608 47.88 ;
     RECT  45.608 2.148 45.712 49.692 ;
     RECT  45.712 2.256 45.904 49.422 ;
     RECT  45.904 12 45.965 16.056 ;
     RECT  45.965 13.68 46.019 16.056 ;
     RECT  45.904 2.256 46.073 2.28 ;
     RECT  45.904 39.312 46.073 42.216 ;
     RECT  45.904 25.536 46.163 28.776 ;
     RECT  45.904 18.816 46.181 24.456 ;
     RECT  45.904 10.128 46.217 10.728 ;
     RECT  46.163 25.536 46.217 28.488 ;
     RECT  45.904 43.872 46.253 48.504 ;
     RECT  45.904 17.088 46.289 17.688 ;
     RECT  46.181 18.816 46.289 20.664 ;
     RECT  45.904 5.088 46.325 9.096 ;
     RECT  46.289 17.088 46.433 17.112 ;
     RECT  46.073 39.312 46.433 40.968 ;
     RECT  46.019 13.68 46.505 15.96 ;
     RECT  46.253 43.872 46.541 45 ;
     RECT  46.217 10.128 46.547 10.296 ;
     RECT  46.217 25.536 46.685 28.344 ;
     RECT  46.541 43.872 46.793 44.472 ;
     RECT  46.253 46.032 46.793 48.504 ;
     RECT  45.965 12 46.865 12.456 ;
     RECT  46.793 43.872 46.865 44.136 ;
     RECT  46.325 7.296 46.937 9.096 ;
     RECT  46.937 8.496 47.005 9.096 ;
     RECT  46.685 25.824 47.009 28.344 ;
     RECT  46.937 7.296 47.153 7.368 ;
     RECT  46.181 21.936 47.153 24.456 ;
     RECT  45.904 30.24 47.257 35.304 ;
     RECT  46.433 39.312 47.261 40.056 ;
     RECT  45.904 37.584 47.317 37.656 ;
     RECT  46.793 46.416 47.509 48.504 ;
     RECT  46.547 10.272 47.581 10.296 ;
     RECT  46.865 12.24 47.689 12.456 ;
     RECT  46.505 13.68 47.689 13.944 ;
     RECT  47.113 36.336 47.845 36.36 ;
     RECT  47.317 37.584 47.845 37.896 ;
     RECT  46.073 42.192 47.852 42.216 ;
     RECT  47.153 7.296 47.941 7.32 ;
     RECT  47.509 2.592 48.308 2.616 ;
     RECT  46.325 5.088 48.308 6.072 ;
     RECT  47.941 7.152 48.308 7.32 ;
     RECT  47.005 8.496 48.308 9.24 ;
     RECT  47.581 10.272 48.308 10.728 ;
     RECT  47.689 12.24 48.308 13.944 ;
     RECT  46.505 14.976 48.308 15.96 ;
     RECT  47.257 17.568 48.308 17.592 ;
     RECT  46.289 19.392 48.308 20.664 ;
     RECT  47.153 21.936 48.308 23.976 ;
     RECT  47.009 25.824 48.308 28.296 ;
     RECT  47.257 30.144 48.308 35.304 ;
     RECT  47.845 36.336 48.308 37.896 ;
     RECT  47.261 39.312 48.308 39.864 ;
     RECT  47.852 41.52 48.308 42.216 ;
     RECT  46.865 43.872 48.308 43.896 ;
     RECT  47.509 46.416 48.308 49.032 ;
     RECT  48.308 2.148 48.412 49.692 ;
     RECT  48.412 2.418 48.604 49.422 ;
     RECT  48.604 5.232 48.665 5.256 ;
     RECT  48.604 36.336 48.665 36.36 ;
     RECT  48.604 18.768 48.809 18.792 ;
     RECT  48.604 39.84 49.025 39.864 ;
     RECT  48.604 13.92 49.597 13.944 ;
     RECT  48.604 14.976 49.597 15.912 ;
     RECT  49.597 13.92 50.425 15.912 ;
     RECT  50.425 13.92 50.713 16.008 ;
     RECT  48.604 30.912 51.109 35.304 ;
     RECT  48.604 25.824 51.185 27.72 ;
     RECT  51.185 25.824 51.221 27.624 ;
     RECT  51.109 30.192 51.289 35.304 ;
     RECT  51.289 30 51.433 35.304 ;
     RECT  48.604 8.832 51.437 9.096 ;
     RECT  51.221 25.824 51.473 27.48 ;
     RECT  51.433 29.52 51.505 35.304 ;
     RECT  51.437 8.832 51.509 8.856 ;
     RECT  48.604 19.872 51.545 20.088 ;
     RECT  51.505 29.328 51.577 35.304 ;
     RECT  51.577 29.136 51.725 35.304 ;
     RECT  51.473 26.064 51.756 26.088 ;
     RECT  51.473 26.088 51.761 26.16 ;
     RECT  51.473 26.16 51.756 26.184 ;
     RECT  51.473 26.184 51.761 26.256 ;
     RECT  51.473 26.256 51.756 26.28 ;
     RECT  51.473 26.28 51.761 26.352 ;
     RECT  51.473 26.352 51.756 26.376 ;
     RECT  51.473 26.376 51.761 26.448 ;
     RECT  51.473 26.448 51.756 26.472 ;
     RECT  51.473 26.472 51.761 26.544 ;
     RECT  51.473 26.544 51.756 26.568 ;
     RECT  51.473 26.568 51.761 26.64 ;
     RECT  51.473 26.64 51.756 26.664 ;
     RECT  51.473 26.664 51.761 26.736 ;
     RECT  51.473 26.736 51.756 26.76 ;
     RECT  51.473 26.76 51.761 26.832 ;
     RECT  51.473 26.832 51.756 26.856 ;
     RECT  51.473 26.856 51.761 26.928 ;
     RECT  51.473 26.928 51.756 26.952 ;
     RECT  51.473 26.952 51.761 27.024 ;
     RECT  51.473 27.024 51.756 27.048 ;
     RECT  51.473 27.048 51.761 27.48 ;
     RECT  51.545 19.872 51.797 19.896 ;
     RECT  50.713 13.008 51.756 13.032 ;
     RECT  50.713 13.032 51.804 13.104 ;
     RECT  50.713 13.104 51.756 13.128 ;
     RECT  50.713 13.128 51.804 13.2 ;
     RECT  50.713 13.2 51.756 13.224 ;
     RECT  50.713 13.224 51.804 13.296 ;
     RECT  50.713 13.296 51.756 13.32 ;
     RECT  50.713 13.32 51.804 13.392 ;
     RECT  50.713 13.392 51.756 13.416 ;
     RECT  50.713 13.416 51.804 13.488 ;
     RECT  50.713 13.488 51.756 13.512 ;
     RECT  50.713 13.512 51.804 13.584 ;
     RECT  50.713 13.584 51.756 13.608 ;
     RECT  50.713 13.608 51.804 13.68 ;
     RECT  50.713 13.68 51.756 13.704 ;
     RECT  50.713 13.704 51.804 13.776 ;
     RECT  50.713 13.776 51.756 13.8 ;
     RECT  50.713 13.8 51.804 13.872 ;
     RECT  50.713 13.872 51.756 13.896 ;
     RECT  50.713 13.896 51.804 13.968 ;
     RECT  50.713 13.968 51.756 13.992 ;
     RECT  50.713 13.992 51.804 14.064 ;
     RECT  50.713 14.064 51.756 14.088 ;
     RECT  50.713 14.088 51.804 14.16 ;
     RECT  50.713 14.16 51.756 14.184 ;
     RECT  50.713 14.184 51.804 14.256 ;
     RECT  50.713 14.256 51.756 14.28 ;
     RECT  50.713 14.28 51.804 14.352 ;
     RECT  50.713 14.352 51.756 14.376 ;
     RECT  50.713 14.376 51.804 14.448 ;
     RECT  50.713 14.448 51.756 14.472 ;
     RECT  50.713 14.472 51.804 14.544 ;
     RECT  50.713 14.544 51.756 14.568 ;
     RECT  50.713 14.568 51.804 14.64 ;
     RECT  50.713 14.64 51.756 14.664 ;
     RECT  50.713 14.664 51.804 14.736 ;
     RECT  50.713 14.736 51.756 14.76 ;
     RECT  50.713 14.76 51.804 14.832 ;
     RECT  50.713 14.832 51.756 14.856 ;
     RECT  50.713 14.856 51.804 14.928 ;
     RECT  50.713 14.928 51.756 14.952 ;
     RECT  50.713 14.952 51.804 15.024 ;
     RECT  50.713 15.024 51.756 15.048 ;
     RECT  50.713 15.048 51.804 15.12 ;
     RECT  50.713 15.12 51.756 15.144 ;
     RECT  50.713 15.144 51.804 15.216 ;
     RECT  50.713 15.216 51.756 15.24 ;
     RECT  50.713 15.24 51.804 15.312 ;
     RECT  50.713 15.312 51.756 15.336 ;
     RECT  50.713 15.336 51.804 15.408 ;
     RECT  50.713 15.408 51.756 15.432 ;
     RECT  50.713 15.432 51.804 15.504 ;
     RECT  50.713 15.504 51.756 15.528 ;
     RECT  50.713 15.528 51.804 15.6 ;
     RECT  50.713 15.6 51.756 15.624 ;
     RECT  50.713 15.624 51.804 15.696 ;
     RECT  50.713 15.696 51.756 15.72 ;
     RECT  50.713 15.72 51.804 15.792 ;
     RECT  50.713 15.792 51.756 15.816 ;
     RECT  50.713 15.816 51.804 15.888 ;
     RECT  50.713 15.888 51.756 15.912 ;
     RECT  50.713 15.912 51.804 15.984 ;
     RECT  50.713 15.984 51.756 16.008 ;
     RECT  51.761 26.088 51.804 26.16 ;
     RECT  51.761 26.184 51.804 26.256 ;
     RECT  51.761 26.28 51.804 26.352 ;
     RECT  51.761 26.376 51.804 26.448 ;
     RECT  51.761 26.472 51.804 26.544 ;
     RECT  51.761 26.568 51.804 26.64 ;
     RECT  51.761 26.664 51.804 26.736 ;
     RECT  51.761 26.76 51.804 26.832 ;
     RECT  51.761 26.856 51.804 26.928 ;
     RECT  51.761 26.952 51.804 27.024 ;
     RECT  51.725 29.136 51.756 29.16 ;
     RECT  51.725 29.16 51.804 29.232 ;
     RECT  51.725 29.232 51.756 29.256 ;
     RECT  51.725 29.256 51.804 29.328 ;
     RECT  51.725 29.328 51.756 29.352 ;
     RECT  51.725 29.352 51.804 29.424 ;
     RECT  51.725 29.424 51.756 29.448 ;
     RECT  51.725 29.448 51.804 29.52 ;
     RECT  51.725 29.52 51.756 29.544 ;
     RECT  51.725 29.544 51.804 29.616 ;
     RECT  51.725 29.616 51.756 29.64 ;
     RECT  51.725 29.64 51.804 29.712 ;
     RECT  51.725 29.712 51.756 29.736 ;
     RECT  51.725 29.736 51.804 29.808 ;
     RECT  51.725 29.808 51.756 29.832 ;
     RECT  51.725 29.832 51.804 29.904 ;
     RECT  51.725 29.904 51.756 29.928 ;
     RECT  51.725 29.928 51.804 30 ;
     RECT  51.725 30 51.756 30.024 ;
     RECT  51.725 30.024 51.804 30.096 ;
     RECT  51.725 30.096 51.756 30.12 ;
     RECT  51.725 30.12 51.804 30.192 ;
     RECT  51.725 30.192 51.756 30.216 ;
     RECT  51.725 30.216 51.804 30.288 ;
     RECT  51.725 30.288 51.756 30.312 ;
     RECT  51.725 30.312 51.804 30.384 ;
     RECT  51.725 30.384 51.756 30.408 ;
     RECT  51.725 30.408 51.804 30.48 ;
     RECT  51.725 30.48 51.756 30.504 ;
     RECT  51.725 30.504 51.804 30.576 ;
     RECT  51.725 30.576 51.756 30.6 ;
     RECT  51.725 30.6 51.804 30.672 ;
     RECT  51.725 30.672 51.756 30.696 ;
     RECT  51.725 30.696 51.804 30.768 ;
     RECT  51.725 30.768 51.756 30.792 ;
     RECT  51.725 30.792 51.804 30.864 ;
     RECT  51.725 30.864 51.756 30.888 ;
     RECT  51.725 30.888 51.804 30.96 ;
     RECT  51.725 30.96 51.756 30.984 ;
     RECT  51.725 30.984 51.804 31.056 ;
     RECT  51.725 31.056 51.756 31.08 ;
     RECT  51.725 31.08 51.804 31.152 ;
     RECT  51.725 31.152 51.756 31.176 ;
     RECT  51.725 31.176 51.804 31.248 ;
     RECT  51.725 31.248 51.756 31.272 ;
     RECT  51.725 31.272 51.804 31.344 ;
     RECT  51.725 31.344 51.756 31.368 ;
     RECT  51.725 31.368 51.804 31.44 ;
     RECT  51.725 31.44 51.756 31.464 ;
     RECT  51.725 31.464 51.804 31.536 ;
     RECT  51.725 31.536 51.756 31.56 ;
     RECT  51.725 31.56 51.804 31.632 ;
     RECT  51.725 31.632 51.756 31.656 ;
     RECT  51.725 31.656 51.804 31.728 ;
     RECT  51.725 31.728 51.756 31.752 ;
     RECT  51.725 31.752 51.804 31.824 ;
     RECT  51.725 31.824 51.756 31.848 ;
     RECT  51.725 31.848 51.804 31.92 ;
     RECT  51.725 31.92 51.756 31.944 ;
     RECT  51.725 31.944 51.804 32.016 ;
     RECT  51.725 32.016 51.756 32.04 ;
     RECT  51.725 32.04 51.804 32.112 ;
     RECT  51.725 32.112 51.756 32.136 ;
     RECT  51.725 32.136 51.804 32.208 ;
     RECT  51.725 32.208 51.756 32.232 ;
     RECT  51.725 32.232 51.804 32.304 ;
     RECT  51.725 32.304 51.756 32.328 ;
     RECT  51.725 32.328 51.804 32.4 ;
     RECT  51.725 32.4 51.756 32.424 ;
     RECT  51.725 32.424 51.804 32.496 ;
     RECT  51.725 32.496 51.756 32.52 ;
     RECT  51.725 32.52 51.804 32.592 ;
     RECT  51.725 32.592 51.756 32.616 ;
     RECT  51.725 32.616 51.804 32.688 ;
     RECT  51.725 32.688 51.756 32.712 ;
     RECT  51.725 32.712 51.804 32.784 ;
     RECT  51.725 32.784 51.756 32.808 ;
     RECT  51.725 32.808 51.804 32.88 ;
     RECT  51.725 32.88 51.756 32.904 ;
     RECT  51.725 32.904 51.804 32.976 ;
     RECT  51.725 32.976 51.756 33 ;
     RECT  51.725 33 51.804 33.072 ;
     RECT  51.725 33.072 51.756 33.096 ;
     RECT  51.725 33.096 51.804 33.168 ;
     RECT  51.725 33.168 51.756 33.192 ;
     RECT  51.725 33.192 51.804 33.264 ;
     RECT  51.725 33.264 51.756 33.288 ;
     RECT  51.725 33.288 51.804 33.36 ;
     RECT  51.725 33.36 51.756 33.384 ;
     RECT  51.725 33.384 51.804 33.456 ;
     RECT  51.725 33.456 51.756 33.48 ;
     RECT  51.725 33.48 51.804 33.552 ;
     RECT  51.725 33.552 51.756 33.576 ;
     RECT  51.725 33.576 51.804 33.648 ;
     RECT  51.725 33.648 51.756 33.672 ;
     RECT  51.725 33.672 51.804 33.744 ;
     RECT  51.725 33.744 51.756 33.768 ;
     RECT  51.725 33.768 51.804 33.84 ;
     RECT  51.725 33.84 51.756 33.864 ;
     RECT  51.725 33.864 51.804 33.936 ;
     RECT  51.725 33.936 51.756 33.96 ;
     RECT  51.725 33.96 51.804 34.032 ;
     RECT  51.725 34.032 51.756 34.056 ;
     RECT  51.725 34.056 51.804 34.128 ;
     RECT  51.725 34.128 51.756 34.152 ;
     RECT  51.725 34.152 51.804 34.224 ;
     RECT  51.725 34.224 51.756 34.248 ;
     RECT  51.725 34.248 51.804 34.32 ;
     RECT  51.725 34.32 51.756 34.344 ;
     RECT  51.725 34.344 51.804 34.416 ;
     RECT  51.725 34.416 51.756 34.44 ;
     RECT  51.725 34.44 51.804 34.512 ;
     RECT  51.725 34.512 51.756 34.536 ;
     RECT  51.725 34.536 51.804 34.608 ;
     RECT  51.725 34.608 51.756 34.632 ;
     RECT  51.725 34.632 51.804 34.704 ;
     RECT  51.725 34.704 51.756 34.728 ;
     RECT  51.725 34.728 51.804 34.8 ;
     RECT  51.725 34.8 51.756 34.824 ;
     RECT  51.725 34.824 51.804 34.896 ;
     RECT  51.725 34.896 51.756 34.92 ;
     RECT  51.725 34.92 51.804 34.992 ;
     RECT  51.725 34.992 51.756 35.016 ;
     RECT  51.725 35.016 51.804 35.088 ;
     RECT  51.725 35.088 51.756 35.112 ;
     RECT  51.725 35.112 51.804 35.184 ;
     RECT  51.725 35.184 51.756 35.208 ;
    LAYER M5 ;
     RECT  2.4 2.137 2.52 2.151 ;
     RECT  5.1 2.137 5.22 2.151 ;
     RECT  7.8 2.137 7.92 2.151 ;
     RECT  10.5 2.137 10.62 2.151 ;
     RECT  13.2 2.137 13.32 2.151 ;
     RECT  15.9 2.137 16.02 2.151 ;
     RECT  18.6 2.137 18.72 2.151 ;
     RECT  21.3 2.137 21.42 2.151 ;
     RECT  24 2.137 24.12 2.151 ;
     RECT  26.7 2.137 26.82 2.151 ;
     RECT  29.4 2.137 29.52 2.151 ;
     RECT  32.1 2.137 32.22 2.151 ;
     RECT  34.8 2.137 34.92 2.151 ;
     RECT  37.5 2.137 37.62 2.151 ;
     RECT  40.2 2.137 40.32 2.151 ;
     RECT  42.9 2.137 43.02 2.151 ;
     RECT  45.6 2.137 45.72 2.151 ;
     RECT  48.3 2.137 48.42 2.151 ;
     RECT  7.8 2.151 8.112 2.197 ;
     RECT  13.2 2.151 13.512 2.245 ;
     RECT  18.6 2.151 18.912 2.245 ;
     RECT  40.2 2.151 40.512 2.821 ;
     RECT  24 2.151 24.312 3.397 ;
     RECT  9.36 2.245 9.384 3.443 ;
     RECT  39.264 2.821 40.512 3.443 ;
     RECT  10.5 2.151 10.812 3.589 ;
     RECT  28.368 2.629 28.392 3.829 ;
     RECT  29.4 2.151 29.712 3.829 ;
     RECT  34.8 2.151 35.112 3.829 ;
     RECT  21.3 2.151 21.612 3.925 ;
     RECT  44.448 2.245 44.472 3.971 ;
     RECT  7.68 2.197 8.112 4.019 ;
     RECT  28.368 3.829 29.712 4.019 ;
     RECT  12.528 2.245 13.512 4.115 ;
     RECT  42.9 2.151 43.212 4.213 ;
     RECT  23.28 3.397 24.312 4.453 ;
     RECT  5.1 2.151 5.412 4.501 ;
     RECT  30.72 3.541 30.744 4.547 ;
     RECT  23.28 4.453 24.408 4.595 ;
     RECT  32.1 2.151 32.412 4.741 ;
     RECT  23.328 4.595 24.408 4.787 ;
     RECT  21.3 3.925 22.104 5.027 ;
     RECT  15.9 2.151 16.212 5.029 ;
     RECT  4.128 4.501 5.412 5.077 ;
     RECT  13.2 4.115 13.512 5.077 ;
     RECT  37.5 2.151 37.812 5.077 ;
     RECT  45.6 2.151 45.912 5.077 ;
     RECT  9.648 3.589 10.812 5.171 ;
     RECT  33.648 3.877 33.672 5.171 ;
     RECT  12.816 5.077 13.512 5.173 ;
     RECT  34.8 3.829 35.304 5.173 ;
     RECT  12.528 5.173 13.512 5.221 ;
     RECT  45.6 5.077 46.728 5.221 ;
     RECT  31.968 4.741 32.412 5.317 ;
     RECT  10.5 5.171 10.812 5.365 ;
     RECT  42.9 4.213 44.088 5.365 ;
     RECT  21.3 5.027 21.612 5.653 ;
     RECT  4.128 5.077 6.36 5.699 ;
     RECT  39.312 3.443 40.512 5.699 ;
     RECT  45.6 5.221 47.016 5.747 ;
     RECT  17.856 2.245 18.912 5.987 ;
     RECT  23.328 4.787 24.312 5.987 ;
     RECT  34.8 5.173 36.264 6.035 ;
     RECT  29.28 4.019 29.712 6.085 ;
     RECT  21.072 5.653 21.612 6.229 ;
     RECT  10.5 5.365 10.92 6.323 ;
     RECT  15.792 5.029 16.212 6.323 ;
     RECT  18.288 5.987 18.912 6.323 ;
     RECT  31.968 5.317 33.24 6.323 ;
     RECT  5.1 5.699 6.36 6.661 ;
     RECT  2.4 2.151 2.712 6.805 ;
     RECT  15.9 6.323 16.212 6.805 ;
     RECT  24 5.987 24.312 6.805 ;
     RECT  45.6 5.747 46.536 6.805 ;
     RECT  4.992 6.661 6.36 6.851 ;
     RECT  29.232 6.085 29.712 6.899 ;
     RECT  37.5 5.077 37.944 6.899 ;
     RECT  42.192 5.365 44.088 6.899 ;
     RECT  22.848 6.997 22.872 7.093 ;
     RECT  10.5 6.323 10.812 7.333 ;
     RECT  22.848 7.093 22.92 7.381 ;
     RECT  24 6.805 25.272 7.381 ;
     RECT  26.7 2.151 27.012 7.381 ;
     RECT  32.1 6.323 33.24 7.427 ;
     RECT  22.848 7.381 25.272 7.523 ;
     RECT  45.072 6.805 46.536 7.619 ;
     RECT  42.192 6.899 43.212 7.621 ;
     RECT  37.5 6.899 37.812 7.909 ;
     RECT  41.664 7.621 43.212 7.909 ;
     RECT  10.5 7.333 11.256 7.957 ;
     RECT  12.384 5.221 13.512 7.957 ;
     RECT  29.28 6.899 29.712 7.957 ;
     RECT  2.4 6.805 2.808 8.003 ;
     RECT  10.5 7.957 13.512 8.245 ;
     RECT  3.936 7.381 3.96 8.437 ;
     RECT  4.992 6.851 5.688 8.437 ;
     RECT  3.936 8.437 5.688 8.483 ;
     RECT  15.9 6.805 16.632 8.485 ;
     RECT  18.6 6.323 18.912 8.485 ;
     RECT  45.504 7.619 46.536 8.485 ;
     RECT  48.3 2.151 48.612 8.485 ;
     RECT  22.896 7.523 25.272 8.579 ;
     RECT  10.5 8.245 13.608 8.627 ;
     RECT  26.7 7.381 27.48 8.723 ;
     RECT  34.8 6.035 35.304 8.725 ;
     RECT  37.104 7.909 37.812 8.725 ;
     RECT  34.8 8.725 37.812 8.771 ;
     RECT  45.504 8.485 48.612 9.251 ;
     RECT  15.9 8.485 16.68 9.253 ;
     RECT  18 8.485 18.912 9.253 ;
     RECT  7.8 4.019 8.112 9.397 ;
     RECT  32.1 7.427 32.412 9.397 ;
     RECT  20.448 6.229 21.612 9.685 ;
     RECT  22.896 8.579 24.504 9.731 ;
     RECT  34.8 8.771 36.216 9.779 ;
     RECT  41.616 7.909 43.212 9.779 ;
     RECT  20.4 9.685 21.612 9.923 ;
     RECT  4.224 8.483 5.688 9.971 ;
     RECT  45.504 9.251 46.536 10.021 ;
     RECT  12.384 8.627 13.608 10.163 ;
     RECT  38.784 9.109 38.808 10.307 ;
     RECT  45.072 10.021 46.536 10.307 ;
     RECT  12.816 10.163 13.608 10.355 ;
     RECT  29.28 7.957 29.88 10.355 ;
     RECT  21.3 9.923 21.612 10.357 ;
     RECT  32.1 9.397 33.096 10.499 ;
     RECT  34.8 9.779 35.304 10.741 ;
     RECT  4.992 9.971 5.688 10.789 ;
     RECT  7.008 9.397 8.112 10.789 ;
     RECT  45.072 10.307 45.912 10.883 ;
     RECT  21.3 10.357 21.72 11.173 ;
     RECT  23.616 9.731 24.504 11.173 ;
     RECT  37.5 8.771 37.812 11.221 ;
     RECT  21.168 11.173 21.72 11.269 ;
     RECT  10.5 8.627 11.256 11.317 ;
     RECT  12.816 10.355 13.512 11.317 ;
     RECT  34.8 10.741 35.4 11.411 ;
     RECT  37.5 11.221 38.232 11.413 ;
     RECT  15.9 9.253 18.912 11.459 ;
     RECT  12.672 11.317 13.512 11.461 ;
     RECT  29.4 10.355 29.88 11.749 ;
     RECT  23.328 11.173 24.504 11.797 ;
     RECT  9.936 11.317 11.256 11.941 ;
     RECT  4.992 10.789 8.232 11.987 ;
     RECT  9.936 11.941 11.688 12.083 ;
     RECT  32.1 10.499 32.76 12.227 ;
     RECT  10.5 12.083 11.688 12.229 ;
     RECT  12.672 11.461 13.608 12.229 ;
     RECT  17.952 11.459 18.912 12.275 ;
     RECT  40.2 5.699 40.512 12.325 ;
     RECT  1.248 12.229 1.272 12.371 ;
     RECT  37.392 11.413 38.232 12.515 ;
     RECT  4.992 11.987 8.112 12.563 ;
     RECT  0.144 12.517 0.168 12.803 ;
     RECT  21.168 11.269 21.864 12.805 ;
     RECT  21.168 12.805 21.912 12.901 ;
     RECT  23.328 11.797 25.128 12.901 ;
     RECT  28.512 11.749 29.88 13.045 ;
     RECT  4.992 12.563 6.36 13.093 ;
     RECT  32.1 12.227 32.412 13.093 ;
     RECT  37.5 12.515 38.232 13.093 ;
     RECT  21.168 12.901 25.128 13.139 ;
     RECT  28.512 13.045 29.928 13.139 ;
     RECT  24 13.139 25.128 13.331 ;
     RECT  4.896 13.093 6.36 13.715 ;
     RECT  7.8 12.563 8.112 13.861 ;
     RECT  33.792 11.317 33.816 13.957 ;
     RECT  28.992 13.139 29.928 14.003 ;
     RECT  33.6 13.957 33.816 14.003 ;
     RECT  10.5 12.229 13.608 14.533 ;
     RECT  37.5 13.093 38.472 14.773 ;
     RECT  33.6 14.003 33.624 14.819 ;
     RECT  44.448 13.045 44.472 14.867 ;
     RECT  45.6 10.883 45.912 15.061 ;
     RECT  46.944 13.861 46.968 15.061 ;
     RECT  15.9 11.459 16.212 15.205 ;
     RECT  21.168 13.139 22.632 15.349 ;
     RECT  24 13.331 24.312 15.349 ;
     RECT  29.4 14.003 29.928 15.349 ;
     RECT  18 12.275 18.912 15.491 ;
     RECT  15.9 15.205 16.344 15.493 ;
     RECT  37.056 14.773 38.472 15.493 ;
     RECT  31.968 13.093 32.412 15.541 ;
     RECT  10.5 14.533 14.088 15.637 ;
     RECT  31.872 15.541 32.412 15.877 ;
     RECT  45.6 15.061 46.968 15.971 ;
     RECT  28.944 15.349 29.928 16.019 ;
     RECT  36.288 15.493 38.472 16.019 ;
     RECT  9.648 15.637 14.088 16.021 ;
     RECT  15.9 15.493 17.16 16.021 ;
     RECT  29.4 16.019 29.928 16.115 ;
     RECT  9.648 16.021 17.16 16.403 ;
     RECT  2.4 8.003 2.712 16.405 ;
     RECT  34.8 11.411 35.112 16.405 ;
     RECT  36.288 16.019 36.312 16.405 ;
     RECT  18.288 15.491 18.912 16.501 ;
     RECT  4.896 13.715 5.412 17.029 ;
     RECT  37.5 16.019 38.472 17.029 ;
     RECT  39.552 12.325 40.512 17.029 ;
     RECT  18.192 16.501 18.912 17.077 ;
     RECT  45.6 15.971 46.008 17.123 ;
     RECT  7.344 13.861 8.112 17.365 ;
     RECT  31.824 15.877 32.412 17.461 ;
     RECT  34.8 16.405 36.312 17.507 ;
     RECT  21.168 15.349 24.312 17.557 ;
     RECT  41.904 9.779 43.212 17.603 ;
     RECT  26.7 8.723 27.012 17.605 ;
     RECT  29.4 16.115 29.712 17.605 ;
     RECT  7.344 17.365 8.52 17.651 ;
     RECT  45.6 17.123 45.912 18.037 ;
     RECT  4.848 17.029 5.412 18.181 ;
     RECT  21.168 17.557 24.552 18.181 ;
     RECT  31.824 17.461 33.096 18.275 ;
     RECT  14.928 16.403 17.16 18.517 ;
     RECT  18.192 17.077 19.368 18.517 ;
     RECT  2.4 16.405 2.856 18.563 ;
     RECT  21.168 18.181 24.648 18.659 ;
     RECT  14.928 18.517 19.464 18.707 ;
     RECT  28.656 17.605 29.712 18.707 ;
     RECT  21.168 18.659 22.68 18.709 ;
     RECT  26.7 17.605 27.144 18.755 ;
     RECT  26.7 18.755 27.012 18.757 ;
     RECT  34.8 17.507 35.112 18.757 ;
     RECT  36.288 17.507 36.312 18.757 ;
     RECT  37.5 17.029 40.512 18.803 ;
     RECT  39.6 18.803 40.512 18.851 ;
     RECT  15.9 18.707 19.464 18.995 ;
     RECT  24 18.659 24.648 19.045 ;
     RECT  25.872 18.757 27.012 19.045 ;
     RECT  4.848 18.181 5.544 19.091 ;
     RECT  45.024 18.037 45.912 19.235 ;
     RECT  21.072 18.709 22.68 19.333 ;
     RECT  18.6 18.995 19.464 19.523 ;
     RECT  31.92 18.275 33.096 19.669 ;
     RECT  41.904 17.603 41.928 19.765 ;
     RECT  42.9 17.603 43.212 19.765 ;
     RECT  37.5 18.803 38.472 19.957 ;
     RECT  20.928 19.333 22.68 20.147 ;
     RECT  41.904 19.765 43.212 20.147 ;
     RECT  24 19.045 27.012 20.339 ;
     RECT  7.8 17.651 8.112 20.389 ;
     RECT  31.92 19.669 33.144 20.437 ;
     RECT  4.848 19.091 5.412 20.485 ;
     RECT  9.648 16.403 13.656 20.819 ;
     RECT  40.2 18.851 40.512 21.061 ;
     RECT  29.28 18.707 29.712 21.109 ;
     RECT  45.6 19.235 45.912 21.301 ;
     RECT  10.5 20.819 13.656 21.395 ;
     RECT  34.8 18.757 36.312 21.395 ;
     RECT  37.5 19.957 39.096 21.395 ;
     RECT  18.6 19.523 18.912 21.445 ;
     RECT  24 20.339 25.128 21.493 ;
     RECT  37.5 21.395 38.472 21.635 ;
     RECT  24 21.493 25.56 21.637 ;
     RECT  40.2 21.061 40.632 21.637 ;
     RECT  41.904 20.147 41.928 21.637 ;
     RECT  42.9 20.147 43.212 21.637 ;
     RECT  34.8 21.395 35.928 21.683 ;
     RECT  7.488 20.389 8.112 21.731 ;
     RECT  34.8 21.683 35.112 21.733 ;
     RECT  10.5 21.395 13.512 22.069 ;
     RECT  15.9 18.995 17.16 22.165 ;
     RECT  18.6 21.445 19.656 22.165 ;
     RECT  31.92 20.437 33.192 22.165 ;
     RECT  34.464 21.733 35.112 22.165 ;
     RECT  42.9 21.637 44.04 22.259 ;
     RECT  15.9 22.165 19.656 22.451 ;
     RECT  37.5 21.635 38.376 22.499 ;
     RECT  45.504 21.301 45.912 22.499 ;
     RECT  40.2 21.637 41.928 22.739 ;
     RECT  42.9 22.259 43.896 22.739 ;
     RECT  10.224 22.069 13.512 22.835 ;
     RECT  31.92 22.165 35.112 22.835 ;
     RECT  4.512 20.485 5.412 22.931 ;
     RECT  29.184 21.109 29.712 22.931 ;
     RECT  32.1 22.835 35.112 23.027 ;
     RECT  45.6 22.499 45.912 23.029 ;
     RECT  2.4 18.563 2.712 23.125 ;
     RECT  45.6 23.029 46.728 23.171 ;
     RECT  41.52 22.739 41.928 23.411 ;
     RECT  10.5 22.835 13.512 23.413 ;
     RECT  37.5 22.499 37.992 23.557 ;
     RECT  23.664 21.637 25.56 23.603 ;
     RECT  37.5 23.557 38.856 23.699 ;
     RECT  26.7 20.339 27.012 23.701 ;
     RECT  34.224 23.027 35.112 23.797 ;
     RECT  41.568 23.411 41.928 23.939 ;
     RECT  20.928 20.147 21.912 23.941 ;
     RECT  34.224 23.797 35.352 23.987 ;
     RECT  37.5 23.699 37.992 24.181 ;
     RECT  10.5 23.413 14.328 24.371 ;
     RECT  18.048 22.451 19.656 24.469 ;
     RECT  32.1 23.027 33.144 24.469 ;
     RECT  34.224 23.987 35.112 24.469 ;
     RECT  32.1 24.469 35.112 24.515 ;
     RECT  2.4 23.125 2.808 24.563 ;
     RECT  36.912 24.181 37.992 24.563 ;
     RECT  26.7 23.701 27.96 24.707 ;
     RECT  17.664 24.469 19.656 25.139 ;
     RECT  36.912 24.563 37.812 25.139 ;
     RECT  17.664 25.139 19.56 25.187 ;
     RECT  32.1 24.515 32.412 25.189 ;
     RECT  10.5 24.371 13.608 25.427 ;
     RECT  4.992 22.931 5.412 25.621 ;
     RECT  41.904 23.939 41.928 26.005 ;
     RECT  42.9 22.739 43.212 26.005 ;
     RECT  7.584 21.731 8.112 26.053 ;
     RECT  4.512 25.621 5.412 26.099 ;
     RECT  6.384 24.469 6.408 26.099 ;
     RECT  7.584 26.053 8.664 26.197 ;
     RECT  4.992 26.099 5.412 26.243 ;
     RECT  20.928 23.941 22.2 26.243 ;
     RECT  13.2 25.427 13.608 26.291 ;
     RECT  41.904 26.005 43.212 26.629 ;
     RECT  15.9 22.451 16.212 26.725 ;
     RECT  17.232 26.533 17.256 26.725 ;
     RECT  26.7 24.707 27.012 26.725 ;
     RECT  31.968 25.189 32.412 26.819 ;
     RECT  10.5 25.427 12.024 27.155 ;
     RECT  20.928 26.243 21.864 27.203 ;
     RECT  15.9 26.725 17.256 27.205 ;
     RECT  18.6 25.187 19.56 27.205 ;
     RECT  7.488 26.197 8.664 27.301 ;
     RECT  45.6 23.171 45.912 27.301 ;
     RECT  15.36 27.205 17.256 27.397 ;
     RECT  14.784 27.397 17.256 27.539 ;
     RECT  41.856 26.629 43.212 27.587 ;
     RECT  15.36 27.539 17.256 27.635 ;
     RECT  33.504 24.515 35.112 27.637 ;
     RECT  7.488 27.301 8.952 27.781 ;
     RECT  2.4 24.563 2.712 27.829 ;
     RECT  37.5 25.139 37.812 27.925 ;
     RECT  24 23.603 25.56 27.971 ;
     RECT  10.5 27.155 11.736 28.019 ;
     RECT  40.2 22.739 40.512 28.165 ;
     RECT  29.4 22.931 29.712 28.261 ;
     RECT  33.504 27.637 35.208 28.405 ;
     RECT  7.488 27.781 9.096 28.451 ;
     RECT  18.6 27.205 19.896 28.451 ;
     RECT  44.448 28.357 44.472 28.453 ;
     RECT  45.6 27.301 46.152 28.453 ;
     RECT  33.504 28.405 36.12 28.499 ;
     RECT  18.6 28.451 19.56 28.501 ;
     RECT  2.4 27.829 3.432 28.643 ;
     RECT  44.448 28.453 46.152 28.787 ;
     RECT  20.928 27.203 21.612 28.789 ;
     RECT  32.1 26.819 32.412 28.789 ;
     RECT  33.504 28.499 35.112 28.789 ;
     RECT  26.592 26.725 27.624 28.835 ;
     RECT  7.8 28.451 9.096 28.931 ;
     RECT  32.1 28.789 35.112 29.075 ;
     RECT  39.888 28.165 40.512 29.075 ;
     RECT  7.8 28.931 8.952 29.123 ;
     RECT  44.448 28.787 45.912 29.171 ;
     RECT  26.592 28.835 27.384 29.363 ;
     RECT  36.096 28.499 36.12 29.459 ;
     RECT  37.152 27.925 37.812 29.459 ;
     RECT  15.36 27.635 16.212 29.653 ;
     RECT  17.232 27.635 17.256 29.653 ;
     RECT  40.2 29.075 40.512 29.653 ;
     RECT  18.432 28.501 19.56 29.699 ;
     RECT  30.912 27.301 30.936 29.699 ;
     RECT  48.3 9.251 48.612 30.133 ;
     RECT  7.8 29.123 8.112 30.181 ;
     RECT  29.088 28.261 29.712 30.275 ;
     RECT  15.36 29.653 17.256 30.323 ;
     RECT  33.504 29.075 35.112 30.371 ;
     RECT  37.5 29.459 37.812 30.469 ;
     RECT  36.432 29.941 36.456 30.611 ;
     RECT  40.2 29.653 40.872 30.611 ;
     RECT  18.6 29.699 19.56 30.661 ;
     RECT  24 27.971 24.648 30.661 ;
     RECT  40.2 30.611 40.512 30.709 ;
     RECT  47.952 30.133 48.612 30.899 ;
     RECT  10.5 28.019 11.4 31.237 ;
     RECT  26.592 29.363 27.012 31.285 ;
     RECT  0.192 31.189 0.216 31.427 ;
     RECT  37.5 30.469 38.184 31.427 ;
     RECT  10.368 31.237 11.4 31.475 ;
     RECT  2.4 28.643 2.712 31.765 ;
     RECT  13.2 26.291 13.512 31.765 ;
     RECT  7.2 30.181 8.112 31.859 ;
     RECT  7.392 31.859 8.112 31.861 ;
     RECT  48.192 30.899 48.612 31.907 ;
     RECT  32.1 29.075 32.412 31.909 ;
     RECT  2.304 31.765 2.712 31.955 ;
     RECT  5.1 26.243 5.412 32.053 ;
     RECT  26.496 31.285 27.012 32.053 ;
     RECT  31.968 31.909 32.412 32.197 ;
     RECT  4.224 32.053 5.412 32.293 ;
     RECT  7.392 31.861 8.472 32.339 ;
     RECT  23.136 30.661 24.648 32.437 ;
     RECT  41.856 27.587 41.88 32.437 ;
     RECT  42.9 27.587 43.212 32.437 ;
     RECT  18.48 30.661 19.56 32.531 ;
     RECT  39.6 30.709 40.512 32.723 ;
     RECT  13.2 31.765 13.656 32.821 ;
     RECT  12.528 32.821 13.656 32.867 ;
     RECT  10.5 31.475 11.4 32.917 ;
     RECT  12.528 32.867 13.512 32.917 ;
     RECT  44.88 29.171 45.912 32.965 ;
     RECT  18.48 32.531 18.912 33.013 ;
     RECT  22.848 32.437 24.648 33.013 ;
     RECT  31.344 32.197 32.412 33.013 ;
     RECT  4.224 32.293 5.544 33.059 ;
     RECT  31.248 33.013 32.412 33.157 ;
     RECT  31.248 33.157 33.144 33.491 ;
     RECT  34.224 30.371 35.112 33.589 ;
     RECT  44.88 32.965 46.152 33.731 ;
     RECT  26.496 32.053 27.96 33.827 ;
     RECT  45.264 33.731 46.152 34.115 ;
     RECT  34.224 33.589 35.208 34.259 ;
     RECT  10.5 32.917 13.512 34.355 ;
     RECT  36.432 33.445 36.456 34.405 ;
     RECT  37.5 31.427 37.812 34.405 ;
     RECT  7.8 32.339 8.472 34.453 ;
     RECT  40.2 32.723 40.512 34.501 ;
     RECT  0.144 34.405 0.168 34.691 ;
     RECT  36.432 34.405 37.812 34.691 ;
     RECT  22.8 33.013 24.648 34.693 ;
     RECT  26.496 33.827 27.012 34.739 ;
     RECT  22.656 34.693 24.648 34.883 ;
     RECT  13.2 34.355 13.512 34.885 ;
     RECT  20.784 28.789 21.612 34.981 ;
     RECT  22.656 34.883 22.824 34.981 ;
     RECT  26.592 34.739 27.012 34.981 ;
     RECT  31.248 33.491 32.904 35.171 ;
     RECT  18.24 33.013 18.912 35.219 ;
     RECT  7.056 34.453 8.472 35.317 ;
     RECT  31.248 35.171 32.412 35.363 ;
     RECT  41.856 32.437 43.212 35.363 ;
     RECT  40.032 34.501 40.512 35.509 ;
     RECT  7.056 35.317 8.904 35.747 ;
     RECT  10.5 34.355 11.88 35.747 ;
     RECT  26.592 34.981 27.144 35.843 ;
     RECT  5.1 33.059 5.544 36.035 ;
     RECT  13.2 34.885 14.088 36.085 ;
     RECT  18.288 35.219 18.912 36.515 ;
     RECT  39.312 35.509 40.512 36.515 ;
     RECT  12.768 36.085 14.088 36.563 ;
     RECT  20.784 34.981 22.824 36.899 ;
     RECT  36.912 34.691 37.812 36.901 ;
     RECT  7.8 35.747 8.904 36.997 ;
     RECT  29.4 30.275 29.712 36.997 ;
     RECT  42.9 35.363 43.212 36.997 ;
     RECT  48.3 31.907 48.612 36.997 ;
     RECT  20.784 36.899 21.912 37.091 ;
     RECT  10.5 35.747 11.688 37.573 ;
     RECT  12.768 36.563 13.512 37.573 ;
     RECT  15.36 30.323 16.212 37.573 ;
     RECT  26.592 35.843 27.012 37.573 ;
     RECT  47.856 36.997 48.612 37.573 ;
     RECT  42.9 36.997 43.944 37.619 ;
     RECT  5.1 36.035 5.412 37.621 ;
     RECT  6.864 36.997 8.904 37.667 ;
     RECT  34.8 34.259 35.208 37.667 ;
     RECT  6.864 37.667 8.712 37.715 ;
     RECT  31.968 35.363 32.412 38.005 ;
     RECT  18.6 36.515 18.912 38.149 ;
     RECT  33.6 37.429 33.624 38.195 ;
     RECT  29.28 36.997 29.712 38.243 ;
     RECT  4.752 37.621 5.412 38.387 ;
     RECT  29.4 38.243 29.712 38.533 ;
     RECT  15.024 37.573 16.212 38.581 ;
     RECT  17.232 30.323 17.256 38.581 ;
     RECT  36.912 36.901 37.944 38.581 ;
     RECT  10.5 37.573 13.512 38.723 ;
     RECT  31.344 38.005 32.412 38.725 ;
     RECT  36.192 38.581 37.944 38.725 ;
     RECT  40.2 36.515 40.512 38.725 ;
     RECT  20.88 37.091 21.912 38.819 ;
     RECT  6.864 37.715 8.112 38.963 ;
     RECT  15.024 38.581 17.256 38.963 ;
     RECT  29.4 38.533 29.976 39.107 ;
     RECT  42.9 37.619 43.212 39.109 ;
     RECT  39.984 38.725 40.512 39.299 ;
     RECT  47.328 37.573 48.612 39.347 ;
     RECT  5.1 38.387 5.412 39.493 ;
     RECT  31.344 38.725 33.336 39.541 ;
     RECT  34.8 37.667 35.112 39.637 ;
     RECT  36.192 38.725 38.04 39.637 ;
     RECT  20.88 38.819 21.612 39.877 ;
     RECT  34.56 39.637 38.04 39.923 ;
     RECT  26.592 37.573 27.816 40.165 ;
     RECT  7.8 38.963 8.112 40.309 ;
     RECT  29.4 39.107 29.832 40.355 ;
     RECT  31.296 39.541 33.336 40.499 ;
     RECT  34.56 39.923 35.928 40.499 ;
     RECT  5.1 39.493 5.736 40.595 ;
     RECT  15.36 38.963 17.256 40.595 ;
     RECT  41.856 35.363 41.88 40.595 ;
     RECT  18.6 38.149 19.272 40.597 ;
     RECT  34.56 40.499 35.304 40.643 ;
     RECT  45.264 34.115 45.912 40.643 ;
     RECT  20.88 39.877 22.248 40.741 ;
     RECT  42.9 39.109 43.368 40.835 ;
     RECT  20.544 40.741 22.248 41.075 ;
     RECT  25.968 40.165 27.816 41.411 ;
     RECT  48.3 39.347 48.612 41.509 ;
     RECT  7.392 40.309 8.112 41.557 ;
     RECT  7.392 41.557 9.096 41.651 ;
     RECT  24 34.883 24.648 41.747 ;
     RECT  20.544 41.075 21.72 42.035 ;
     RECT  17.232 40.595 17.256 42.085 ;
     RECT  18.6 40.597 19.32 42.085 ;
     RECT  20.88 42.035 21.72 42.133 ;
     RECT  5.1 40.595 5.412 42.181 ;
     RECT  10.5 38.723 11.688 42.181 ;
     RECT  12.768 38.723 13.512 42.181 ;
     RECT  15.36 40.595 16.212 42.181 ;
     RECT  17.232 42.085 19.32 42.181 ;
     RECT  10.5 42.181 13.512 42.227 ;
     RECT  47.904 41.509 48.612 42.227 ;
     RECT  29.4 40.355 29.712 42.229 ;
     RECT  31.296 40.499 32.412 42.419 ;
     RECT  7.8 41.651 9.096 42.467 ;
     RECT  25.968 41.411 27.48 42.467 ;
     RECT  10.5 42.227 10.92 42.661 ;
     RECT  29.088 42.229 29.712 42.709 ;
     RECT  11.952 42.227 13.512 42.755 ;
     RECT  15.36 42.181 19.32 42.803 ;
     RECT  29.088 42.709 30.696 42.899 ;
     RECT  24 41.747 24.312 43.285 ;
     RECT  13.056 42.755 13.512 43.331 ;
     RECT  15.36 42.803 18.912 43.331 ;
     RECT  10.32 42.661 10.92 43.379 ;
     RECT  15.36 43.331 17.256 43.379 ;
     RECT  20.88 42.133 22.248 43.379 ;
     RECT  31.968 42.419 32.412 43.573 ;
     RECT  34.8 40.643 35.304 43.621 ;
     RECT  3.984 42.469 4.008 43.763 ;
     RECT  24 43.285 24.552 43.765 ;
     RECT  25.968 42.467 27.012 43.765 ;
     RECT  10.32 43.379 10.812 43.861 ;
     RECT  13.2 43.331 13.512 43.909 ;
     RECT  29.4 42.899 30.696 44.245 ;
     RECT  31.968 43.573 33 44.245 ;
     RECT  15.36 43.379 16.212 44.341 ;
     RECT  17.232 43.379 17.256 44.341 ;
     RECT  24 43.765 27.012 44.437 ;
     RECT  11.952 42.755 11.976 44.483 ;
     RECT  20.88 43.379 22.2 44.483 ;
     RECT  29.4 44.245 33 44.483 ;
     RECT  36.912 39.923 38.04 44.483 ;
     RECT  18.48 43.331 18.912 44.485 ;
     RECT  29.4 44.483 32.412 44.531 ;
     RECT  23.472 44.437 27.012 44.579 ;
     RECT  37.5 44.483 38.04 44.675 ;
     RECT  5.1 42.181 5.64 44.725 ;
     RECT  25.68 44.579 27.012 44.965 ;
     RECT  42.9 40.835 43.212 44.965 ;
     RECT  45.36 40.643 45.912 44.965 ;
     RECT  18.48 44.485 19.8 45.011 ;
     RECT  30.768 44.531 32.412 45.011 ;
     RECT  21.168 44.483 22.2 45.157 ;
     RECT  23.472 44.579 24.312 45.157 ;
     RECT  7.8 42.467 8.232 45.491 ;
     RECT  40.2 39.299 40.512 45.541 ;
     RECT  4.896 44.725 5.64 45.635 ;
     RECT  5.1 45.635 5.64 45.683 ;
     RECT  21.168 45.157 24.312 45.731 ;
     RECT  30.768 45.011 30.792 45.731 ;
     RECT  13.2 43.909 14.232 45.923 ;
     RECT  23.04 45.731 24.312 45.971 ;
     RECT  42.9 44.965 43.32 46.021 ;
     RECT  42.768 46.021 43.32 46.067 ;
     RECT  18.48 45.011 18.912 46.069 ;
     RECT  5.1 45.683 5.544 46.211 ;
     RECT  9.456 43.861 10.812 46.211 ;
     RECT  45.36 44.965 46.2 46.211 ;
     RECT  18.48 46.069 19.848 46.259 ;
     RECT  45.6 46.211 46.2 46.309 ;
     RECT  29.4 44.531 29.712 46.405 ;
     RECT  25.68 44.965 27.384 46.499 ;
     RECT  32.1 45.011 32.412 46.645 ;
     RECT  39.888 45.541 40.512 46.787 ;
     RECT  31.968 46.645 32.412 46.837 ;
     RECT  31.968 46.837 33.048 47.555 ;
     RECT  25.68 46.499 27.012 47.699 ;
     RECT  48.3 42.227 48.612 47.701 ;
     RECT  18.6 46.259 19.848 47.845 ;
     RECT  21.168 45.731 21.612 47.845 ;
     RECT  18.6 47.845 21.612 47.891 ;
     RECT  31.968 47.555 32.412 47.939 ;
     RECT  45.6 46.309 46.44 47.939 ;
     RECT  42.768 46.067 43.212 47.989 ;
     RECT  34.8 43.621 35.784 48.133 ;
     RECT  37.5 44.675 37.812 48.133 ;
     RECT  9.552 46.211 10.812 48.179 ;
     RECT  29.28 46.405 29.712 48.179 ;
     RECT  42.768 47.989 44.04 48.227 ;
     RECT  2.4 31.955 2.712 48.421 ;
     RECT  5.1 46.211 5.412 48.421 ;
     RECT  7.8 45.491 8.112 48.421 ;
     RECT  15.36 44.341 17.256 48.515 ;
     RECT  34.8 48.133 37.812 48.707 ;
     RECT  2.4 48.421 2.904 48.995 ;
     RECT  5.1 48.421 5.544 49.043 ;
     RECT  7.68 48.421 8.112 49.043 ;
     RECT  34.8 48.707 35.784 49.043 ;
     RECT  47.856 47.701 48.612 49.043 ;
     RECT  42.9 48.227 44.04 49.331 ;
     RECT  20.304 47.891 21.612 49.475 ;
     RECT  25.824 47.699 27.012 49.475 ;
     RECT  21.168 49.475 21.612 49.523 ;
     RECT  2.4 48.995 2.712 49.689 ;
     RECT  5.1 49.043 5.412 49.689 ;
     RECT  7.8 49.043 8.112 49.689 ;
     RECT  10.5 48.179 10.812 49.689 ;
     RECT  13.2 45.923 13.512 49.689 ;
     RECT  15.36 48.515 16.212 49.689 ;
     RECT  18.6 47.891 18.912 49.689 ;
     RECT  21.3 49.523 21.612 49.689 ;
     RECT  24 45.971 24.312 49.689 ;
     RECT  26.7 49.475 27.012 49.689 ;
     RECT  29.4 48.179 29.712 49.689 ;
     RECT  32.1 47.939 32.412 49.689 ;
     RECT  34.8 49.043 35.112 49.689 ;
     RECT  37.5 48.707 37.812 49.689 ;
     RECT  40.2 46.787 40.512 49.689 ;
     RECT  42.9 49.331 43.212 49.689 ;
     RECT  45.6 47.939 45.912 49.689 ;
     RECT  48.3 49.043 48.612 49.689 ;
     RECT  2.4 49.689 2.52 49.703 ;
     RECT  5.1 49.689 5.22 49.703 ;
     RECT  7.8 49.689 7.92 49.703 ;
     RECT  10.5 49.689 10.62 49.703 ;
     RECT  13.2 49.689 13.32 49.703 ;
     RECT  15.36 49.689 16.02 49.703 ;
     RECT  18.6 49.689 18.72 49.703 ;
     RECT  21.3 49.689 21.42 49.703 ;
     RECT  24 49.689 24.12 49.703 ;
     RECT  26.7 49.689 26.82 49.703 ;
     RECT  29.4 49.689 29.52 49.703 ;
     RECT  32.1 49.689 32.22 49.703 ;
     RECT  34.8 49.689 34.92 49.703 ;
     RECT  37.5 49.689 37.62 49.703 ;
     RECT  40.2 49.689 40.32 49.703 ;
     RECT  42.9 49.689 43.02 49.703 ;
     RECT  45.6 49.689 45.72 49.703 ;
     RECT  48.3 49.689 48.42 49.703 ;
     RECT  15.36 49.703 15.384 50.771 ;
     RECT  17.232 48.515 17.256 51.779 ;
     RECT  8.112 2.245 9.36 3.443 ;
     RECT  9.384 2.245 10.5 3.443 ;
     RECT  43.212 2.245 44.448 3.971 ;
     RECT  44.472 2.245 45.6 3.971 ;
     RECT  27.012 2.629 28.368 4.019 ;
     RECT  28.392 2.629 29.4 3.829 ;
     RECT  37.812 2.821 39.264 3.443 ;
     RECT  9.648 3.443 10.5 3.589 ;
     RECT  37.812 3.443 39.312 5.077 ;
     RECT  29.712 3.541 30.72 4.547 ;
     RECT  30.744 3.541 32.1 4.547 ;
     RECT  32.412 3.877 33.648 5.171 ;
     RECT  33.672 3.877 34.8 5.171 ;
     RECT  22.104 3.925 23.28 4.595 ;
     RECT  43.212 3.971 45.6 4.213 ;
     RECT  7.68 4.019 7.8 5.077 ;
     RECT  12.528 4.115 13.2 5.077 ;
     RECT  44.088 4.213 45.6 6.805 ;
     RECT  2.712 4.501 4.128 5.699 ;
     RECT  31.968 4.547 32.1 4.741 ;
     RECT  22.104 4.595 23.328 5.027 ;
     RECT  6.36 5.077 7.8 6.851 ;
     RECT  12.528 5.077 12.816 5.173 ;
     RECT  37.944 5.077 39.312 5.699 ;
     RECT  32.412 5.171 33.24 5.317 ;
     RECT  36.264 5.173 37.5 6.035 ;
     RECT  47.016 5.221 48.3 5.747 ;
     RECT  10.92 5.365 12.384 6.323 ;
     RECT  2.712 5.699 2.808 6.805 ;
     RECT  4.992 5.699 5.1 6.661 ;
     RECT  23.328 5.987 24 6.997 ;
     RECT  10.812 6.323 12.384 7.333 ;
     RECT  25.272 6.805 26.7 8.579 ;
     RECT  44.088 6.805 45.072 6.899 ;
     RECT  21.612 6.997 22.848 7.523 ;
     RECT  22.872 6.997 24 7.093 ;
     RECT  22.92 7.093 24 7.381 ;
     RECT  11.256 7.333 12.384 7.957 ;
     RECT  2.808 7.381 3.936 8.003 ;
     RECT  3.96 7.381 4.992 8.437 ;
     RECT  21.612 7.523 22.896 9.731 ;
     RECT  40.512 7.621 41.664 7.909 ;
     RECT  40.512 7.909 41.616 9.779 ;
     RECT  2.712 8.003 3.936 8.483 ;
     RECT  2.712 8.483 4.224 9.971 ;
     RECT  16.68 8.485 18 9.253 ;
     RECT  11.256 8.627 12.384 10.163 ;
     RECT  36.216 8.771 37.5 9.779 ;
     RECT  37.812 9.109 38.784 10.307 ;
     RECT  38.808 9.109 40.2 10.307 ;
     RECT  5.688 9.397 7.008 10.789 ;
     RECT  18.912 9.685 20.4 9.923 ;
     RECT  21.612 9.731 21.72 10.357 ;
     RECT  23.328 9.731 23.616 11.173 ;
     RECT  35.304 9.779 35.4 10.741 ;
     RECT  40.512 9.779 41.904 21.061 ;
     RECT  21.168 9.923 21.3 11.173 ;
     RECT  11.256 10.163 12.816 11.317 ;
     RECT  37.812 10.307 38.232 11.221 ;
     RECT  13.512 10.355 13.608 11.461 ;
     RECT  29.28 10.355 29.4 11.749 ;
     RECT  32.76 10.499 33.096 11.317 ;
     RECT  21.864 11.269 23.328 12.805 ;
     RECT  11.256 11.317 12.672 11.941 ;
     RECT  32.76 11.317 33.792 12.227 ;
     RECT  33.816 11.317 34.8 14.003 ;
     RECT  27.012 11.749 28.512 13.139 ;
     RECT  11.688 11.941 12.672 12.229 ;
     RECT  32.412 12.227 33.792 13.957 ;
     RECT  1.272 12.229 2.4 12.371 ;
     RECT  38.232 12.325 39.552 13.093 ;
     RECT  6.36 12.563 7.8 13.715 ;
     RECT  21.912 12.805 23.328 12.901 ;
     RECT  43.212 13.045 44.448 14.867 ;
     RECT  44.472 13.045 45.6 14.867 ;
     RECT  38.472 13.093 39.552 17.029 ;
     RECT  22.632 13.139 24 15.349 ;
     RECT  7.344 13.715 7.8 13.861 ;
     RECT  45.912 13.861 46.944 15.061 ;
     RECT  46.968 13.861 48.3 15.971 ;
     RECT  32.412 13.957 33.6 14.819 ;
     RECT  28.992 14.003 29.4 15.349 ;
     RECT  33.624 14.003 34.8 14.819 ;
     RECT  18 15.491 18.288 15.493 ;
     RECT  17.16 15.493 18.288 16.501 ;
     RECT  35.112 15.493 36.288 16.405 ;
     RECT  36.312 16.019 37.5 21.395 ;
     RECT  13.656 16.403 14.928 18.707 ;
     RECT  17.16 16.501 18.192 18.517 ;
     RECT  8.52 17.365 9.648 17.651 ;
     RECT  35.112 17.507 36.288 18.757 ;
     RECT  41.928 17.603 42.9 19.765 ;
     RECT  27.144 17.605 28.656 18.707 ;
     RECT  22.68 18.659 24 20.147 ;
     RECT  24.648 18.757 25.872 19.045 ;
     RECT  38.472 18.803 39.6 18.851 ;
     RECT  38.472 18.851 40.2 19.957 ;
     RECT  17.16 18.995 18.6 22.165 ;
     RECT  19.464 19.333 20.928 19.523 ;
     RECT  39.096 19.957 40.2 21.395 ;
     RECT  23.664 20.147 24 21.637 ;
     RECT  41.928 20.147 42.9 26.005 ;
     RECT  25.128 20.339 26.7 21.493 ;
     RECT  10.224 20.819 10.5 22.069 ;
     RECT  40.632 21.061 41.904 21.637 ;
     RECT  19.656 21.445 20.928 25.139 ;
     RECT  25.56 21.493 26.7 26.725 ;
     RECT  44.04 21.637 45.504 22.259 ;
     RECT  33.192 21.733 34.464 22.165 ;
     RECT  37.992 22.499 38.376 23.557 ;
     RECT  40.512 22.739 41.52 23.411 ;
     RECT  29.184 22.931 29.4 23.701 ;
     RECT  33.144 23.027 34.224 24.469 ;
     RECT  40.512 23.411 41.568 23.939 ;
     RECT  38.856 23.557 40.2 23.699 ;
     RECT  27.96 23.701 29.4 24.707 ;
     RECT  40.512 23.939 41.904 26.629 ;
     RECT  5.412 24.469 6.384 26.099 ;
     RECT  6.408 24.469 7.584 26.099 ;
     RECT  16.212 24.469 17.664 25.187 ;
     RECT  32.412 24.515 33.504 28.789 ;
     RECT  19.56 25.139 20.928 27.205 ;
     RECT  16.212 25.187 18.6 26.533 ;
     RECT  12.024 25.427 13.2 27.155 ;
     RECT  7.488 26.099 7.584 26.197 ;
     RECT  13.512 26.291 13.608 27.397 ;
     RECT  16.212 26.533 17.232 26.725 ;
     RECT  17.256 26.533 18.6 28.501 ;
     RECT  40.512 26.629 41.856 29.653 ;
     RECT  25.56 26.725 26.592 27.971 ;
     RECT  31.968 26.819 32.1 27.301 ;
     RECT  11.736 27.155 13.2 28.019 ;
     RECT  19.896 27.205 20.928 28.451 ;
     RECT  29.712 27.301 30.912 29.699 ;
     RECT  30.936 27.301 32.1 29.699 ;
     RECT  13.512 27.397 14.784 27.539 ;
     RECT  41.88 27.587 42.9 32.437 ;
     RECT  16.212 27.635 17.232 29.653 ;
     RECT  9.096 27.781 10.5 28.931 ;
     RECT  27.624 28.261 29.088 28.835 ;
     RECT  43.212 28.357 44.448 29.171 ;
     RECT  44.472 28.357 45.6 28.453 ;
     RECT  36.12 28.405 37.152 29.459 ;
     RECT  19.56 28.451 20.928 28.789 ;
     RECT  35.112 28.499 36.096 29.459 ;
     RECT  17.256 28.501 18.432 29.699 ;
     RECT  19.56 28.789 20.784 32.531 ;
     RECT  32.412 29.075 33.504 30.371 ;
     RECT  35.112 29.459 37.5 29.941 ;
     RECT  40.872 29.653 41.856 30.611 ;
     RECT  17.256 29.699 18.6 30.661 ;
     RECT  35.112 29.941 36.432 30.611 ;
     RECT  36.456 29.941 37.5 30.611 ;
     RECT  16.212 30.323 17.232 38.581 ;
     RECT  40.512 30.611 41.856 40.595 ;
     RECT  17.256 30.661 18.48 33.013 ;
     RECT  21.612 30.661 23.136 32.437 ;
     RECT  38.184 30.709 39.6 31.427 ;
     RECT  2.712 32.053 4.224 33.059 ;
     RECT  27.96 32.053 29.4 33.827 ;
     RECT  21.612 32.437 22.848 33.013 ;
     RECT  11.4 32.821 12.528 32.917 ;
     RECT  17.256 33.013 18.24 35.219 ;
     RECT  21.612 33.013 22.8 34.693 ;
     RECT  33.144 33.157 34.224 33.491 ;
     RECT  35.112 33.445 36.432 33.589 ;
     RECT  36.456 33.445 37.5 34.405 ;
     RECT  32.904 33.491 34.224 34.259 ;
     RECT  35.208 33.589 36.432 34.691 ;
     RECT  27.012 33.827 27.144 34.981 ;
     RECT  11.88 34.355 13.2 35.747 ;
     RECT  5.544 34.453 7.056 35.747 ;
     RECT  21.612 34.693 22.656 34.981 ;
     RECT  22.824 34.883 24 36.899 ;
     RECT  14.088 34.885 15.36 36.563 ;
     RECT  17.256 35.219 18.288 36.515 ;
     RECT  41.88 35.363 42.9 40.595 ;
     RECT  37.812 35.509 39.312 36.515 ;
     RECT  5.544 35.747 7.8 36.035 ;
     RECT  11.688 35.747 13.2 36.085 ;
     RECT  5.412 36.035 7.8 36.997 ;
     RECT  11.688 36.085 12.768 37.573 ;
     RECT  17.256 36.515 18.6 42.085 ;
     RECT  37.812 36.515 37.944 36.901 ;
     RECT  13.512 36.563 15.36 37.573 ;
     RECT  5.412 36.997 6.864 38.963 ;
     RECT  43.944 36.997 45.264 37.619 ;
     RECT  32.412 37.429 33.6 38.195 ;
     RECT  33.624 37.429 34.8 38.195 ;
     RECT  13.512 37.573 15.024 38.963 ;
     RECT  27.816 37.573 29.28 38.243 ;
     RECT  45.912 37.573 47.328 39.347 ;
     RECT  43.212 37.619 43.368 39.109 ;
     RECT  35.112 37.667 35.208 38.581 ;
     RECT  32.412 38.195 34.8 38.725 ;
     RECT  29.976 38.533 31.344 39.107 ;
     RECT  35.112 38.581 36.192 39.637 ;
     RECT  11.688 38.723 12.768 42.181 ;
     RECT  33.336 38.725 34.8 39.637 ;
     RECT  21.612 38.819 21.912 39.877 ;
     RECT  5.412 38.963 5.736 39.493 ;
     RECT  7.392 38.963 7.8 40.309 ;
     RECT  29.832 39.107 31.344 39.541 ;
     RECT  29.832 39.541 31.296 40.355 ;
     RECT  33.336 39.637 34.56 40.499 ;
     RECT  35.928 39.923 36.912 40.499 ;
     RECT  24.648 40.165 25.968 41.747 ;
     RECT  16.212 40.595 17.232 42.181 ;
     RECT  19.32 40.741 20.544 42.035 ;
     RECT  21.72 41.075 22.248 42.133 ;
     RECT  9.096 41.557 10.5 42.467 ;
     RECT  10.92 42.227 11.952 43.379 ;
     RECT  31.296 42.419 31.968 42.709 ;
     RECT  8.232 42.467 10.5 42.661 ;
     RECT  2.712 42.469 3.984 43.763 ;
     RECT  4.008 42.469 5.1 43.763 ;
     RECT  8.232 42.661 10.32 43.861 ;
     RECT  30.696 42.709 31.968 44.245 ;
     RECT  11.976 42.755 13.056 43.331 ;
     RECT  24.552 43.285 25.968 43.765 ;
     RECT  11.976 43.331 13.2 44.483 ;
     RECT  17.256 43.331 18.48 46.259 ;
     RECT  10.812 43.379 11.952 44.483 ;
     RECT  16.212 43.379 17.232 44.341 ;
     RECT  22.2 43.379 22.248 44.437 ;
     RECT  35.784 43.621 36.912 44.483 ;
     RECT  4.896 43.763 5.1 44.725 ;
     RECT  8.232 43.861 9.456 45.491 ;
     RECT  14.232 43.909 15.36 45.923 ;
     RECT  22.2 44.437 23.472 45.157 ;
     RECT  20.88 44.483 21.168 44.485 ;
     RECT  19.8 44.485 21.168 45.011 ;
     RECT  29.712 44.531 30.768 45.731 ;
     RECT  24.312 44.579 25.68 47.699 ;
     RECT  18.912 45.011 21.168 46.069 ;
     RECT  30.792 45.011 32.1 45.731 ;
     RECT  8.112 45.491 9.456 46.211 ;
     RECT  21.612 45.731 23.04 45.971 ;
     RECT  31.968 45.731 32.1 46.645 ;
     RECT  19.848 46.069 21.168 47.845 ;
     RECT  8.112 46.211 9.552 48.179 ;
     RECT  17.256 46.259 18.6 49.703 ;
     RECT  24.312 47.699 25.824 49.475 ;
     RECT  46.44 47.701 47.856 47.939 ;
     RECT  18.912 47.891 20.304 49.475 ;
     RECT  16.212 48.515 17.232 49.689 ;
     RECT  16.02 49.689 17.232 49.703 ;
  END
END qfd_landh0d8g_107_EW_52x52
END LIBRARY
